VERSION 5.7 ;
  NOWIREEXTENSIONATPIN ON ;
  DIVIDERCHAR "/" ;
  BUSBITCHARS "[]" ;
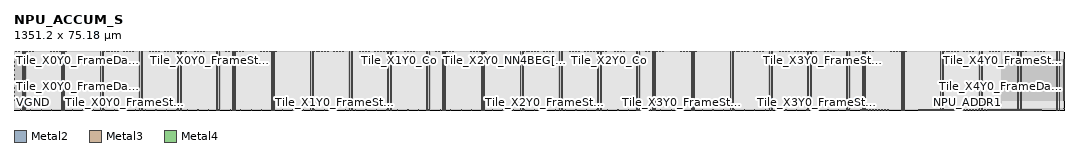
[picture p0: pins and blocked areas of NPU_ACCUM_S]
MACRO NPU_ACCUM_S
  CLASS BLOCK ;
  FOREIGN NPU_ACCUM_S ;
  ORIGIN 0.000 0.000 ;
  SIZE 1351.200 BY 75.180 ;
  PIN NPU_ADDR0
    DIRECTION OUTPUT ;
    USE SIGNAL ;
    ANTENNADIFFAREA 2.647800 ;
    PORT
      LAYER Metal2 ;
        RECT 1225.240 0.000 1225.640 0.400 ;
    END
  END NPU_ADDR0
  PIN NPU_ADDR1
    DIRECTION OUTPUT ;
    USE SIGNAL ;
    ANTENNADIFFAREA 2.647800 ;
    PORT
      LAYER Metal2 ;
        RECT 1227.160 0.000 1227.560 0.400 ;
    END
  END NPU_ADDR1
  PIN NPU_ADDR2
    DIRECTION OUTPUT ;
    USE SIGNAL ;
    ANTENNADIFFAREA 2.647800 ;
    PORT
      LAYER Metal2 ;
        RECT 1229.080 0.000 1229.480 0.400 ;
    END
  END NPU_ADDR2
  PIN NPU_ADDR3
    DIRECTION OUTPUT ;
    USE SIGNAL ;
    ANTENNADIFFAREA 2.647800 ;
    PORT
      LAYER Metal2 ;
        RECT 1231.000 0.000 1231.400 0.400 ;
    END
  END NPU_ADDR3
  PIN NPU_ADDR4
    DIRECTION OUTPUT ;
    USE SIGNAL ;
    ANTENNADIFFAREA 2.647800 ;
    PORT
      LAYER Metal2 ;
        RECT 1232.920 0.000 1233.320 0.400 ;
    END
  END NPU_ADDR4
  PIN NPU_ADDR5
    DIRECTION OUTPUT ;
    USE SIGNAL ;
    ANTENNADIFFAREA 2.647800 ;
    PORT
      LAYER Metal2 ;
        RECT 1234.840 0.000 1235.240 0.400 ;
    END
  END NPU_ADDR5
  PIN NPU_ADDR6
    DIRECTION OUTPUT ;
    USE SIGNAL ;
    ANTENNADIFFAREA 2.647800 ;
    PORT
      LAYER Metal2 ;
        RECT 1236.760 0.000 1237.160 0.400 ;
    END
  END NPU_ADDR6
  PIN NPU_ADDR7
    DIRECTION OUTPUT ;
    USE SIGNAL ;
    ANTENNADIFFAREA 2.647800 ;
    PORT
      LAYER Metal2 ;
        RECT 1238.680 0.000 1239.080 0.400 ;
    END
  END NPU_ADDR7
  PIN NPU_RDATA0
    DIRECTION INPUT ;
    USE SIGNAL ;
    ANTENNAGATEAREA 0.109200 ;
    ANTENNADIFFAREA 2.015400 ;
    PORT
      LAYER Metal2 ;
        RECT 1163.800 0.000 1164.200 0.400 ;
    END
  END NPU_RDATA0
  PIN NPU_RDATA1
    DIRECTION INPUT ;
    USE SIGNAL ;
    ANTENNAGATEAREA 0.109200 ;
    ANTENNADIFFAREA 2.015400 ;
    PORT
      LAYER Metal2 ;
        RECT 1165.720 0.000 1166.120 0.400 ;
    END
  END NPU_RDATA1
  PIN NPU_RDATA10
    DIRECTION INPUT ;
    USE SIGNAL ;
    ANTENNAGATEAREA 0.109200 ;
    ANTENNADIFFAREA 2.015400 ;
    PORT
      LAYER Metal2 ;
        RECT 1183.000 0.000 1183.400 0.400 ;
    END
  END NPU_RDATA10
  PIN NPU_RDATA11
    DIRECTION INPUT ;
    USE SIGNAL ;
    ANTENNAGATEAREA 0.109200 ;
    ANTENNADIFFAREA 2.015400 ;
    PORT
      LAYER Metal2 ;
        RECT 1184.920 0.000 1185.320 0.400 ;
    END
  END NPU_RDATA11
  PIN NPU_RDATA12
    DIRECTION INPUT ;
    USE SIGNAL ;
    ANTENNAGATEAREA 0.109200 ;
    ANTENNADIFFAREA 2.015400 ;
    PORT
      LAYER Metal2 ;
        RECT 1186.840 0.000 1187.240 0.400 ;
    END
  END NPU_RDATA12
  PIN NPU_RDATA13
    DIRECTION INPUT ;
    USE SIGNAL ;
    ANTENNAGATEAREA 0.109200 ;
    ANTENNADIFFAREA 2.015400 ;
    PORT
      LAYER Metal2 ;
        RECT 1188.760 0.000 1189.160 0.400 ;
    END
  END NPU_RDATA13
  PIN NPU_RDATA14
    DIRECTION INPUT ;
    USE SIGNAL ;
    ANTENNAGATEAREA 0.109200 ;
    ANTENNADIFFAREA 2.015400 ;
    PORT
      LAYER Metal2 ;
        RECT 1190.680 0.000 1191.080 0.400 ;
    END
  END NPU_RDATA14
  PIN NPU_RDATA15
    DIRECTION INPUT ;
    USE SIGNAL ;
    ANTENNAGATEAREA 0.109200 ;
    ANTENNADIFFAREA 2.015400 ;
    PORT
      LAYER Metal2 ;
        RECT 1192.600 0.000 1193.000 0.400 ;
    END
  END NPU_RDATA15
  PIN NPU_RDATA16
    DIRECTION INPUT ;
    USE SIGNAL ;
    ANTENNAGATEAREA 0.109200 ;
    ANTENNADIFFAREA 2.015400 ;
    PORT
      LAYER Metal2 ;
        RECT 1194.520 0.000 1194.920 0.400 ;
    END
  END NPU_RDATA16
  PIN NPU_RDATA17
    DIRECTION INPUT ;
    USE SIGNAL ;
    ANTENNAGATEAREA 0.109200 ;
    ANTENNADIFFAREA 2.015400 ;
    PORT
      LAYER Metal2 ;
        RECT 1196.440 0.000 1196.840 0.400 ;
    END
  END NPU_RDATA17
  PIN NPU_RDATA18
    DIRECTION INPUT ;
    USE SIGNAL ;
    ANTENNAGATEAREA 0.109200 ;
    ANTENNADIFFAREA 2.015400 ;
    PORT
      LAYER Metal2 ;
        RECT 1198.360 0.000 1198.760 0.400 ;
    END
  END NPU_RDATA18
  PIN NPU_RDATA19
    DIRECTION INPUT ;
    USE SIGNAL ;
    ANTENNAGATEAREA 0.109200 ;
    ANTENNADIFFAREA 2.015400 ;
    PORT
      LAYER Metal2 ;
        RECT 1200.280 0.000 1200.680 0.400 ;
    END
  END NPU_RDATA19
  PIN NPU_RDATA2
    DIRECTION INPUT ;
    USE SIGNAL ;
    ANTENNAGATEAREA 0.109200 ;
    ANTENNADIFFAREA 2.015400 ;
    PORT
      LAYER Metal2 ;
        RECT 1167.640 0.000 1168.040 0.400 ;
    END
  END NPU_RDATA2
  PIN NPU_RDATA20
    DIRECTION INPUT ;
    USE SIGNAL ;
    ANTENNAGATEAREA 0.109200 ;
    ANTENNADIFFAREA 2.015400 ;
    PORT
      LAYER Metal2 ;
        RECT 1202.200 0.000 1202.600 0.400 ;
    END
  END NPU_RDATA20
  PIN NPU_RDATA21
    DIRECTION INPUT ;
    USE SIGNAL ;
    ANTENNAGATEAREA 0.109200 ;
    ANTENNADIFFAREA 2.015400 ;
    PORT
      LAYER Metal2 ;
        RECT 1204.120 0.000 1204.520 0.400 ;
    END
  END NPU_RDATA21
  PIN NPU_RDATA22
    DIRECTION INPUT ;
    USE SIGNAL ;
    ANTENNAGATEAREA 0.109200 ;
    ANTENNADIFFAREA 2.015400 ;
    PORT
      LAYER Metal2 ;
        RECT 1206.040 0.000 1206.440 0.400 ;
    END
  END NPU_RDATA22
  PIN NPU_RDATA23
    DIRECTION INPUT ;
    USE SIGNAL ;
    ANTENNAGATEAREA 0.109200 ;
    ANTENNADIFFAREA 2.015400 ;
    PORT
      LAYER Metal2 ;
        RECT 1207.960 0.000 1208.360 0.400 ;
    END
  END NPU_RDATA23
  PIN NPU_RDATA24
    DIRECTION INPUT ;
    USE SIGNAL ;
    ANTENNAGATEAREA 0.109200 ;
    ANTENNADIFFAREA 2.015400 ;
    PORT
      LAYER Metal2 ;
        RECT 1209.880 0.000 1210.280 0.400 ;
    END
  END NPU_RDATA24
  PIN NPU_RDATA25
    DIRECTION INPUT ;
    USE SIGNAL ;
    ANTENNAGATEAREA 0.109200 ;
    ANTENNADIFFAREA 2.015400 ;
    PORT
      LAYER Metal2 ;
        RECT 1211.800 0.000 1212.200 0.400 ;
    END
  END NPU_RDATA25
  PIN NPU_RDATA26
    DIRECTION INPUT ;
    USE SIGNAL ;
    ANTENNAGATEAREA 0.109200 ;
    ANTENNADIFFAREA 2.015400 ;
    PORT
      LAYER Metal2 ;
        RECT 1213.720 0.000 1214.120 0.400 ;
    END
  END NPU_RDATA26
  PIN NPU_RDATA27
    DIRECTION INPUT ;
    USE SIGNAL ;
    ANTENNAGATEAREA 0.109200 ;
    ANTENNADIFFAREA 2.015400 ;
    PORT
      LAYER Metal2 ;
        RECT 1215.640 0.000 1216.040 0.400 ;
    END
  END NPU_RDATA27
  PIN NPU_RDATA28
    DIRECTION INPUT ;
    USE SIGNAL ;
    ANTENNAGATEAREA 0.109200 ;
    ANTENNADIFFAREA 2.015400 ;
    PORT
      LAYER Metal2 ;
        RECT 1217.560 0.000 1217.960 0.400 ;
    END
  END NPU_RDATA28
  PIN NPU_RDATA29
    DIRECTION INPUT ;
    USE SIGNAL ;
    ANTENNAGATEAREA 0.109200 ;
    ANTENNADIFFAREA 2.015400 ;
    PORT
      LAYER Metal2 ;
        RECT 1219.480 0.000 1219.880 0.400 ;
    END
  END NPU_RDATA29
  PIN NPU_RDATA3
    DIRECTION INPUT ;
    USE SIGNAL ;
    ANTENNAGATEAREA 0.109200 ;
    ANTENNADIFFAREA 2.015400 ;
    PORT
      LAYER Metal2 ;
        RECT 1169.560 0.000 1169.960 0.400 ;
    END
  END NPU_RDATA3
  PIN NPU_RDATA30
    DIRECTION INPUT ;
    USE SIGNAL ;
    ANTENNAGATEAREA 0.109200 ;
    ANTENNADIFFAREA 2.015400 ;
    PORT
      LAYER Metal2 ;
        RECT 1221.400 0.000 1221.800 0.400 ;
    END
  END NPU_RDATA30
  PIN NPU_RDATA31
    DIRECTION INPUT ;
    USE SIGNAL ;
    ANTENNAGATEAREA 0.109200 ;
    ANTENNADIFFAREA 2.015400 ;
    PORT
      LAYER Metal2 ;
        RECT 1223.320 0.000 1223.720 0.400 ;
    END
  END NPU_RDATA31
  PIN NPU_RDATA4
    DIRECTION INPUT ;
    USE SIGNAL ;
    ANTENNAGATEAREA 0.109200 ;
    ANTENNADIFFAREA 2.015400 ;
    PORT
      LAYER Metal2 ;
        RECT 1171.480 0.000 1171.880 0.400 ;
    END
  END NPU_RDATA4
  PIN NPU_RDATA5
    DIRECTION INPUT ;
    USE SIGNAL ;
    ANTENNAGATEAREA 0.109200 ;
    ANTENNADIFFAREA 2.015400 ;
    PORT
      LAYER Metal2 ;
        RECT 1173.400 0.000 1173.800 0.400 ;
    END
  END NPU_RDATA5
  PIN NPU_RDATA6
    DIRECTION INPUT ;
    USE SIGNAL ;
    ANTENNAGATEAREA 0.109200 ;
    ANTENNADIFFAREA 2.015400 ;
    PORT
      LAYER Metal2 ;
        RECT 1175.320 0.000 1175.720 0.400 ;
    END
  END NPU_RDATA6
  PIN NPU_RDATA7
    DIRECTION INPUT ;
    USE SIGNAL ;
    ANTENNAGATEAREA 0.109200 ;
    ANTENNADIFFAREA 2.015400 ;
    PORT
      LAYER Metal2 ;
        RECT 1177.240 0.000 1177.640 0.400 ;
    END
  END NPU_RDATA7
  PIN NPU_RDATA8
    DIRECTION INPUT ;
    USE SIGNAL ;
    ANTENNAGATEAREA 0.109200 ;
    ANTENNADIFFAREA 2.015400 ;
    PORT
      LAYER Metal2 ;
        RECT 1179.160 0.000 1179.560 0.400 ;
    END
  END NPU_RDATA8
  PIN NPU_RDATA9
    DIRECTION INPUT ;
    USE SIGNAL ;
    ANTENNAGATEAREA 0.109200 ;
    ANTENNADIFFAREA 2.015400 ;
    PORT
      LAYER Metal2 ;
        RECT 1181.080 0.000 1181.480 0.400 ;
    END
  END NPU_RDATA9
  PIN NPU_READ_BANK_SEL0
    DIRECTION OUTPUT ;
    USE SIGNAL ;
    ANTENNADIFFAREA 2.647800 ;
    PORT
      LAYER Metal2 ;
        RECT 1317.400 0.000 1317.800 0.400 ;
    END
  END NPU_READ_BANK_SEL0
  PIN NPU_READ_BANK_SEL1
    DIRECTION OUTPUT ;
    USE SIGNAL ;
    ANTENNADIFFAREA 2.647800 ;
    PORT
      LAYER Metal2 ;
        RECT 1319.320 0.000 1319.720 0.400 ;
    END
  END NPU_READ_BANK_SEL1
  PIN NPU_READ_BANK_SEL2
    DIRECTION OUTPUT ;
    USE SIGNAL ;
    ANTENNADIFFAREA 2.647800 ;
    PORT
      LAYER Metal2 ;
        RECT 1321.240 0.000 1321.640 0.400 ;
    END
  END NPU_READ_BANK_SEL2
  PIN NPU_WDATA0
    DIRECTION OUTPUT ;
    USE SIGNAL ;
    ANTENNADIFFAREA 2.647800 ;
    PORT
      LAYER Metal2 ;
        RECT 1255.960 0.000 1256.360 0.400 ;
    END
  END NPU_WDATA0
  PIN NPU_WDATA1
    DIRECTION OUTPUT ;
    USE SIGNAL ;
    ANTENNADIFFAREA 2.647800 ;
    PORT
      LAYER Metal2 ;
        RECT 1257.880 0.000 1258.280 0.400 ;
    END
  END NPU_WDATA1
  PIN NPU_WDATA10
    DIRECTION OUTPUT ;
    USE SIGNAL ;
    ANTENNADIFFAREA 2.647800 ;
    PORT
      LAYER Metal2 ;
        RECT 1275.160 0.000 1275.560 0.400 ;
    END
  END NPU_WDATA10
  PIN NPU_WDATA11
    DIRECTION OUTPUT ;
    USE SIGNAL ;
    ANTENNADIFFAREA 2.647800 ;
    PORT
      LAYER Metal2 ;
        RECT 1277.080 0.000 1277.480 0.400 ;
    END
  END NPU_WDATA11
  PIN NPU_WDATA12
    DIRECTION OUTPUT ;
    USE SIGNAL ;
    ANTENNADIFFAREA 2.647800 ;
    PORT
      LAYER Metal2 ;
        RECT 1279.000 0.000 1279.400 0.400 ;
    END
  END NPU_WDATA12
  PIN NPU_WDATA13
    DIRECTION OUTPUT ;
    USE SIGNAL ;
    ANTENNADIFFAREA 2.647800 ;
    PORT
      LAYER Metal2 ;
        RECT 1280.920 0.000 1281.320 0.400 ;
    END
  END NPU_WDATA13
  PIN NPU_WDATA14
    DIRECTION OUTPUT ;
    USE SIGNAL ;
    ANTENNADIFFAREA 2.647800 ;
    PORT
      LAYER Metal2 ;
        RECT 1282.840 0.000 1283.240 0.400 ;
    END
  END NPU_WDATA14
  PIN NPU_WDATA15
    DIRECTION OUTPUT ;
    USE SIGNAL ;
    ANTENNADIFFAREA 2.647800 ;
    PORT
      LAYER Metal2 ;
        RECT 1284.760 0.000 1285.160 0.400 ;
    END
  END NPU_WDATA15
  PIN NPU_WDATA16
    DIRECTION OUTPUT ;
    USE SIGNAL ;
    ANTENNADIFFAREA 2.647800 ;
    PORT
      LAYER Metal2 ;
        RECT 1286.680 0.000 1287.080 0.400 ;
    END
  END NPU_WDATA16
  PIN NPU_WDATA17
    DIRECTION OUTPUT ;
    USE SIGNAL ;
    ANTENNADIFFAREA 2.647800 ;
    PORT
      LAYER Metal2 ;
        RECT 1288.600 0.000 1289.000 0.400 ;
    END
  END NPU_WDATA17
  PIN NPU_WDATA18
    DIRECTION OUTPUT ;
    USE SIGNAL ;
    ANTENNADIFFAREA 2.647800 ;
    PORT
      LAYER Metal2 ;
        RECT 1290.520 0.000 1290.920 0.400 ;
    END
  END NPU_WDATA18
  PIN NPU_WDATA19
    DIRECTION OUTPUT ;
    USE SIGNAL ;
    ANTENNADIFFAREA 2.647800 ;
    PORT
      LAYER Metal2 ;
        RECT 1292.440 0.000 1292.840 0.400 ;
    END
  END NPU_WDATA19
  PIN NPU_WDATA2
    DIRECTION OUTPUT ;
    USE SIGNAL ;
    ANTENNADIFFAREA 2.647800 ;
    PORT
      LAYER Metal2 ;
        RECT 1259.800 0.000 1260.200 0.400 ;
    END
  END NPU_WDATA2
  PIN NPU_WDATA20
    DIRECTION OUTPUT ;
    USE SIGNAL ;
    ANTENNADIFFAREA 2.647800 ;
    PORT
      LAYER Metal2 ;
        RECT 1294.360 0.000 1294.760 0.400 ;
    END
  END NPU_WDATA20
  PIN NPU_WDATA21
    DIRECTION OUTPUT ;
    USE SIGNAL ;
    ANTENNADIFFAREA 2.647800 ;
    PORT
      LAYER Metal2 ;
        RECT 1296.280 0.000 1296.680 0.400 ;
    END
  END NPU_WDATA21
  PIN NPU_WDATA22
    DIRECTION OUTPUT ;
    USE SIGNAL ;
    ANTENNADIFFAREA 2.647800 ;
    PORT
      LAYER Metal2 ;
        RECT 1298.200 0.000 1298.600 0.400 ;
    END
  END NPU_WDATA22
  PIN NPU_WDATA23
    DIRECTION OUTPUT ;
    USE SIGNAL ;
    ANTENNADIFFAREA 2.647800 ;
    PORT
      LAYER Metal2 ;
        RECT 1300.120 0.000 1300.520 0.400 ;
    END
  END NPU_WDATA23
  PIN NPU_WDATA24
    DIRECTION OUTPUT ;
    USE SIGNAL ;
    ANTENNADIFFAREA 2.647800 ;
    PORT
      LAYER Metal2 ;
        RECT 1302.040 0.000 1302.440 0.400 ;
    END
  END NPU_WDATA24
  PIN NPU_WDATA25
    DIRECTION OUTPUT ;
    USE SIGNAL ;
    ANTENNADIFFAREA 2.647800 ;
    PORT
      LAYER Metal2 ;
        RECT 1303.960 0.000 1304.360 0.400 ;
    END
  END NPU_WDATA25
  PIN NPU_WDATA26
    DIRECTION OUTPUT ;
    USE SIGNAL ;
    ANTENNADIFFAREA 2.647800 ;
    PORT
      LAYER Metal2 ;
        RECT 1305.880 0.000 1306.280 0.400 ;
    END
  END NPU_WDATA26
  PIN NPU_WDATA27
    DIRECTION OUTPUT ;
    USE SIGNAL ;
    ANTENNADIFFAREA 2.647800 ;
    PORT
      LAYER Metal2 ;
        RECT 1307.800 0.000 1308.200 0.400 ;
    END
  END NPU_WDATA27
  PIN NPU_WDATA28
    DIRECTION OUTPUT ;
    USE SIGNAL ;
    ANTENNADIFFAREA 2.647800 ;
    PORT
      LAYER Metal2 ;
        RECT 1309.720 0.000 1310.120 0.400 ;
    END
  END NPU_WDATA28
  PIN NPU_WDATA29
    DIRECTION OUTPUT ;
    USE SIGNAL ;
    ANTENNADIFFAREA 2.647800 ;
    PORT
      LAYER Metal2 ;
        RECT 1311.640 0.000 1312.040 0.400 ;
    END
  END NPU_WDATA29
  PIN NPU_WDATA3
    DIRECTION OUTPUT ;
    USE SIGNAL ;
    ANTENNADIFFAREA 2.647800 ;
    PORT
      LAYER Metal2 ;
        RECT 1261.720 0.000 1262.120 0.400 ;
    END
  END NPU_WDATA3
  PIN NPU_WDATA30
    DIRECTION OUTPUT ;
    USE SIGNAL ;
    ANTENNADIFFAREA 2.647800 ;
    PORT
      LAYER Metal2 ;
        RECT 1313.560 0.000 1313.960 0.400 ;
    END
  END NPU_WDATA30
  PIN NPU_WDATA31
    DIRECTION OUTPUT ;
    USE SIGNAL ;
    ANTENNADIFFAREA 2.647800 ;
    PORT
      LAYER Metal2 ;
        RECT 1315.480 0.000 1315.880 0.400 ;
    END
  END NPU_WDATA31
  PIN NPU_WDATA4
    DIRECTION OUTPUT ;
    USE SIGNAL ;
    ANTENNADIFFAREA 2.647800 ;
    PORT
      LAYER Metal2 ;
        RECT 1263.640 0.000 1264.040 0.400 ;
    END
  END NPU_WDATA4
  PIN NPU_WDATA5
    DIRECTION OUTPUT ;
    USE SIGNAL ;
    ANTENNADIFFAREA 2.647800 ;
    PORT
      LAYER Metal2 ;
        RECT 1265.560 0.000 1265.960 0.400 ;
    END
  END NPU_WDATA5
  PIN NPU_WDATA6
    DIRECTION OUTPUT ;
    USE SIGNAL ;
    ANTENNADIFFAREA 2.647800 ;
    PORT
      LAYER Metal2 ;
        RECT 1267.480 0.000 1267.880 0.400 ;
    END
  END NPU_WDATA6
  PIN NPU_WDATA7
    DIRECTION OUTPUT ;
    USE SIGNAL ;
    ANTENNADIFFAREA 2.647800 ;
    PORT
      LAYER Metal2 ;
        RECT 1269.400 0.000 1269.800 0.400 ;
    END
  END NPU_WDATA7
  PIN NPU_WDATA8
    DIRECTION OUTPUT ;
    USE SIGNAL ;
    ANTENNADIFFAREA 2.647800 ;
    PORT
      LAYER Metal2 ;
        RECT 1271.320 0.000 1271.720 0.400 ;
    END
  END NPU_WDATA8
  PIN NPU_WDATA9
    DIRECTION OUTPUT ;
    USE SIGNAL ;
    ANTENNADIFFAREA 2.647800 ;
    PORT
      LAYER Metal2 ;
        RECT 1273.240 0.000 1273.640 0.400 ;
    END
  END NPU_WDATA9
  PIN NPU_WE0
    DIRECTION OUTPUT ;
    USE SIGNAL ;
    ANTENNADIFFAREA 2.647800 ;
    PORT
      LAYER Metal2 ;
        RECT 1240.600 0.000 1241.000 0.400 ;
    END
  END NPU_WE0
  PIN NPU_WE1
    DIRECTION OUTPUT ;
    USE SIGNAL ;
    ANTENNADIFFAREA 2.647800 ;
    PORT
      LAYER Metal2 ;
        RECT 1242.520 0.000 1242.920 0.400 ;
    END
  END NPU_WE1
  PIN NPU_WE2
    DIRECTION OUTPUT ;
    USE SIGNAL ;
    ANTENNADIFFAREA 2.647800 ;
    PORT
      LAYER Metal2 ;
        RECT 1244.440 0.000 1244.840 0.400 ;
    END
  END NPU_WE2
  PIN NPU_WE3
    DIRECTION OUTPUT ;
    USE SIGNAL ;
    ANTENNADIFFAREA 2.647800 ;
    PORT
      LAYER Metal2 ;
        RECT 1246.360 0.000 1246.760 0.400 ;
    END
  END NPU_WE3
  PIN NPU_WE4
    DIRECTION OUTPUT ;
    USE SIGNAL ;
    ANTENNADIFFAREA 2.647800 ;
    PORT
      LAYER Metal2 ;
        RECT 1248.280 0.000 1248.680 0.400 ;
    END
  END NPU_WE4
  PIN NPU_WE5
    DIRECTION OUTPUT ;
    USE SIGNAL ;
    ANTENNADIFFAREA 2.647800 ;
    PORT
      LAYER Metal2 ;
        RECT 1250.200 0.000 1250.600 0.400 ;
    END
  END NPU_WE5
  PIN NPU_WE6
    DIRECTION OUTPUT ;
    USE SIGNAL ;
    ANTENNADIFFAREA 2.647800 ;
    PORT
      LAYER Metal2 ;
        RECT 1252.120 0.000 1252.520 0.400 ;
    END
  END NPU_WE6
  PIN NPU_WE7
    DIRECTION OUTPUT ;
    USE SIGNAL ;
    ANTENNADIFFAREA 2.647800 ;
    PORT
      LAYER Metal2 ;
        RECT 1254.040 0.000 1254.440 0.400 ;
    END
  END NPU_WE7
  PIN Tile_X0Y0_Co
    DIRECTION OUTPUT ;
    USE SIGNAL ;
    ANTENNADIFFAREA 2.314600 ;
    PORT
      LAYER Metal2 ;
        RECT 225.880 74.780 226.280 75.180 ;
    END
  END Tile_X0Y0_Co
  PIN Tile_X0Y0_FrameData[0]
    DIRECTION INPUT ;
    USE SIGNAL ;
    ANTENNAGATEAREA 2.349100 ;
    ANTENNADIFFAREA 28.215599 ;
    PORT
      LAYER Metal3 ;
        RECT 0.000 12.820 0.400 13.220 ;
    END
  END Tile_X0Y0_FrameData[0]
  PIN Tile_X0Y0_FrameData[10]
    DIRECTION INPUT ;
    USE SIGNAL ;
    ANTENNAGATEAREA 2.349100 ;
    ANTENNADIFFAREA 34.261799 ;
    PORT
      LAYER Metal3 ;
        RECT 0.000 29.620 0.400 30.020 ;
    END
  END Tile_X0Y0_FrameData[10]
  PIN Tile_X0Y0_FrameData[11]
    DIRECTION INPUT ;
    USE SIGNAL ;
    ANTENNAGATEAREA 2.349100 ;
    ANTENNADIFFAREA 34.261799 ;
    PORT
      LAYER Metal3 ;
        RECT 0.000 31.300 0.400 31.700 ;
    END
  END Tile_X0Y0_FrameData[11]
  PIN Tile_X0Y0_FrameData[12]
    DIRECTION INPUT ;
    USE SIGNAL ;
    ANTENNAGATEAREA 2.349100 ;
    ANTENNADIFFAREA 30.230999 ;
    PORT
      LAYER Metal3 ;
        RECT 0.000 32.980 0.400 33.380 ;
    END
  END Tile_X0Y0_FrameData[12]
  PIN Tile_X0Y0_FrameData[13]
    DIRECTION INPUT ;
    USE SIGNAL ;
    ANTENNAGATEAREA 2.349100 ;
    ANTENNADIFFAREA 28.215599 ;
    PORT
      LAYER Metal3 ;
        RECT 0.000 34.660 0.400 35.060 ;
    END
  END Tile_X0Y0_FrameData[13]
  PIN Tile_X0Y0_FrameData[14]
    DIRECTION INPUT ;
    USE SIGNAL ;
    ANTENNAGATEAREA 2.349100 ;
    ANTENNADIFFAREA 34.261799 ;
    PORT
      LAYER Metal3 ;
        RECT 0.000 36.340 0.400 36.740 ;
    END
  END Tile_X0Y0_FrameData[14]
  PIN Tile_X0Y0_FrameData[15]
    DIRECTION INPUT ;
    USE SIGNAL ;
    ANTENNAGATEAREA 2.349100 ;
    ANTENNADIFFAREA 34.261799 ;
    PORT
      LAYER Metal3 ;
        RECT 0.000 38.020 0.400 38.420 ;
    END
  END Tile_X0Y0_FrameData[15]
  PIN Tile_X0Y0_FrameData[16]
    DIRECTION INPUT ;
    USE SIGNAL ;
    ANTENNAGATEAREA 2.710500 ;
    ANTENNADIFFAREA 32.246399 ;
    PORT
      LAYER Metal3 ;
        RECT 0.000 39.700 0.400 40.100 ;
    END
  END Tile_X0Y0_FrameData[16]
  PIN Tile_X0Y0_FrameData[17]
    DIRECTION INPUT ;
    USE SIGNAL ;
    ANTENNAGATEAREA 2.710500 ;
    ANTENNADIFFAREA 38.292599 ;
    PORT
      LAYER Metal3 ;
        RECT 0.000 41.380 0.400 41.780 ;
    END
  END Tile_X0Y0_FrameData[17]
  PIN Tile_X0Y0_FrameData[18]
    DIRECTION INPUT ;
    USE SIGNAL ;
    ANTENNAGATEAREA 2.891200 ;
    ANTENNADIFFAREA 32.246399 ;
    PORT
      LAYER Metal3 ;
        RECT 0.000 43.060 0.400 43.460 ;
    END
  END Tile_X0Y0_FrameData[18]
  PIN Tile_X0Y0_FrameData[19]
    DIRECTION INPUT ;
    USE SIGNAL ;
    ANTENNAGATEAREA 2.891200 ;
    ANTENNADIFFAREA 32.246399 ;
    PORT
      LAYER Metal3 ;
        RECT 0.000 44.740 0.400 45.140 ;
    END
  END Tile_X0Y0_FrameData[19]
  PIN Tile_X0Y0_FrameData[1]
    DIRECTION INPUT ;
    USE SIGNAL ;
    ANTENNAGATEAREA 2.349100 ;
    ANTENNADIFFAREA 36.277199 ;
    PORT
      LAYER Metal3 ;
        RECT 0.000 14.500 0.400 14.900 ;
    END
  END Tile_X0Y0_FrameData[1]
  PIN Tile_X0Y0_FrameData[20]
    DIRECTION INPUT ;
    USE SIGNAL ;
    ANTENNAGATEAREA 2.891200 ;
    ANTENNADIFFAREA 32.246399 ;
    PORT
      LAYER Metal3 ;
        RECT 0.000 46.420 0.400 46.820 ;
    END
  END Tile_X0Y0_FrameData[20]
  PIN Tile_X0Y0_FrameData[21]
    DIRECTION INPUT ;
    USE SIGNAL ;
    ANTENNAGATEAREA 2.891200 ;
    ANTENNADIFFAREA 34.261799 ;
    PORT
      LAYER Metal3 ;
        RECT 0.000 48.100 0.400 48.500 ;
    END
  END Tile_X0Y0_FrameData[21]
  PIN Tile_X0Y0_FrameData[22]
    DIRECTION INPUT ;
    USE SIGNAL ;
    ANTENNAGATEAREA 2.891200 ;
    ANTENNADIFFAREA 32.246399 ;
    PORT
      LAYER Metal3 ;
        RECT 0.000 49.780 0.400 50.180 ;
    END
  END Tile_X0Y0_FrameData[22]
  PIN Tile_X0Y0_FrameData[23]
    DIRECTION INPUT ;
    USE SIGNAL ;
    ANTENNAGATEAREA 2.891200 ;
    ANTENNADIFFAREA 32.246399 ;
    PORT
      LAYER Metal3 ;
        RECT 0.000 51.460 0.400 51.860 ;
    END
  END Tile_X0Y0_FrameData[23]
  PIN Tile_X0Y0_FrameData[24]
    DIRECTION INPUT ;
    USE SIGNAL ;
    ANTENNAGATEAREA 2.891200 ;
    ANTENNADIFFAREA 36.277199 ;
    PORT
      LAYER Metal3 ;
        RECT 0.000 53.140 0.400 53.540 ;
    END
  END Tile_X0Y0_FrameData[24]
  PIN Tile_X0Y0_FrameData[25]
    DIRECTION INPUT ;
    USE SIGNAL ;
    ANTENNAGATEAREA 2.891200 ;
    ANTENNADIFFAREA 34.261799 ;
    PORT
      LAYER Metal3 ;
        RECT 0.000 54.820 0.400 55.220 ;
    END
  END Tile_X0Y0_FrameData[25]
  PIN Tile_X0Y0_FrameData[26]
    DIRECTION INPUT ;
    USE SIGNAL ;
    ANTENNAGATEAREA 2.891200 ;
    ANTENNADIFFAREA 36.277199 ;
    PORT
      LAYER Metal3 ;
        RECT 0.000 56.500 0.400 56.900 ;
    END
  END Tile_X0Y0_FrameData[26]
  PIN Tile_X0Y0_FrameData[27]
    DIRECTION INPUT ;
    USE SIGNAL ;
    ANTENNAGATEAREA 2.891200 ;
    ANTENNADIFFAREA 32.246399 ;
    PORT
      LAYER Metal3 ;
        RECT 0.000 58.180 0.400 58.580 ;
    END
  END Tile_X0Y0_FrameData[27]
  PIN Tile_X0Y0_FrameData[28]
    DIRECTION INPUT ;
    USE SIGNAL ;
    ANTENNAGATEAREA 2.891200 ;
    ANTENNADIFFAREA 36.277199 ;
    PORT
      LAYER Metal3 ;
        RECT 0.000 59.860 0.400 60.260 ;
    END
  END Tile_X0Y0_FrameData[28]
  PIN Tile_X0Y0_FrameData[29]
    DIRECTION INPUT ;
    USE SIGNAL ;
    ANTENNAGATEAREA 2.891200 ;
    ANTENNADIFFAREA 34.261799 ;
    PORT
      LAYER Metal3 ;
        RECT 0.000 61.540 0.400 61.940 ;
    END
  END Tile_X0Y0_FrameData[29]
  PIN Tile_X0Y0_FrameData[2]
    DIRECTION INPUT ;
    USE SIGNAL ;
    ANTENNAGATEAREA 2.349100 ;
    ANTENNADIFFAREA 30.230999 ;
    PORT
      LAYER Metal3 ;
        RECT 0.000 16.180 0.400 16.580 ;
    END
  END Tile_X0Y0_FrameData[2]
  PIN Tile_X0Y0_FrameData[30]
    DIRECTION INPUT ;
    USE SIGNAL ;
    ANTENNAGATEAREA 2.891200 ;
    ANTENNADIFFAREA 34.261799 ;
    PORT
      LAYER Metal3 ;
        RECT 0.000 63.220 0.400 63.620 ;
    END
  END Tile_X0Y0_FrameData[30]
  PIN Tile_X0Y0_FrameData[31]
    DIRECTION INPUT ;
    USE SIGNAL ;
    ANTENNAGATEAREA 2.891200 ;
    ANTENNADIFFAREA 34.261799 ;
    PORT
      LAYER Metal3 ;
        RECT 0.000 64.900 0.400 65.300 ;
    END
  END Tile_X0Y0_FrameData[31]
  PIN Tile_X0Y0_FrameData[3]
    DIRECTION INPUT ;
    USE SIGNAL ;
    ANTENNAGATEAREA 2.349100 ;
    ANTENNADIFFAREA 30.230999 ;
    PORT
      LAYER Metal3 ;
        RECT 0.000 17.860 0.400 18.260 ;
    END
  END Tile_X0Y0_FrameData[3]
  PIN Tile_X0Y0_FrameData[4]
    DIRECTION INPUT ;
    USE SIGNAL ;
    ANTENNAGATEAREA 2.349100 ;
    ANTENNADIFFAREA 28.215599 ;
    PORT
      LAYER Metal3 ;
        RECT 0.000 19.540 0.400 19.940 ;
    END
  END Tile_X0Y0_FrameData[4]
  PIN Tile_X0Y0_FrameData[5]
    DIRECTION INPUT ;
    USE SIGNAL ;
    ANTENNAGATEAREA 2.349100 ;
    ANTENNADIFFAREA 30.230999 ;
    PORT
      LAYER Metal3 ;
        RECT 0.000 21.220 0.400 21.620 ;
    END
  END Tile_X0Y0_FrameData[5]
  PIN Tile_X0Y0_FrameData[6]
    DIRECTION INPUT ;
    USE SIGNAL ;
    ANTENNAGATEAREA 2.349100 ;
    ANTENNADIFFAREA 28.215599 ;
    PORT
      LAYER Metal3 ;
        RECT 0.000 22.900 0.400 23.300 ;
    END
  END Tile_X0Y0_FrameData[6]
  PIN Tile_X0Y0_FrameData[7]
    DIRECTION INPUT ;
    USE SIGNAL ;
    ANTENNAGATEAREA 2.349100 ;
    ANTENNADIFFAREA 28.215599 ;
    PORT
      LAYER Metal3 ;
        RECT 0.000 24.580 0.400 24.980 ;
    END
  END Tile_X0Y0_FrameData[7]
  PIN Tile_X0Y0_FrameData[8]
    DIRECTION INPUT ;
    USE SIGNAL ;
    ANTENNAGATEAREA 2.349100 ;
    ANTENNADIFFAREA 40.307999 ;
    PORT
      LAYER Metal3 ;
        RECT 0.000 26.260 0.400 26.660 ;
    END
  END Tile_X0Y0_FrameData[8]
  PIN Tile_X0Y0_FrameData[9]
    DIRECTION INPUT ;
    USE SIGNAL ;
    ANTENNAGATEAREA 2.349100 ;
    ANTENNADIFFAREA 34.261799 ;
    PORT
      LAYER Metal3 ;
        RECT 0.000 27.940 0.400 28.340 ;
    END
  END Tile_X0Y0_FrameData[9]
  PIN Tile_X0Y0_FrameStrobe[0]
    DIRECTION INPUT ;
    USE SIGNAL ;
    ANTENNAGATEAREA 11.745500 ;
    ANTENNADIFFAREA 66.508202 ;
    PORT
      LAYER Metal2 ;
        RECT 7.960 0.000 8.360 0.400 ;
    END
  END Tile_X0Y0_FrameStrobe[0]
  PIN Tile_X0Y0_FrameStrobe[10]
    DIRECTION INPUT ;
    USE SIGNAL ;
    ANTENNAGATEAREA 0.180700 ;
    ANTENNADIFFAREA 2.015400 ;
    PORT
      LAYER Metal2 ;
        RECT 142.360 0.000 142.760 0.400 ;
    END
  END Tile_X0Y0_FrameStrobe[10]
  PIN Tile_X0Y0_FrameStrobe[11]
    DIRECTION INPUT ;
    USE SIGNAL ;
    ANTENNAGATEAREA 0.180700 ;
    ANTENNADIFFAREA 2.015400 ;
    PORT
      LAYER Metal2 ;
        RECT 155.800 0.000 156.200 0.400 ;
    END
  END Tile_X0Y0_FrameStrobe[11]
  PIN Tile_X0Y0_FrameStrobe[12]
    DIRECTION INPUT ;
    USE SIGNAL ;
    ANTENNAGATEAREA 0.180700 ;
    ANTENNADIFFAREA 2.015400 ;
    PORT
      LAYER Metal2 ;
        RECT 169.240 0.000 169.640 0.400 ;
    END
  END Tile_X0Y0_FrameStrobe[12]
  PIN Tile_X0Y0_FrameStrobe[13]
    DIRECTION INPUT ;
    USE SIGNAL ;
    ANTENNAGATEAREA 0.180700 ;
    ANTENNADIFFAREA 2.015400 ;
    PORT
      LAYER Metal2 ;
        RECT 182.680 0.000 183.080 0.400 ;
    END
  END Tile_X0Y0_FrameStrobe[13]
  PIN Tile_X0Y0_FrameStrobe[14]
    DIRECTION INPUT ;
    USE SIGNAL ;
    ANTENNAGATEAREA 0.180700 ;
    ANTENNADIFFAREA 2.015400 ;
    PORT
      LAYER Metal2 ;
        RECT 196.120 0.000 196.520 0.400 ;
    END
  END Tile_X0Y0_FrameStrobe[14]
  PIN Tile_X0Y0_FrameStrobe[15]
    DIRECTION INPUT ;
    USE SIGNAL ;
    ANTENNAGATEAREA 0.180700 ;
    ANTENNADIFFAREA 2.015400 ;
    PORT
      LAYER Metal2 ;
        RECT 209.560 0.000 209.960 0.400 ;
    END
  END Tile_X0Y0_FrameStrobe[15]
  PIN Tile_X0Y0_FrameStrobe[16]
    DIRECTION INPUT ;
    USE SIGNAL ;
    ANTENNAGATEAREA 0.180700 ;
    ANTENNADIFFAREA 2.015400 ;
    PORT
      LAYER Metal2 ;
        RECT 223.000 0.000 223.400 0.400 ;
    END
  END Tile_X0Y0_FrameStrobe[16]
  PIN Tile_X0Y0_FrameStrobe[17]
    DIRECTION INPUT ;
    USE SIGNAL ;
    ANTENNAGATEAREA 0.180700 ;
    ANTENNADIFFAREA 2.015400 ;
    PORT
      LAYER Metal2 ;
        RECT 236.440 0.000 236.840 0.400 ;
    END
  END Tile_X0Y0_FrameStrobe[17]
  PIN Tile_X0Y0_FrameStrobe[18]
    DIRECTION INPUT ;
    USE SIGNAL ;
    ANTENNAGATEAREA 0.180700 ;
    ANTENNADIFFAREA 2.015400 ;
    PORT
      LAYER Metal2 ;
        RECT 249.880 0.000 250.280 0.400 ;
    END
  END Tile_X0Y0_FrameStrobe[18]
  PIN Tile_X0Y0_FrameStrobe[19]
    DIRECTION INPUT ;
    USE SIGNAL ;
    ANTENNAGATEAREA 0.180700 ;
    ANTENNADIFFAREA 2.015400 ;
    PORT
      LAYER Metal2 ;
        RECT 263.320 0.000 263.720 0.400 ;
    END
  END Tile_X0Y0_FrameStrobe[19]
  PIN Tile_X0Y0_FrameStrobe[1]
    DIRECTION INPUT ;
    USE SIGNAL ;
    ANTENNAGATEAREA 11.745500 ;
    ANTENNADIFFAREA 66.508202 ;
    PORT
      LAYER Metal2 ;
        RECT 21.400 0.000 21.800 0.400 ;
    END
  END Tile_X0Y0_FrameStrobe[1]
  PIN Tile_X0Y0_FrameStrobe[2]
    DIRECTION INPUT ;
    USE SIGNAL ;
    ANTENNAGATEAREA 11.745500 ;
    ANTENNADIFFAREA 66.508202 ;
    PORT
      LAYER Metal2 ;
        RECT 34.840 0.000 35.240 0.400 ;
    END
  END Tile_X0Y0_FrameStrobe[2]
  PIN Tile_X0Y0_FrameStrobe[3]
    DIRECTION INPUT ;
    USE SIGNAL ;
    ANTENNAGATEAREA 5.963100 ;
    ANTENNADIFFAREA 34.261799 ;
    PORT
      LAYER Metal2 ;
        RECT 48.280 0.000 48.680 0.400 ;
    END
  END Tile_X0Y0_FrameStrobe[3]
  PIN Tile_X0Y0_FrameStrobe[4]
    DIRECTION INPUT ;
    USE SIGNAL ;
    ANTENNAGATEAREA 0.180700 ;
    ANTENNADIFFAREA 2.015400 ;
    PORT
      LAYER Metal2 ;
        RECT 61.720 0.000 62.120 0.400 ;
    END
  END Tile_X0Y0_FrameStrobe[4]
  PIN Tile_X0Y0_FrameStrobe[5]
    DIRECTION INPUT ;
    USE SIGNAL ;
    ANTENNAGATEAREA 0.180700 ;
    ANTENNADIFFAREA 2.015400 ;
    PORT
      LAYER Metal2 ;
        RECT 75.160 0.000 75.560 0.400 ;
    END
  END Tile_X0Y0_FrameStrobe[5]
  PIN Tile_X0Y0_FrameStrobe[6]
    DIRECTION INPUT ;
    USE SIGNAL ;
    ANTENNAGATEAREA 0.180700 ;
    ANTENNADIFFAREA 2.015400 ;
    PORT
      LAYER Metal2 ;
        RECT 88.600 0.000 89.000 0.400 ;
    END
  END Tile_X0Y0_FrameStrobe[6]
  PIN Tile_X0Y0_FrameStrobe[7]
    DIRECTION INPUT ;
    USE SIGNAL ;
    ANTENNAGATEAREA 0.180700 ;
    ANTENNADIFFAREA 2.015400 ;
    PORT
      LAYER Metal2 ;
        RECT 102.040 0.000 102.440 0.400 ;
    END
  END Tile_X0Y0_FrameStrobe[7]
  PIN Tile_X0Y0_FrameStrobe[8]
    DIRECTION INPUT ;
    USE SIGNAL ;
    ANTENNAGATEAREA 0.180700 ;
    ANTENNADIFFAREA 2.015400 ;
    PORT
      LAYER Metal2 ;
        RECT 115.480 0.000 115.880 0.400 ;
    END
  END Tile_X0Y0_FrameStrobe[8]
  PIN Tile_X0Y0_FrameStrobe[9]
    DIRECTION INPUT ;
    USE SIGNAL ;
    ANTENNAGATEAREA 0.180700 ;
    ANTENNADIFFAREA 2.015400 ;
    PORT
      LAYER Metal2 ;
        RECT 128.920 0.000 129.320 0.400 ;
    END
  END Tile_X0Y0_FrameStrobe[9]
  PIN Tile_X0Y0_FrameStrobe_O[0]
    DIRECTION OUTPUT ;
    USE SIGNAL ;
    ANTENNADIFFAREA 2.724000 ;
    PORT
      LAYER Metal2 ;
        RECT 230.680 74.780 231.080 75.180 ;
    END
  END Tile_X0Y0_FrameStrobe_O[0]
  PIN Tile_X0Y0_FrameStrobe_O[10]
    DIRECTION OUTPUT ;
    USE SIGNAL ;
    ANTENNADIFFAREA 2.724000 ;
    PORT
      LAYER Metal2 ;
        RECT 249.880 74.780 250.280 75.180 ;
    END
  END Tile_X0Y0_FrameStrobe_O[10]
  PIN Tile_X0Y0_FrameStrobe_O[11]
    DIRECTION OUTPUT ;
    USE SIGNAL ;
    ANTENNADIFFAREA 2.724000 ;
    PORT
      LAYER Metal2 ;
        RECT 251.800 74.780 252.200 75.180 ;
    END
  END Tile_X0Y0_FrameStrobe_O[11]
  PIN Tile_X0Y0_FrameStrobe_O[12]
    DIRECTION OUTPUT ;
    USE SIGNAL ;
    ANTENNADIFFAREA 2.724000 ;
    PORT
      LAYER Metal2 ;
        RECT 253.720 74.780 254.120 75.180 ;
    END
  END Tile_X0Y0_FrameStrobe_O[12]
  PIN Tile_X0Y0_FrameStrobe_O[13]
    DIRECTION OUTPUT ;
    USE SIGNAL ;
    ANTENNADIFFAREA 2.724000 ;
    PORT
      LAYER Metal2 ;
        RECT 255.640 74.780 256.040 75.180 ;
    END
  END Tile_X0Y0_FrameStrobe_O[13]
  PIN Tile_X0Y0_FrameStrobe_O[14]
    DIRECTION OUTPUT ;
    USE SIGNAL ;
    ANTENNADIFFAREA 2.724000 ;
    PORT
      LAYER Metal2 ;
        RECT 257.560 74.780 257.960 75.180 ;
    END
  END Tile_X0Y0_FrameStrobe_O[14]
  PIN Tile_X0Y0_FrameStrobe_O[15]
    DIRECTION OUTPUT ;
    USE SIGNAL ;
    ANTENNADIFFAREA 2.724000 ;
    PORT
      LAYER Metal2 ;
        RECT 259.480 74.780 259.880 75.180 ;
    END
  END Tile_X0Y0_FrameStrobe_O[15]
  PIN Tile_X0Y0_FrameStrobe_O[16]
    DIRECTION OUTPUT ;
    USE SIGNAL ;
    ANTENNADIFFAREA 2.724000 ;
    PORT
      LAYER Metal2 ;
        RECT 261.400 74.780 261.800 75.180 ;
    END
  END Tile_X0Y0_FrameStrobe_O[16]
  PIN Tile_X0Y0_FrameStrobe_O[17]
    DIRECTION OUTPUT ;
    USE SIGNAL ;
    ANTENNADIFFAREA 2.724000 ;
    PORT
      LAYER Metal2 ;
        RECT 263.320 74.780 263.720 75.180 ;
    END
  END Tile_X0Y0_FrameStrobe_O[17]
  PIN Tile_X0Y0_FrameStrobe_O[18]
    DIRECTION OUTPUT ;
    USE SIGNAL ;
    ANTENNADIFFAREA 2.724000 ;
    PORT
      LAYER Metal2 ;
        RECT 265.240 74.780 265.640 75.180 ;
    END
  END Tile_X0Y0_FrameStrobe_O[18]
  PIN Tile_X0Y0_FrameStrobe_O[19]
    DIRECTION OUTPUT ;
    USE SIGNAL ;
    ANTENNADIFFAREA 2.724000 ;
    PORT
      LAYER Metal2 ;
        RECT 267.160 74.780 267.560 75.180 ;
    END
  END Tile_X0Y0_FrameStrobe_O[19]
  PIN Tile_X0Y0_FrameStrobe_O[1]
    DIRECTION OUTPUT ;
    USE SIGNAL ;
    ANTENNADIFFAREA 2.724000 ;
    PORT
      LAYER Metal2 ;
        RECT 232.600 74.780 233.000 75.180 ;
    END
  END Tile_X0Y0_FrameStrobe_O[1]
  PIN Tile_X0Y0_FrameStrobe_O[2]
    DIRECTION OUTPUT ;
    USE SIGNAL ;
    ANTENNADIFFAREA 2.724000 ;
    PORT
      LAYER Metal2 ;
        RECT 234.520 74.780 234.920 75.180 ;
    END
  END Tile_X0Y0_FrameStrobe_O[2]
  PIN Tile_X0Y0_FrameStrobe_O[3]
    DIRECTION OUTPUT ;
    USE SIGNAL ;
    ANTENNADIFFAREA 2.724000 ;
    PORT
      LAYER Metal2 ;
        RECT 236.440 74.780 236.840 75.180 ;
    END
  END Tile_X0Y0_FrameStrobe_O[3]
  PIN Tile_X0Y0_FrameStrobe_O[4]
    DIRECTION OUTPUT ;
    USE SIGNAL ;
    ANTENNADIFFAREA 2.724000 ;
    PORT
      LAYER Metal2 ;
        RECT 238.360 74.780 238.760 75.180 ;
    END
  END Tile_X0Y0_FrameStrobe_O[4]
  PIN Tile_X0Y0_FrameStrobe_O[5]
    DIRECTION OUTPUT ;
    USE SIGNAL ;
    ANTENNADIFFAREA 2.724000 ;
    PORT
      LAYER Metal2 ;
        RECT 240.280 74.780 240.680 75.180 ;
    END
  END Tile_X0Y0_FrameStrobe_O[5]
  PIN Tile_X0Y0_FrameStrobe_O[6]
    DIRECTION OUTPUT ;
    USE SIGNAL ;
    ANTENNADIFFAREA 2.724000 ;
    PORT
      LAYER Metal2 ;
        RECT 242.200 74.780 242.600 75.180 ;
    END
  END Tile_X0Y0_FrameStrobe_O[6]
  PIN Tile_X0Y0_FrameStrobe_O[7]
    DIRECTION OUTPUT ;
    USE SIGNAL ;
    ANTENNADIFFAREA 2.724000 ;
    PORT
      LAYER Metal2 ;
        RECT 244.120 74.780 244.520 75.180 ;
    END
  END Tile_X0Y0_FrameStrobe_O[7]
  PIN Tile_X0Y0_FrameStrobe_O[8]
    DIRECTION OUTPUT ;
    USE SIGNAL ;
    ANTENNADIFFAREA 2.724000 ;
    PORT
      LAYER Metal2 ;
        RECT 246.040 74.780 246.440 75.180 ;
    END
  END Tile_X0Y0_FrameStrobe_O[8]
  PIN Tile_X0Y0_FrameStrobe_O[9]
    DIRECTION OUTPUT ;
    USE SIGNAL ;
    ANTENNADIFFAREA 2.724000 ;
    PORT
      LAYER Metal2 ;
        RECT 247.960 74.780 248.360 75.180 ;
    END
  END Tile_X0Y0_FrameStrobe_O[9]
  PIN Tile_X0Y0_N1BEG[0]
    DIRECTION OUTPUT ;
    USE SIGNAL ;
    ANTENNADIFFAREA 2.724000 ;
    PORT
      LAYER Metal2 ;
        RECT 2.200 74.780 2.600 75.180 ;
    END
  END Tile_X0Y0_N1BEG[0]
  PIN Tile_X0Y0_N1BEG[1]
    DIRECTION OUTPUT ;
    USE SIGNAL ;
    ANTENNADIFFAREA 2.724000 ;
    PORT
      LAYER Metal2 ;
        RECT 4.120 74.780 4.520 75.180 ;
    END
  END Tile_X0Y0_N1BEG[1]
  PIN Tile_X0Y0_N1BEG[2]
    DIRECTION OUTPUT ;
    USE SIGNAL ;
    ANTENNADIFFAREA 2.724000 ;
    PORT
      LAYER Metal2 ;
        RECT 6.040 74.780 6.440 75.180 ;
    END
  END Tile_X0Y0_N1BEG[2]
  PIN Tile_X0Y0_N1BEG[3]
    DIRECTION OUTPUT ;
    USE SIGNAL ;
    ANTENNADIFFAREA 2.724000 ;
    PORT
      LAYER Metal2 ;
        RECT 7.960 74.780 8.360 75.180 ;
    END
  END Tile_X0Y0_N1BEG[3]
  PIN Tile_X0Y0_N2BEG[0]
    DIRECTION OUTPUT ;
    USE SIGNAL ;
    ANTENNADIFFAREA 2.724000 ;
    PORT
      LAYER Metal2 ;
        RECT 10.840 74.780 11.240 75.180 ;
    END
  END Tile_X0Y0_N2BEG[0]
  PIN Tile_X0Y0_N2BEG[1]
    DIRECTION OUTPUT ;
    USE SIGNAL ;
    ANTENNADIFFAREA 2.724000 ;
    PORT
      LAYER Metal2 ;
        RECT 12.760 74.780 13.160 75.180 ;
    END
  END Tile_X0Y0_N2BEG[1]
  PIN Tile_X0Y0_N2BEG[2]
    DIRECTION OUTPUT ;
    USE SIGNAL ;
    ANTENNADIFFAREA 2.724000 ;
    PORT
      LAYER Metal2 ;
        RECT 14.680 74.780 15.080 75.180 ;
    END
  END Tile_X0Y0_N2BEG[2]
  PIN Tile_X0Y0_N2BEG[3]
    DIRECTION OUTPUT ;
    USE SIGNAL ;
    ANTENNADIFFAREA 2.724000 ;
    PORT
      LAYER Metal2 ;
        RECT 16.600 74.780 17.000 75.180 ;
    END
  END Tile_X0Y0_N2BEG[3]
  PIN Tile_X0Y0_N2BEG[4]
    DIRECTION OUTPUT ;
    USE SIGNAL ;
    ANTENNADIFFAREA 2.724000 ;
    PORT
      LAYER Metal2 ;
        RECT 18.520 74.780 18.920 75.180 ;
    END
  END Tile_X0Y0_N2BEG[4]
  PIN Tile_X0Y0_N2BEG[5]
    DIRECTION OUTPUT ;
    USE SIGNAL ;
    ANTENNADIFFAREA 2.724000 ;
    PORT
      LAYER Metal2 ;
        RECT 20.440 74.780 20.840 75.180 ;
    END
  END Tile_X0Y0_N2BEG[5]
  PIN Tile_X0Y0_N2BEG[6]
    DIRECTION OUTPUT ;
    USE SIGNAL ;
    ANTENNADIFFAREA 2.724000 ;
    PORT
      LAYER Metal2 ;
        RECT 22.360 74.780 22.760 75.180 ;
    END
  END Tile_X0Y0_N2BEG[6]
  PIN Tile_X0Y0_N2BEG[7]
    DIRECTION OUTPUT ;
    USE SIGNAL ;
    ANTENNADIFFAREA 2.724000 ;
    PORT
      LAYER Metal2 ;
        RECT 24.280 74.780 24.680 75.180 ;
    END
  END Tile_X0Y0_N2BEG[7]
  PIN Tile_X0Y0_N2BEGb[0]
    DIRECTION OUTPUT ;
    USE SIGNAL ;
    ANTENNADIFFAREA 2.724000 ;
    PORT
      LAYER Metal2 ;
        RECT 27.160 74.780 27.560 75.180 ;
    END
  END Tile_X0Y0_N2BEGb[0]
  PIN Tile_X0Y0_N2BEGb[1]
    DIRECTION OUTPUT ;
    USE SIGNAL ;
    ANTENNADIFFAREA 2.724000 ;
    PORT
      LAYER Metal2 ;
        RECT 29.080 74.780 29.480 75.180 ;
    END
  END Tile_X0Y0_N2BEGb[1]
  PIN Tile_X0Y0_N2BEGb[2]
    DIRECTION OUTPUT ;
    USE SIGNAL ;
    ANTENNADIFFAREA 2.724000 ;
    PORT
      LAYER Metal2 ;
        RECT 31.000 74.780 31.400 75.180 ;
    END
  END Tile_X0Y0_N2BEGb[2]
  PIN Tile_X0Y0_N2BEGb[3]
    DIRECTION OUTPUT ;
    USE SIGNAL ;
    ANTENNADIFFAREA 2.724000 ;
    PORT
      LAYER Metal2 ;
        RECT 32.920 74.780 33.320 75.180 ;
    END
  END Tile_X0Y0_N2BEGb[3]
  PIN Tile_X0Y0_N2BEGb[4]
    DIRECTION OUTPUT ;
    USE SIGNAL ;
    ANTENNADIFFAREA 2.724000 ;
    PORT
      LAYER Metal2 ;
        RECT 34.840 74.780 35.240 75.180 ;
    END
  END Tile_X0Y0_N2BEGb[4]
  PIN Tile_X0Y0_N2BEGb[5]
    DIRECTION OUTPUT ;
    USE SIGNAL ;
    ANTENNADIFFAREA 2.724000 ;
    PORT
      LAYER Metal2 ;
        RECT 36.760 74.780 37.160 75.180 ;
    END
  END Tile_X0Y0_N2BEGb[5]
  PIN Tile_X0Y0_N2BEGb[6]
    DIRECTION OUTPUT ;
    USE SIGNAL ;
    ANTENNADIFFAREA 2.724000 ;
    PORT
      LAYER Metal2 ;
        RECT 38.680 74.780 39.080 75.180 ;
    END
  END Tile_X0Y0_N2BEGb[6]
  PIN Tile_X0Y0_N2BEGb[7]
    DIRECTION OUTPUT ;
    USE SIGNAL ;
    ANTENNADIFFAREA 2.724000 ;
    PORT
      LAYER Metal2 ;
        RECT 40.600 74.780 41.000 75.180 ;
    END
  END Tile_X0Y0_N2BEGb[7]
  PIN Tile_X0Y0_N4BEG[0]
    DIRECTION OUTPUT ;
    USE SIGNAL ;
    ANTENNADIFFAREA 2.724000 ;
    PORT
      LAYER Metal2 ;
        RECT 45.400 74.780 45.800 75.180 ;
    END
  END Tile_X0Y0_N4BEG[0]
  PIN Tile_X0Y0_N4BEG[10]
    DIRECTION OUTPUT ;
    USE SIGNAL ;
    ANTENNADIFFAREA 2.724000 ;
    PORT
      LAYER Metal2 ;
        RECT 64.600 74.780 65.000 75.180 ;
    END
  END Tile_X0Y0_N4BEG[10]
  PIN Tile_X0Y0_N4BEG[11]
    DIRECTION OUTPUT ;
    USE SIGNAL ;
    ANTENNADIFFAREA 2.724000 ;
    PORT
      LAYER Metal2 ;
        RECT 66.520 74.780 66.920 75.180 ;
    END
  END Tile_X0Y0_N4BEG[11]
  PIN Tile_X0Y0_N4BEG[12]
    DIRECTION OUTPUT ;
    USE SIGNAL ;
    ANTENNADIFFAREA 2.724000 ;
    PORT
      LAYER Metal2 ;
        RECT 68.440 74.780 68.840 75.180 ;
    END
  END Tile_X0Y0_N4BEG[12]
  PIN Tile_X0Y0_N4BEG[13]
    DIRECTION OUTPUT ;
    USE SIGNAL ;
    ANTENNADIFFAREA 2.724000 ;
    PORT
      LAYER Metal2 ;
        RECT 70.360 74.780 70.760 75.180 ;
    END
  END Tile_X0Y0_N4BEG[13]
  PIN Tile_X0Y0_N4BEG[14]
    DIRECTION OUTPUT ;
    USE SIGNAL ;
    ANTENNADIFFAREA 2.724000 ;
    PORT
      LAYER Metal2 ;
        RECT 72.280 74.780 72.680 75.180 ;
    END
  END Tile_X0Y0_N4BEG[14]
  PIN Tile_X0Y0_N4BEG[15]
    DIRECTION OUTPUT ;
    USE SIGNAL ;
    ANTENNADIFFAREA 2.724000 ;
    PORT
      LAYER Metal2 ;
        RECT 74.200 74.780 74.600 75.180 ;
    END
  END Tile_X0Y0_N4BEG[15]
  PIN Tile_X0Y0_N4BEG[1]
    DIRECTION OUTPUT ;
    USE SIGNAL ;
    ANTENNADIFFAREA 2.724000 ;
    PORT
      LAYER Metal2 ;
        RECT 47.320 74.780 47.720 75.180 ;
    END
  END Tile_X0Y0_N4BEG[1]
  PIN Tile_X0Y0_N4BEG[2]
    DIRECTION OUTPUT ;
    USE SIGNAL ;
    ANTENNADIFFAREA 2.724000 ;
    PORT
      LAYER Metal2 ;
        RECT 49.240 74.780 49.640 75.180 ;
    END
  END Tile_X0Y0_N4BEG[2]
  PIN Tile_X0Y0_N4BEG[3]
    DIRECTION OUTPUT ;
    USE SIGNAL ;
    ANTENNADIFFAREA 2.724000 ;
    PORT
      LAYER Metal2 ;
        RECT 51.160 74.780 51.560 75.180 ;
    END
  END Tile_X0Y0_N4BEG[3]
  PIN Tile_X0Y0_N4BEG[4]
    DIRECTION OUTPUT ;
    USE SIGNAL ;
    ANTENNADIFFAREA 2.724000 ;
    PORT
      LAYER Metal2 ;
        RECT 53.080 74.780 53.480 75.180 ;
    END
  END Tile_X0Y0_N4BEG[4]
  PIN Tile_X0Y0_N4BEG[5]
    DIRECTION OUTPUT ;
    USE SIGNAL ;
    ANTENNADIFFAREA 2.724000 ;
    PORT
      LAYER Metal2 ;
        RECT 55.000 74.780 55.400 75.180 ;
    END
  END Tile_X0Y0_N4BEG[5]
  PIN Tile_X0Y0_N4BEG[6]
    DIRECTION OUTPUT ;
    USE SIGNAL ;
    ANTENNADIFFAREA 2.724000 ;
    PORT
      LAYER Metal2 ;
        RECT 56.920 74.780 57.320 75.180 ;
    END
  END Tile_X0Y0_N4BEG[6]
  PIN Tile_X0Y0_N4BEG[7]
    DIRECTION OUTPUT ;
    USE SIGNAL ;
    ANTENNADIFFAREA 2.724000 ;
    PORT
      LAYER Metal2 ;
        RECT 58.840 74.780 59.240 75.180 ;
    END
  END Tile_X0Y0_N4BEG[7]
  PIN Tile_X0Y0_N4BEG[8]
    DIRECTION OUTPUT ;
    USE SIGNAL ;
    ANTENNADIFFAREA 2.724000 ;
    PORT
      LAYER Metal2 ;
        RECT 60.760 74.780 61.160 75.180 ;
    END
  END Tile_X0Y0_N4BEG[8]
  PIN Tile_X0Y0_N4BEG[9]
    DIRECTION OUTPUT ;
    USE SIGNAL ;
    ANTENNADIFFAREA 2.724000 ;
    PORT
      LAYER Metal2 ;
        RECT 62.680 74.780 63.080 75.180 ;
    END
  END Tile_X0Y0_N4BEG[9]
  PIN Tile_X0Y0_NN4BEG[0]
    DIRECTION OUTPUT ;
    USE SIGNAL ;
    ANTENNADIFFAREA 2.724000 ;
    PORT
      LAYER Metal2 ;
        RECT 79.960 74.780 80.360 75.180 ;
    END
  END Tile_X0Y0_NN4BEG[0]
  PIN Tile_X0Y0_NN4BEG[10]
    DIRECTION OUTPUT ;
    USE SIGNAL ;
    ANTENNADIFFAREA 2.724000 ;
    PORT
      LAYER Metal2 ;
        RECT 99.160 74.780 99.560 75.180 ;
    END
  END Tile_X0Y0_NN4BEG[10]
  PIN Tile_X0Y0_NN4BEG[11]
    DIRECTION OUTPUT ;
    USE SIGNAL ;
    ANTENNADIFFAREA 2.724000 ;
    PORT
      LAYER Metal2 ;
        RECT 101.080 74.780 101.480 75.180 ;
    END
  END Tile_X0Y0_NN4BEG[11]
  PIN Tile_X0Y0_NN4BEG[12]
    DIRECTION OUTPUT ;
    USE SIGNAL ;
    ANTENNADIFFAREA 2.724000 ;
    PORT
      LAYER Metal2 ;
        RECT 103.000 74.780 103.400 75.180 ;
    END
  END Tile_X0Y0_NN4BEG[12]
  PIN Tile_X0Y0_NN4BEG[13]
    DIRECTION OUTPUT ;
    USE SIGNAL ;
    ANTENNADIFFAREA 2.724000 ;
    PORT
      LAYER Metal2 ;
        RECT 104.920 74.780 105.320 75.180 ;
    END
  END Tile_X0Y0_NN4BEG[13]
  PIN Tile_X0Y0_NN4BEG[14]
    DIRECTION OUTPUT ;
    USE SIGNAL ;
    ANTENNADIFFAREA 2.724000 ;
    PORT
      LAYER Metal2 ;
        RECT 106.840 74.780 107.240 75.180 ;
    END
  END Tile_X0Y0_NN4BEG[14]
  PIN Tile_X0Y0_NN4BEG[15]
    DIRECTION OUTPUT ;
    USE SIGNAL ;
    ANTENNADIFFAREA 2.724000 ;
    PORT
      LAYER Metal2 ;
        RECT 108.760 74.780 109.160 75.180 ;
    END
  END Tile_X0Y0_NN4BEG[15]
  PIN Tile_X0Y0_NN4BEG[1]
    DIRECTION OUTPUT ;
    USE SIGNAL ;
    ANTENNADIFFAREA 2.724000 ;
    PORT
      LAYER Metal2 ;
        RECT 81.880 74.780 82.280 75.180 ;
    END
  END Tile_X0Y0_NN4BEG[1]
  PIN Tile_X0Y0_NN4BEG[2]
    DIRECTION OUTPUT ;
    USE SIGNAL ;
    ANTENNADIFFAREA 2.724000 ;
    PORT
      LAYER Metal2 ;
        RECT 83.800 74.780 84.200 75.180 ;
    END
  END Tile_X0Y0_NN4BEG[2]
  PIN Tile_X0Y0_NN4BEG[3]
    DIRECTION OUTPUT ;
    USE SIGNAL ;
    ANTENNADIFFAREA 2.724000 ;
    PORT
      LAYER Metal2 ;
        RECT 85.720 74.780 86.120 75.180 ;
    END
  END Tile_X0Y0_NN4BEG[3]
  PIN Tile_X0Y0_NN4BEG[4]
    DIRECTION OUTPUT ;
    USE SIGNAL ;
    ANTENNADIFFAREA 2.724000 ;
    PORT
      LAYER Metal2 ;
        RECT 87.640 74.780 88.040 75.180 ;
    END
  END Tile_X0Y0_NN4BEG[4]
  PIN Tile_X0Y0_NN4BEG[5]
    DIRECTION OUTPUT ;
    USE SIGNAL ;
    ANTENNADIFFAREA 2.724000 ;
    PORT
      LAYER Metal2 ;
        RECT 89.560 74.780 89.960 75.180 ;
    END
  END Tile_X0Y0_NN4BEG[5]
  PIN Tile_X0Y0_NN4BEG[6]
    DIRECTION OUTPUT ;
    USE SIGNAL ;
    ANTENNADIFFAREA 2.724000 ;
    PORT
      LAYER Metal2 ;
        RECT 91.480 74.780 91.880 75.180 ;
    END
  END Tile_X0Y0_NN4BEG[6]
  PIN Tile_X0Y0_NN4BEG[7]
    DIRECTION OUTPUT ;
    USE SIGNAL ;
    ANTENNADIFFAREA 2.724000 ;
    PORT
      LAYER Metal2 ;
        RECT 93.400 74.780 93.800 75.180 ;
    END
  END Tile_X0Y0_NN4BEG[7]
  PIN Tile_X0Y0_NN4BEG[8]
    DIRECTION OUTPUT ;
    USE SIGNAL ;
    ANTENNADIFFAREA 2.724000 ;
    PORT
      LAYER Metal2 ;
        RECT 95.320 74.780 95.720 75.180 ;
    END
  END Tile_X0Y0_NN4BEG[8]
  PIN Tile_X0Y0_NN4BEG[9]
    DIRECTION OUTPUT ;
    USE SIGNAL ;
    ANTENNADIFFAREA 2.724000 ;
    PORT
      LAYER Metal2 ;
        RECT 97.240 74.780 97.640 75.180 ;
    END
  END Tile_X0Y0_NN4BEG[9]
  PIN Tile_X0Y0_S1END[0]
    DIRECTION INPUT ;
    USE SIGNAL ;
    ANTENNAGATEAREA 0.607100 ;
    ANTENNADIFFAREA 6.046200 ;
    PORT
      LAYER Metal2 ;
        RECT 113.560 74.780 113.960 75.180 ;
    END
  END Tile_X0Y0_S1END[0]
  PIN Tile_X0Y0_S1END[1]
    DIRECTION INPUT ;
    USE SIGNAL ;
    ANTENNAGATEAREA 0.607100 ;
    ANTENNADIFFAREA 6.046200 ;
    PORT
      LAYER Metal2 ;
        RECT 115.480 74.780 115.880 75.180 ;
    END
  END Tile_X0Y0_S1END[1]
  PIN Tile_X0Y0_S1END[2]
    DIRECTION INPUT ;
    USE SIGNAL ;
    ANTENNAGATEAREA 0.607100 ;
    ANTENNADIFFAREA 6.046200 ;
    PORT
      LAYER Metal2 ;
        RECT 117.400 74.780 117.800 75.180 ;
    END
  END Tile_X0Y0_S1END[2]
  PIN Tile_X0Y0_S1END[3]
    DIRECTION INPUT ;
    USE SIGNAL ;
    ANTENNAGATEAREA 0.607100 ;
    ANTENNADIFFAREA 6.046200 ;
    PORT
      LAYER Metal2 ;
        RECT 119.320 74.780 119.720 75.180 ;
    END
  END Tile_X0Y0_S1END[3]
  PIN Tile_X0Y0_S2END[0]
    DIRECTION INPUT ;
    USE SIGNAL ;
    ANTENNAGATEAREA 0.639600 ;
    ANTENNADIFFAREA 6.046200 ;
    PORT
      LAYER Metal2 ;
        RECT 139.480 74.780 139.880 75.180 ;
    END
  END Tile_X0Y0_S2END[0]
  PIN Tile_X0Y0_S2END[1]
    DIRECTION INPUT ;
    USE SIGNAL ;
    ANTENNAGATEAREA 0.639600 ;
    ANTENNADIFFAREA 6.046200 ;
    PORT
      LAYER Metal2 ;
        RECT 141.400 74.780 141.800 75.180 ;
    END
  END Tile_X0Y0_S2END[1]
  PIN Tile_X0Y0_S2END[2]
    DIRECTION INPUT ;
    USE SIGNAL ;
    ANTENNAGATEAREA 0.639600 ;
    ANTENNADIFFAREA 6.046200 ;
    PORT
      LAYER Metal2 ;
        RECT 143.320 74.780 143.720 75.180 ;
    END
  END Tile_X0Y0_S2END[2]
  PIN Tile_X0Y0_S2END[3]
    DIRECTION INPUT ;
    USE SIGNAL ;
    ANTENNAGATEAREA 0.639600 ;
    ANTENNADIFFAREA 6.046200 ;
    PORT
      LAYER Metal2 ;
        RECT 145.240 74.780 145.640 75.180 ;
    END
  END Tile_X0Y0_S2END[3]
  PIN Tile_X0Y0_S2END[4]
    DIRECTION INPUT ;
    USE SIGNAL ;
    ANTENNAGATEAREA 0.639600 ;
    ANTENNADIFFAREA 6.046200 ;
    PORT
      LAYER Metal2 ;
        RECT 147.160 74.780 147.560 75.180 ;
    END
  END Tile_X0Y0_S2END[4]
  PIN Tile_X0Y0_S2END[5]
    DIRECTION INPUT ;
    USE SIGNAL ;
    ANTENNAGATEAREA 0.639600 ;
    ANTENNADIFFAREA 6.046200 ;
    PORT
      LAYER Metal2 ;
        RECT 149.080 74.780 149.480 75.180 ;
    END
  END Tile_X0Y0_S2END[5]
  PIN Tile_X0Y0_S2END[6]
    DIRECTION INPUT ;
    USE SIGNAL ;
    ANTENNAGATEAREA 0.639600 ;
    ANTENNADIFFAREA 6.046200 ;
    PORT
      LAYER Metal2 ;
        RECT 151.000 74.780 151.400 75.180 ;
    END
  END Tile_X0Y0_S2END[6]
  PIN Tile_X0Y0_S2END[7]
    DIRECTION INPUT ;
    USE SIGNAL ;
    ANTENNAGATEAREA 0.639600 ;
    ANTENNADIFFAREA 6.046200 ;
    PORT
      LAYER Metal2 ;
        RECT 152.920 74.780 153.320 75.180 ;
    END
  END Tile_X0Y0_S2END[7]
  PIN Tile_X0Y0_S2MID[0]
    DIRECTION INPUT ;
    USE SIGNAL ;
    ANTENNAGATEAREA 0.820300 ;
    ANTENNADIFFAREA 8.061600 ;
    PORT
      LAYER Metal2 ;
        RECT 122.200 74.780 122.600 75.180 ;
    END
  END Tile_X0Y0_S2MID[0]
  PIN Tile_X0Y0_S2MID[1]
    DIRECTION INPUT ;
    USE SIGNAL ;
    ANTENNAGATEAREA 0.820300 ;
    ANTENNADIFFAREA 8.061600 ;
    PORT
      LAYER Metal2 ;
        RECT 124.120 74.780 124.520 75.180 ;
    END
  END Tile_X0Y0_S2MID[1]
  PIN Tile_X0Y0_S2MID[2]
    DIRECTION INPUT ;
    USE SIGNAL ;
    ANTENNAGATEAREA 0.820300 ;
    ANTENNADIFFAREA 8.061600 ;
    PORT
      LAYER Metal2 ;
        RECT 126.040 74.780 126.440 75.180 ;
    END
  END Tile_X0Y0_S2MID[2]
  PIN Tile_X0Y0_S2MID[3]
    DIRECTION INPUT ;
    USE SIGNAL ;
    ANTENNAGATEAREA 0.820300 ;
    ANTENNADIFFAREA 8.061600 ;
    PORT
      LAYER Metal2 ;
        RECT 127.960 74.780 128.360 75.180 ;
    END
  END Tile_X0Y0_S2MID[3]
  PIN Tile_X0Y0_S2MID[4]
    DIRECTION INPUT ;
    USE SIGNAL ;
    ANTENNAGATEAREA 0.820300 ;
    ANTENNADIFFAREA 8.061600 ;
    PORT
      LAYER Metal2 ;
        RECT 129.880 74.780 130.280 75.180 ;
    END
  END Tile_X0Y0_S2MID[4]
  PIN Tile_X0Y0_S2MID[5]
    DIRECTION INPUT ;
    USE SIGNAL ;
    ANTENNAGATEAREA 0.820300 ;
    ANTENNADIFFAREA 8.061600 ;
    PORT
      LAYER Metal2 ;
        RECT 131.800 74.780 132.200 75.180 ;
    END
  END Tile_X0Y0_S2MID[5]
  PIN Tile_X0Y0_S2MID[6]
    DIRECTION INPUT ;
    USE SIGNAL ;
    ANTENNAGATEAREA 0.820300 ;
    ANTENNADIFFAREA 8.061600 ;
    PORT
      LAYER Metal2 ;
        RECT 133.720 74.780 134.120 75.180 ;
    END
  END Tile_X0Y0_S2MID[6]
  PIN Tile_X0Y0_S2MID[7]
    DIRECTION INPUT ;
    USE SIGNAL ;
    ANTENNAGATEAREA 0.820300 ;
    ANTENNADIFFAREA 8.061600 ;
    PORT
      LAYER Metal2 ;
        RECT 135.640 74.780 136.040 75.180 ;
    END
  END Tile_X0Y0_S2MID[7]
  PIN Tile_X0Y0_S4END[0]
    DIRECTION INPUT ;
    USE SIGNAL ;
    ANTENNAGATEAREA 0.852800 ;
    ANTENNADIFFAREA 8.061600 ;
    PORT
      LAYER Metal2 ;
        RECT 157.720 74.780 158.120 75.180 ;
    END
  END Tile_X0Y0_S4END[0]
  PIN Tile_X0Y0_S4END[10]
    DIRECTION INPUT ;
    USE SIGNAL ;
    ANTENNAGATEAREA 0.852800 ;
    ANTENNADIFFAREA 8.061600 ;
    PORT
      LAYER Metal2 ;
        RECT 176.920 74.780 177.320 75.180 ;
    END
  END Tile_X0Y0_S4END[10]
  PIN Tile_X0Y0_S4END[11]
    DIRECTION INPUT ;
    USE SIGNAL ;
    ANTENNAGATEAREA 0.852800 ;
    ANTENNADIFFAREA 8.061600 ;
    PORT
      LAYER Metal2 ;
        RECT 178.840 74.780 179.240 75.180 ;
    END
  END Tile_X0Y0_S4END[11]
  PIN Tile_X0Y0_S4END[12]
    DIRECTION INPUT ;
    USE SIGNAL ;
    ANTENNAGATEAREA 0.852800 ;
    ANTENNADIFFAREA 8.061600 ;
    PORT
      LAYER Metal2 ;
        RECT 180.760 74.780 181.160 75.180 ;
    END
  END Tile_X0Y0_S4END[12]
  PIN Tile_X0Y0_S4END[13]
    DIRECTION INPUT ;
    USE SIGNAL ;
    ANTENNAGATEAREA 0.852800 ;
    ANTENNADIFFAREA 8.061600 ;
    PORT
      LAYER Metal2 ;
        RECT 182.680 74.780 183.080 75.180 ;
    END
  END Tile_X0Y0_S4END[13]
  PIN Tile_X0Y0_S4END[14]
    DIRECTION INPUT ;
    USE SIGNAL ;
    ANTENNAGATEAREA 0.852800 ;
    ANTENNADIFFAREA 8.061600 ;
    PORT
      LAYER Metal2 ;
        RECT 184.600 74.780 185.000 75.180 ;
    END
  END Tile_X0Y0_S4END[14]
  PIN Tile_X0Y0_S4END[15]
    DIRECTION INPUT ;
    USE SIGNAL ;
    ANTENNAGATEAREA 0.852800 ;
    ANTENNADIFFAREA 8.061600 ;
    PORT
      LAYER Metal2 ;
        RECT 186.520 74.780 186.920 75.180 ;
    END
  END Tile_X0Y0_S4END[15]
  PIN Tile_X0Y0_S4END[1]
    DIRECTION INPUT ;
    USE SIGNAL ;
    ANTENNAGATEAREA 0.852800 ;
    ANTENNADIFFAREA 8.061600 ;
    PORT
      LAYER Metal2 ;
        RECT 159.640 74.780 160.040 75.180 ;
    END
  END Tile_X0Y0_S4END[1]
  PIN Tile_X0Y0_S4END[2]
    DIRECTION INPUT ;
    USE SIGNAL ;
    ANTENNAGATEAREA 0.852800 ;
    ANTENNADIFFAREA 8.061600 ;
    PORT
      LAYER Metal2 ;
        RECT 161.560 74.780 161.960 75.180 ;
    END
  END Tile_X0Y0_S4END[2]
  PIN Tile_X0Y0_S4END[3]
    DIRECTION INPUT ;
    USE SIGNAL ;
    ANTENNAGATEAREA 0.852800 ;
    ANTENNADIFFAREA 8.061600 ;
    PORT
      LAYER Metal2 ;
        RECT 163.480 74.780 163.880 75.180 ;
    END
  END Tile_X0Y0_S4END[3]
  PIN Tile_X0Y0_S4END[4]
    DIRECTION INPUT ;
    USE SIGNAL ;
    ANTENNAGATEAREA 0.852800 ;
    ANTENNADIFFAREA 8.061600 ;
    PORT
      LAYER Metal2 ;
        RECT 165.400 74.780 165.800 75.180 ;
    END
  END Tile_X0Y0_S4END[4]
  PIN Tile_X0Y0_S4END[5]
    DIRECTION INPUT ;
    USE SIGNAL ;
    ANTENNAGATEAREA 0.852800 ;
    ANTENNADIFFAREA 8.061600 ;
    PORT
      LAYER Metal2 ;
        RECT 167.320 74.780 167.720 75.180 ;
    END
  END Tile_X0Y0_S4END[5]
  PIN Tile_X0Y0_S4END[6]
    DIRECTION INPUT ;
    USE SIGNAL ;
    ANTENNAGATEAREA 0.852800 ;
    ANTENNADIFFAREA 8.061600 ;
    PORT
      LAYER Metal2 ;
        RECT 169.240 74.780 169.640 75.180 ;
    END
  END Tile_X0Y0_S4END[6]
  PIN Tile_X0Y0_S4END[7]
    DIRECTION INPUT ;
    USE SIGNAL ;
    ANTENNAGATEAREA 0.852800 ;
    ANTENNADIFFAREA 8.061600 ;
    PORT
      LAYER Metal2 ;
        RECT 171.160 74.780 171.560 75.180 ;
    END
  END Tile_X0Y0_S4END[7]
  PIN Tile_X0Y0_S4END[8]
    DIRECTION INPUT ;
    USE SIGNAL ;
    ANTENNAGATEAREA 0.852800 ;
    ANTENNADIFFAREA 8.061600 ;
    PORT
      LAYER Metal2 ;
        RECT 173.080 74.780 173.480 75.180 ;
    END
  END Tile_X0Y0_S4END[8]
  PIN Tile_X0Y0_S4END[9]
    DIRECTION INPUT ;
    USE SIGNAL ;
    ANTENNAGATEAREA 0.852800 ;
    ANTENNADIFFAREA 8.061600 ;
    PORT
      LAYER Metal2 ;
        RECT 175.000 74.780 175.400 75.180 ;
    END
  END Tile_X0Y0_S4END[9]
  PIN Tile_X0Y0_SS4END[0]
    DIRECTION INPUT ;
    USE SIGNAL ;
    ANTENNAGATEAREA 0.852800 ;
    ANTENNADIFFAREA 8.061600 ;
    PORT
      LAYER Metal2 ;
        RECT 192.280 74.780 192.680 75.180 ;
    END
  END Tile_X0Y0_SS4END[0]
  PIN Tile_X0Y0_SS4END[10]
    DIRECTION INPUT ;
    USE SIGNAL ;
    ANTENNAGATEAREA 0.852800 ;
    ANTENNADIFFAREA 8.061600 ;
    PORT
      LAYER Metal2 ;
        RECT 211.480 74.780 211.880 75.180 ;
    END
  END Tile_X0Y0_SS4END[10]
  PIN Tile_X0Y0_SS4END[11]
    DIRECTION INPUT ;
    USE SIGNAL ;
    ANTENNAGATEAREA 0.852800 ;
    ANTENNADIFFAREA 8.061600 ;
    PORT
      LAYER Metal2 ;
        RECT 213.400 74.780 213.800 75.180 ;
    END
  END Tile_X0Y0_SS4END[11]
  PIN Tile_X0Y0_SS4END[12]
    DIRECTION INPUT ;
    USE SIGNAL ;
    ANTENNAGATEAREA 0.852800 ;
    ANTENNADIFFAREA 8.061600 ;
    PORT
      LAYER Metal2 ;
        RECT 215.320 74.780 215.720 75.180 ;
    END
  END Tile_X0Y0_SS4END[12]
  PIN Tile_X0Y0_SS4END[13]
    DIRECTION INPUT ;
    USE SIGNAL ;
    ANTENNAGATEAREA 0.852800 ;
    ANTENNADIFFAREA 8.061600 ;
    PORT
      LAYER Metal2 ;
        RECT 217.240 74.780 217.640 75.180 ;
    END
  END Tile_X0Y0_SS4END[13]
  PIN Tile_X0Y0_SS4END[14]
    DIRECTION INPUT ;
    USE SIGNAL ;
    ANTENNAGATEAREA 0.852800 ;
    ANTENNADIFFAREA 8.061600 ;
    PORT
      LAYER Metal2 ;
        RECT 219.160 74.780 219.560 75.180 ;
    END
  END Tile_X0Y0_SS4END[14]
  PIN Tile_X0Y0_SS4END[15]
    DIRECTION INPUT ;
    USE SIGNAL ;
    ANTENNAGATEAREA 0.852800 ;
    ANTENNADIFFAREA 8.061600 ;
    PORT
      LAYER Metal2 ;
        RECT 221.080 74.780 221.480 75.180 ;
    END
  END Tile_X0Y0_SS4END[15]
  PIN Tile_X0Y0_SS4END[1]
    DIRECTION INPUT ;
    USE SIGNAL ;
    ANTENNAGATEAREA 0.852800 ;
    ANTENNADIFFAREA 8.061600 ;
    PORT
      LAYER Metal2 ;
        RECT 194.200 74.780 194.600 75.180 ;
    END
  END Tile_X0Y0_SS4END[1]
  PIN Tile_X0Y0_SS4END[2]
    DIRECTION INPUT ;
    USE SIGNAL ;
    ANTENNAGATEAREA 0.852800 ;
    ANTENNADIFFAREA 8.061600 ;
    PORT
      LAYER Metal2 ;
        RECT 196.120 74.780 196.520 75.180 ;
    END
  END Tile_X0Y0_SS4END[2]
  PIN Tile_X0Y0_SS4END[3]
    DIRECTION INPUT ;
    USE SIGNAL ;
    ANTENNAGATEAREA 0.852800 ;
    ANTENNADIFFAREA 8.061600 ;
    PORT
      LAYER Metal2 ;
        RECT 198.040 74.780 198.440 75.180 ;
    END
  END Tile_X0Y0_SS4END[3]
  PIN Tile_X0Y0_SS4END[4]
    DIRECTION INPUT ;
    USE SIGNAL ;
    ANTENNAGATEAREA 0.852800 ;
    ANTENNADIFFAREA 8.061600 ;
    PORT
      LAYER Metal2 ;
        RECT 199.960 74.780 200.360 75.180 ;
    END
  END Tile_X0Y0_SS4END[4]
  PIN Tile_X0Y0_SS4END[5]
    DIRECTION INPUT ;
    USE SIGNAL ;
    ANTENNAGATEAREA 0.852800 ;
    ANTENNADIFFAREA 8.061600 ;
    PORT
      LAYER Metal2 ;
        RECT 201.880 74.780 202.280 75.180 ;
    END
  END Tile_X0Y0_SS4END[5]
  PIN Tile_X0Y0_SS4END[6]
    DIRECTION INPUT ;
    USE SIGNAL ;
    ANTENNAGATEAREA 0.852800 ;
    ANTENNADIFFAREA 8.061600 ;
    PORT
      LAYER Metal2 ;
        RECT 203.800 74.780 204.200 75.180 ;
    END
  END Tile_X0Y0_SS4END[6]
  PIN Tile_X0Y0_SS4END[7]
    DIRECTION INPUT ;
    USE SIGNAL ;
    ANTENNAGATEAREA 0.852800 ;
    ANTENNADIFFAREA 8.061600 ;
    PORT
      LAYER Metal2 ;
        RECT 205.720 74.780 206.120 75.180 ;
    END
  END Tile_X0Y0_SS4END[7]
  PIN Tile_X0Y0_SS4END[8]
    DIRECTION INPUT ;
    USE SIGNAL ;
    ANTENNAGATEAREA 0.852800 ;
    ANTENNADIFFAREA 8.061600 ;
    PORT
      LAYER Metal2 ;
        RECT 207.640 74.780 208.040 75.180 ;
    END
  END Tile_X0Y0_SS4END[8]
  PIN Tile_X0Y0_SS4END[9]
    DIRECTION INPUT ;
    USE SIGNAL ;
    ANTENNAGATEAREA 0.852800 ;
    ANTENNADIFFAREA 8.061600 ;
    PORT
      LAYER Metal2 ;
        RECT 209.560 74.780 209.960 75.180 ;
    END
  END Tile_X0Y0_SS4END[9]
  PIN Tile_X0Y0_UserCLK
    DIRECTION INPUT ;
    USE SIGNAL ;
    ANTENNAGATEAREA 20.250099 ;
    ANTENNADIFFAREA 169.293594 ;
    PORT
      LAYER Metal3 ;
        RECT 0.000 1.900 0.400 2.300 ;
    END
  END Tile_X0Y0_UserCLK
  PIN Tile_X1Y0_Co
    DIRECTION OUTPUT ;
    USE SIGNAL ;
    ANTENNADIFFAREA 2.314600 ;
    PORT
      LAYER Metal2 ;
        RECT 496.120 74.780 496.520 75.180 ;
    END
  END Tile_X1Y0_Co
  PIN Tile_X1Y0_FrameStrobe[0]
    DIRECTION INPUT ;
    USE SIGNAL ;
    ANTENNAGATEAREA 11.745500 ;
    ANTENNADIFFAREA 66.508202 ;
    PORT
      LAYER Metal2 ;
        RECT 278.200 0.000 278.600 0.400 ;
    END
  END Tile_X1Y0_FrameStrobe[0]
  PIN Tile_X1Y0_FrameStrobe[10]
    DIRECTION INPUT ;
    USE SIGNAL ;
    ANTENNAGATEAREA 0.180700 ;
    ANTENNADIFFAREA 2.015400 ;
    PORT
      LAYER Metal2 ;
        RECT 412.600 0.000 413.000 0.400 ;
    END
  END Tile_X1Y0_FrameStrobe[10]
  PIN Tile_X1Y0_FrameStrobe[11]
    DIRECTION INPUT ;
    USE SIGNAL ;
    ANTENNAGATEAREA 0.180700 ;
    ANTENNADIFFAREA 2.015400 ;
    PORT
      LAYER Metal2 ;
        RECT 426.040 0.000 426.440 0.400 ;
    END
  END Tile_X1Y0_FrameStrobe[11]
  PIN Tile_X1Y0_FrameStrobe[12]
    DIRECTION INPUT ;
    USE SIGNAL ;
    ANTENNAGATEAREA 0.180700 ;
    ANTENNADIFFAREA 2.015400 ;
    PORT
      LAYER Metal2 ;
        RECT 439.480 0.000 439.880 0.400 ;
    END
  END Tile_X1Y0_FrameStrobe[12]
  PIN Tile_X1Y0_FrameStrobe[13]
    DIRECTION INPUT ;
    USE SIGNAL ;
    ANTENNAGATEAREA 0.180700 ;
    ANTENNADIFFAREA 2.015400 ;
    PORT
      LAYER Metal2 ;
        RECT 452.920 0.000 453.320 0.400 ;
    END
  END Tile_X1Y0_FrameStrobe[13]
  PIN Tile_X1Y0_FrameStrobe[14]
    DIRECTION INPUT ;
    USE SIGNAL ;
    ANTENNAGATEAREA 0.180700 ;
    ANTENNADIFFAREA 2.015400 ;
    PORT
      LAYER Metal2 ;
        RECT 466.360 0.000 466.760 0.400 ;
    END
  END Tile_X1Y0_FrameStrobe[14]
  PIN Tile_X1Y0_FrameStrobe[15]
    DIRECTION INPUT ;
    USE SIGNAL ;
    ANTENNAGATEAREA 0.180700 ;
    ANTENNADIFFAREA 2.015400 ;
    PORT
      LAYER Metal2 ;
        RECT 479.800 0.000 480.200 0.400 ;
    END
  END Tile_X1Y0_FrameStrobe[15]
  PIN Tile_X1Y0_FrameStrobe[16]
    DIRECTION INPUT ;
    USE SIGNAL ;
    ANTENNAGATEAREA 0.180700 ;
    ANTENNADIFFAREA 2.015400 ;
    PORT
      LAYER Metal2 ;
        RECT 493.240 0.000 493.640 0.400 ;
    END
  END Tile_X1Y0_FrameStrobe[16]
  PIN Tile_X1Y0_FrameStrobe[17]
    DIRECTION INPUT ;
    USE SIGNAL ;
    ANTENNAGATEAREA 0.180700 ;
    ANTENNADIFFAREA 2.015400 ;
    PORT
      LAYER Metal2 ;
        RECT 506.680 0.000 507.080 0.400 ;
    END
  END Tile_X1Y0_FrameStrobe[17]
  PIN Tile_X1Y0_FrameStrobe[18]
    DIRECTION INPUT ;
    USE SIGNAL ;
    ANTENNAGATEAREA 0.180700 ;
    ANTENNADIFFAREA 2.015400 ;
    PORT
      LAYER Metal2 ;
        RECT 520.120 0.000 520.520 0.400 ;
    END
  END Tile_X1Y0_FrameStrobe[18]
  PIN Tile_X1Y0_FrameStrobe[19]
    DIRECTION INPUT ;
    USE SIGNAL ;
    ANTENNAGATEAREA 0.180700 ;
    ANTENNADIFFAREA 2.015400 ;
    PORT
      LAYER Metal2 ;
        RECT 533.560 0.000 533.960 0.400 ;
    END
  END Tile_X1Y0_FrameStrobe[19]
  PIN Tile_X1Y0_FrameStrobe[1]
    DIRECTION INPUT ;
    USE SIGNAL ;
    ANTENNAGATEAREA 11.745500 ;
    ANTENNADIFFAREA 66.508202 ;
    PORT
      LAYER Metal2 ;
        RECT 291.640 0.000 292.040 0.400 ;
    END
  END Tile_X1Y0_FrameStrobe[1]
  PIN Tile_X1Y0_FrameStrobe[2]
    DIRECTION INPUT ;
    USE SIGNAL ;
    ANTENNAGATEAREA 11.745500 ;
    ANTENNADIFFAREA 66.508202 ;
    PORT
      LAYER Metal2 ;
        RECT 305.080 0.000 305.480 0.400 ;
    END
  END Tile_X1Y0_FrameStrobe[2]
  PIN Tile_X1Y0_FrameStrobe[3]
    DIRECTION INPUT ;
    USE SIGNAL ;
    ANTENNAGATEAREA 5.963100 ;
    ANTENNADIFFAREA 34.261799 ;
    PORT
      LAYER Metal2 ;
        RECT 318.520 0.000 318.920 0.400 ;
    END
  END Tile_X1Y0_FrameStrobe[3]
  PIN Tile_X1Y0_FrameStrobe[4]
    DIRECTION INPUT ;
    USE SIGNAL ;
    ANTENNAGATEAREA 0.180700 ;
    ANTENNADIFFAREA 2.015400 ;
    PORT
      LAYER Metal2 ;
        RECT 331.960 0.000 332.360 0.400 ;
    END
  END Tile_X1Y0_FrameStrobe[4]
  PIN Tile_X1Y0_FrameStrobe[5]
    DIRECTION INPUT ;
    USE SIGNAL ;
    ANTENNAGATEAREA 0.180700 ;
    ANTENNADIFFAREA 2.015400 ;
    PORT
      LAYER Metal2 ;
        RECT 345.400 0.000 345.800 0.400 ;
    END
  END Tile_X1Y0_FrameStrobe[5]
  PIN Tile_X1Y0_FrameStrobe[6]
    DIRECTION INPUT ;
    USE SIGNAL ;
    ANTENNAGATEAREA 0.180700 ;
    ANTENNADIFFAREA 2.015400 ;
    PORT
      LAYER Metal2 ;
        RECT 358.840 0.000 359.240 0.400 ;
    END
  END Tile_X1Y0_FrameStrobe[6]
  PIN Tile_X1Y0_FrameStrobe[7]
    DIRECTION INPUT ;
    USE SIGNAL ;
    ANTENNAGATEAREA 0.180700 ;
    ANTENNADIFFAREA 2.015400 ;
    PORT
      LAYER Metal2 ;
        RECT 372.280 0.000 372.680 0.400 ;
    END
  END Tile_X1Y0_FrameStrobe[7]
  PIN Tile_X1Y0_FrameStrobe[8]
    DIRECTION INPUT ;
    USE SIGNAL ;
    ANTENNAGATEAREA 0.180700 ;
    ANTENNADIFFAREA 2.015400 ;
    PORT
      LAYER Metal2 ;
        RECT 385.720 0.000 386.120 0.400 ;
    END
  END Tile_X1Y0_FrameStrobe[8]
  PIN Tile_X1Y0_FrameStrobe[9]
    DIRECTION INPUT ;
    USE SIGNAL ;
    ANTENNAGATEAREA 0.180700 ;
    ANTENNADIFFAREA 2.015400 ;
    PORT
      LAYER Metal2 ;
        RECT 399.160 0.000 399.560 0.400 ;
    END
  END Tile_X1Y0_FrameStrobe[9]
  PIN Tile_X1Y0_FrameStrobe_O[0]
    DIRECTION OUTPUT ;
    USE SIGNAL ;
    ANTENNADIFFAREA 2.724000 ;
    PORT
      LAYER Metal2 ;
        RECT 500.920 74.780 501.320 75.180 ;
    END
  END Tile_X1Y0_FrameStrobe_O[0]
  PIN Tile_X1Y0_FrameStrobe_O[10]
    DIRECTION OUTPUT ;
    USE SIGNAL ;
    ANTENNADIFFAREA 2.724000 ;
    PORT
      LAYER Metal2 ;
        RECT 520.120 74.780 520.520 75.180 ;
    END
  END Tile_X1Y0_FrameStrobe_O[10]
  PIN Tile_X1Y0_FrameStrobe_O[11]
    DIRECTION OUTPUT ;
    USE SIGNAL ;
    ANTENNADIFFAREA 2.724000 ;
    PORT
      LAYER Metal2 ;
        RECT 522.040 74.780 522.440 75.180 ;
    END
  END Tile_X1Y0_FrameStrobe_O[11]
  PIN Tile_X1Y0_FrameStrobe_O[12]
    DIRECTION OUTPUT ;
    USE SIGNAL ;
    ANTENNADIFFAREA 2.724000 ;
    PORT
      LAYER Metal2 ;
        RECT 523.960 74.780 524.360 75.180 ;
    END
  END Tile_X1Y0_FrameStrobe_O[12]
  PIN Tile_X1Y0_FrameStrobe_O[13]
    DIRECTION OUTPUT ;
    USE SIGNAL ;
    ANTENNADIFFAREA 2.724000 ;
    PORT
      LAYER Metal2 ;
        RECT 525.880 74.780 526.280 75.180 ;
    END
  END Tile_X1Y0_FrameStrobe_O[13]
  PIN Tile_X1Y0_FrameStrobe_O[14]
    DIRECTION OUTPUT ;
    USE SIGNAL ;
    ANTENNADIFFAREA 2.724000 ;
    PORT
      LAYER Metal2 ;
        RECT 527.800 74.780 528.200 75.180 ;
    END
  END Tile_X1Y0_FrameStrobe_O[14]
  PIN Tile_X1Y0_FrameStrobe_O[15]
    DIRECTION OUTPUT ;
    USE SIGNAL ;
    ANTENNADIFFAREA 2.724000 ;
    PORT
      LAYER Metal2 ;
        RECT 529.720 74.780 530.120 75.180 ;
    END
  END Tile_X1Y0_FrameStrobe_O[15]
  PIN Tile_X1Y0_FrameStrobe_O[16]
    DIRECTION OUTPUT ;
    USE SIGNAL ;
    ANTENNADIFFAREA 2.724000 ;
    PORT
      LAYER Metal2 ;
        RECT 531.640 74.780 532.040 75.180 ;
    END
  END Tile_X1Y0_FrameStrobe_O[16]
  PIN Tile_X1Y0_FrameStrobe_O[17]
    DIRECTION OUTPUT ;
    USE SIGNAL ;
    ANTENNADIFFAREA 2.724000 ;
    PORT
      LAYER Metal2 ;
        RECT 533.560 74.780 533.960 75.180 ;
    END
  END Tile_X1Y0_FrameStrobe_O[17]
  PIN Tile_X1Y0_FrameStrobe_O[18]
    DIRECTION OUTPUT ;
    USE SIGNAL ;
    ANTENNADIFFAREA 2.724000 ;
    PORT
      LAYER Metal2 ;
        RECT 535.480 74.780 535.880 75.180 ;
    END
  END Tile_X1Y0_FrameStrobe_O[18]
  PIN Tile_X1Y0_FrameStrobe_O[19]
    DIRECTION OUTPUT ;
    USE SIGNAL ;
    ANTENNADIFFAREA 2.724000 ;
    PORT
      LAYER Metal2 ;
        RECT 537.400 74.780 537.800 75.180 ;
    END
  END Tile_X1Y0_FrameStrobe_O[19]
  PIN Tile_X1Y0_FrameStrobe_O[1]
    DIRECTION OUTPUT ;
    USE SIGNAL ;
    ANTENNADIFFAREA 2.724000 ;
    PORT
      LAYER Metal2 ;
        RECT 502.840 74.780 503.240 75.180 ;
    END
  END Tile_X1Y0_FrameStrobe_O[1]
  PIN Tile_X1Y0_FrameStrobe_O[2]
    DIRECTION OUTPUT ;
    USE SIGNAL ;
    ANTENNADIFFAREA 2.724000 ;
    PORT
      LAYER Metal2 ;
        RECT 504.760 74.780 505.160 75.180 ;
    END
  END Tile_X1Y0_FrameStrobe_O[2]
  PIN Tile_X1Y0_FrameStrobe_O[3]
    DIRECTION OUTPUT ;
    USE SIGNAL ;
    ANTENNADIFFAREA 2.724000 ;
    PORT
      LAYER Metal2 ;
        RECT 506.680 74.780 507.080 75.180 ;
    END
  END Tile_X1Y0_FrameStrobe_O[3]
  PIN Tile_X1Y0_FrameStrobe_O[4]
    DIRECTION OUTPUT ;
    USE SIGNAL ;
    ANTENNADIFFAREA 2.724000 ;
    PORT
      LAYER Metal2 ;
        RECT 508.600 74.780 509.000 75.180 ;
    END
  END Tile_X1Y0_FrameStrobe_O[4]
  PIN Tile_X1Y0_FrameStrobe_O[5]
    DIRECTION OUTPUT ;
    USE SIGNAL ;
    ANTENNADIFFAREA 2.724000 ;
    PORT
      LAYER Metal2 ;
        RECT 510.520 74.780 510.920 75.180 ;
    END
  END Tile_X1Y0_FrameStrobe_O[5]
  PIN Tile_X1Y0_FrameStrobe_O[6]
    DIRECTION OUTPUT ;
    USE SIGNAL ;
    ANTENNADIFFAREA 2.724000 ;
    PORT
      LAYER Metal2 ;
        RECT 512.440 74.780 512.840 75.180 ;
    END
  END Tile_X1Y0_FrameStrobe_O[6]
  PIN Tile_X1Y0_FrameStrobe_O[7]
    DIRECTION OUTPUT ;
    USE SIGNAL ;
    ANTENNADIFFAREA 2.724000 ;
    PORT
      LAYER Metal2 ;
        RECT 514.360 74.780 514.760 75.180 ;
    END
  END Tile_X1Y0_FrameStrobe_O[7]
  PIN Tile_X1Y0_FrameStrobe_O[8]
    DIRECTION OUTPUT ;
    USE SIGNAL ;
    ANTENNADIFFAREA 2.724000 ;
    PORT
      LAYER Metal2 ;
        RECT 516.280 74.780 516.680 75.180 ;
    END
  END Tile_X1Y0_FrameStrobe_O[8]
  PIN Tile_X1Y0_FrameStrobe_O[9]
    DIRECTION OUTPUT ;
    USE SIGNAL ;
    ANTENNADIFFAREA 2.724000 ;
    PORT
      LAYER Metal2 ;
        RECT 518.200 74.780 518.600 75.180 ;
    END
  END Tile_X1Y0_FrameStrobe_O[9]
  PIN Tile_X1Y0_N1BEG[0]
    DIRECTION OUTPUT ;
    USE SIGNAL ;
    ANTENNADIFFAREA 2.724000 ;
    PORT
      LAYER Metal2 ;
        RECT 272.440 74.780 272.840 75.180 ;
    END
  END Tile_X1Y0_N1BEG[0]
  PIN Tile_X1Y0_N1BEG[1]
    DIRECTION OUTPUT ;
    USE SIGNAL ;
    ANTENNADIFFAREA 2.724000 ;
    PORT
      LAYER Metal2 ;
        RECT 274.360 74.780 274.760 75.180 ;
    END
  END Tile_X1Y0_N1BEG[1]
  PIN Tile_X1Y0_N1BEG[2]
    DIRECTION OUTPUT ;
    USE SIGNAL ;
    ANTENNADIFFAREA 2.724000 ;
    PORT
      LAYER Metal2 ;
        RECT 276.280 74.780 276.680 75.180 ;
    END
  END Tile_X1Y0_N1BEG[2]
  PIN Tile_X1Y0_N1BEG[3]
    DIRECTION OUTPUT ;
    USE SIGNAL ;
    ANTENNADIFFAREA 2.724000 ;
    PORT
      LAYER Metal2 ;
        RECT 278.200 74.780 278.600 75.180 ;
    END
  END Tile_X1Y0_N1BEG[3]
  PIN Tile_X1Y0_N2BEG[0]
    DIRECTION OUTPUT ;
    USE SIGNAL ;
    ANTENNADIFFAREA 2.724000 ;
    PORT
      LAYER Metal2 ;
        RECT 281.080 74.780 281.480 75.180 ;
    END
  END Tile_X1Y0_N2BEG[0]
  PIN Tile_X1Y0_N2BEG[1]
    DIRECTION OUTPUT ;
    USE SIGNAL ;
    ANTENNADIFFAREA 2.724000 ;
    PORT
      LAYER Metal2 ;
        RECT 283.000 74.780 283.400 75.180 ;
    END
  END Tile_X1Y0_N2BEG[1]
  PIN Tile_X1Y0_N2BEG[2]
    DIRECTION OUTPUT ;
    USE SIGNAL ;
    ANTENNADIFFAREA 2.724000 ;
    PORT
      LAYER Metal2 ;
        RECT 284.920 74.780 285.320 75.180 ;
    END
  END Tile_X1Y0_N2BEG[2]
  PIN Tile_X1Y0_N2BEG[3]
    DIRECTION OUTPUT ;
    USE SIGNAL ;
    ANTENNADIFFAREA 2.724000 ;
    PORT
      LAYER Metal2 ;
        RECT 286.840 74.780 287.240 75.180 ;
    END
  END Tile_X1Y0_N2BEG[3]
  PIN Tile_X1Y0_N2BEG[4]
    DIRECTION OUTPUT ;
    USE SIGNAL ;
    ANTENNADIFFAREA 2.724000 ;
    PORT
      LAYER Metal2 ;
        RECT 288.760 74.780 289.160 75.180 ;
    END
  END Tile_X1Y0_N2BEG[4]
  PIN Tile_X1Y0_N2BEG[5]
    DIRECTION OUTPUT ;
    USE SIGNAL ;
    ANTENNADIFFAREA 2.724000 ;
    PORT
      LAYER Metal2 ;
        RECT 290.680 74.780 291.080 75.180 ;
    END
  END Tile_X1Y0_N2BEG[5]
  PIN Tile_X1Y0_N2BEG[6]
    DIRECTION OUTPUT ;
    USE SIGNAL ;
    ANTENNADIFFAREA 2.724000 ;
    PORT
      LAYER Metal2 ;
        RECT 292.600 74.780 293.000 75.180 ;
    END
  END Tile_X1Y0_N2BEG[6]
  PIN Tile_X1Y0_N2BEG[7]
    DIRECTION OUTPUT ;
    USE SIGNAL ;
    ANTENNADIFFAREA 2.724000 ;
    PORT
      LAYER Metal2 ;
        RECT 294.520 74.780 294.920 75.180 ;
    END
  END Tile_X1Y0_N2BEG[7]
  PIN Tile_X1Y0_N2BEGb[0]
    DIRECTION OUTPUT ;
    USE SIGNAL ;
    ANTENNADIFFAREA 2.724000 ;
    PORT
      LAYER Metal2 ;
        RECT 297.400 74.780 297.800 75.180 ;
    END
  END Tile_X1Y0_N2BEGb[0]
  PIN Tile_X1Y0_N2BEGb[1]
    DIRECTION OUTPUT ;
    USE SIGNAL ;
    ANTENNADIFFAREA 2.724000 ;
    PORT
      LAYER Metal2 ;
        RECT 299.320 74.780 299.720 75.180 ;
    END
  END Tile_X1Y0_N2BEGb[1]
  PIN Tile_X1Y0_N2BEGb[2]
    DIRECTION OUTPUT ;
    USE SIGNAL ;
    ANTENNADIFFAREA 2.724000 ;
    PORT
      LAYER Metal2 ;
        RECT 301.240 74.780 301.640 75.180 ;
    END
  END Tile_X1Y0_N2BEGb[2]
  PIN Tile_X1Y0_N2BEGb[3]
    DIRECTION OUTPUT ;
    USE SIGNAL ;
    ANTENNADIFFAREA 2.724000 ;
    PORT
      LAYER Metal2 ;
        RECT 303.160 74.780 303.560 75.180 ;
    END
  END Tile_X1Y0_N2BEGb[3]
  PIN Tile_X1Y0_N2BEGb[4]
    DIRECTION OUTPUT ;
    USE SIGNAL ;
    ANTENNADIFFAREA 2.724000 ;
    PORT
      LAYER Metal2 ;
        RECT 305.080 74.780 305.480 75.180 ;
    END
  END Tile_X1Y0_N2BEGb[4]
  PIN Tile_X1Y0_N2BEGb[5]
    DIRECTION OUTPUT ;
    USE SIGNAL ;
    ANTENNADIFFAREA 2.724000 ;
    PORT
      LAYER Metal2 ;
        RECT 307.000 74.780 307.400 75.180 ;
    END
  END Tile_X1Y0_N2BEGb[5]
  PIN Tile_X1Y0_N2BEGb[6]
    DIRECTION OUTPUT ;
    USE SIGNAL ;
    ANTENNADIFFAREA 2.724000 ;
    PORT
      LAYER Metal2 ;
        RECT 308.920 74.780 309.320 75.180 ;
    END
  END Tile_X1Y0_N2BEGb[6]
  PIN Tile_X1Y0_N2BEGb[7]
    DIRECTION OUTPUT ;
    USE SIGNAL ;
    ANTENNADIFFAREA 2.724000 ;
    PORT
      LAYER Metal2 ;
        RECT 310.840 74.780 311.240 75.180 ;
    END
  END Tile_X1Y0_N2BEGb[7]
  PIN Tile_X1Y0_N4BEG[0]
    DIRECTION OUTPUT ;
    USE SIGNAL ;
    ANTENNADIFFAREA 2.724000 ;
    PORT
      LAYER Metal2 ;
        RECT 315.640 74.780 316.040 75.180 ;
    END
  END Tile_X1Y0_N4BEG[0]
  PIN Tile_X1Y0_N4BEG[10]
    DIRECTION OUTPUT ;
    USE SIGNAL ;
    ANTENNADIFFAREA 2.724000 ;
    PORT
      LAYER Metal2 ;
        RECT 334.840 74.780 335.240 75.180 ;
    END
  END Tile_X1Y0_N4BEG[10]
  PIN Tile_X1Y0_N4BEG[11]
    DIRECTION OUTPUT ;
    USE SIGNAL ;
    ANTENNADIFFAREA 2.724000 ;
    PORT
      LAYER Metal2 ;
        RECT 336.760 74.780 337.160 75.180 ;
    END
  END Tile_X1Y0_N4BEG[11]
  PIN Tile_X1Y0_N4BEG[12]
    DIRECTION OUTPUT ;
    USE SIGNAL ;
    ANTENNADIFFAREA 2.724000 ;
    PORT
      LAYER Metal2 ;
        RECT 338.680 74.780 339.080 75.180 ;
    END
  END Tile_X1Y0_N4BEG[12]
  PIN Tile_X1Y0_N4BEG[13]
    DIRECTION OUTPUT ;
    USE SIGNAL ;
    ANTENNADIFFAREA 2.724000 ;
    PORT
      LAYER Metal2 ;
        RECT 340.600 74.780 341.000 75.180 ;
    END
  END Tile_X1Y0_N4BEG[13]
  PIN Tile_X1Y0_N4BEG[14]
    DIRECTION OUTPUT ;
    USE SIGNAL ;
    ANTENNADIFFAREA 2.724000 ;
    PORT
      LAYER Metal2 ;
        RECT 342.520 74.780 342.920 75.180 ;
    END
  END Tile_X1Y0_N4BEG[14]
  PIN Tile_X1Y0_N4BEG[15]
    DIRECTION OUTPUT ;
    USE SIGNAL ;
    ANTENNADIFFAREA 2.724000 ;
    PORT
      LAYER Metal2 ;
        RECT 344.440 74.780 344.840 75.180 ;
    END
  END Tile_X1Y0_N4BEG[15]
  PIN Tile_X1Y0_N4BEG[1]
    DIRECTION OUTPUT ;
    USE SIGNAL ;
    ANTENNADIFFAREA 2.724000 ;
    PORT
      LAYER Metal2 ;
        RECT 317.560 74.780 317.960 75.180 ;
    END
  END Tile_X1Y0_N4BEG[1]
  PIN Tile_X1Y0_N4BEG[2]
    DIRECTION OUTPUT ;
    USE SIGNAL ;
    ANTENNADIFFAREA 2.724000 ;
    PORT
      LAYER Metal2 ;
        RECT 319.480 74.780 319.880 75.180 ;
    END
  END Tile_X1Y0_N4BEG[2]
  PIN Tile_X1Y0_N4BEG[3]
    DIRECTION OUTPUT ;
    USE SIGNAL ;
    ANTENNADIFFAREA 2.724000 ;
    PORT
      LAYER Metal2 ;
        RECT 321.400 74.780 321.800 75.180 ;
    END
  END Tile_X1Y0_N4BEG[3]
  PIN Tile_X1Y0_N4BEG[4]
    DIRECTION OUTPUT ;
    USE SIGNAL ;
    ANTENNADIFFAREA 2.724000 ;
    PORT
      LAYER Metal2 ;
        RECT 323.320 74.780 323.720 75.180 ;
    END
  END Tile_X1Y0_N4BEG[4]
  PIN Tile_X1Y0_N4BEG[5]
    DIRECTION OUTPUT ;
    USE SIGNAL ;
    ANTENNADIFFAREA 2.724000 ;
    PORT
      LAYER Metal2 ;
        RECT 325.240 74.780 325.640 75.180 ;
    END
  END Tile_X1Y0_N4BEG[5]
  PIN Tile_X1Y0_N4BEG[6]
    DIRECTION OUTPUT ;
    USE SIGNAL ;
    ANTENNADIFFAREA 2.724000 ;
    PORT
      LAYER Metal2 ;
        RECT 327.160 74.780 327.560 75.180 ;
    END
  END Tile_X1Y0_N4BEG[6]
  PIN Tile_X1Y0_N4BEG[7]
    DIRECTION OUTPUT ;
    USE SIGNAL ;
    ANTENNADIFFAREA 2.724000 ;
    PORT
      LAYER Metal2 ;
        RECT 329.080 74.780 329.480 75.180 ;
    END
  END Tile_X1Y0_N4BEG[7]
  PIN Tile_X1Y0_N4BEG[8]
    DIRECTION OUTPUT ;
    USE SIGNAL ;
    ANTENNADIFFAREA 2.724000 ;
    PORT
      LAYER Metal2 ;
        RECT 331.000 74.780 331.400 75.180 ;
    END
  END Tile_X1Y0_N4BEG[8]
  PIN Tile_X1Y0_N4BEG[9]
    DIRECTION OUTPUT ;
    USE SIGNAL ;
    ANTENNADIFFAREA 2.724000 ;
    PORT
      LAYER Metal2 ;
        RECT 332.920 74.780 333.320 75.180 ;
    END
  END Tile_X1Y0_N4BEG[9]
  PIN Tile_X1Y0_NN4BEG[0]
    DIRECTION OUTPUT ;
    USE SIGNAL ;
    ANTENNADIFFAREA 2.724000 ;
    PORT
      LAYER Metal2 ;
        RECT 350.200 74.780 350.600 75.180 ;
    END
  END Tile_X1Y0_NN4BEG[0]
  PIN Tile_X1Y0_NN4BEG[10]
    DIRECTION OUTPUT ;
    USE SIGNAL ;
    ANTENNADIFFAREA 2.724000 ;
    PORT
      LAYER Metal2 ;
        RECT 369.400 74.780 369.800 75.180 ;
    END
  END Tile_X1Y0_NN4BEG[10]
  PIN Tile_X1Y0_NN4BEG[11]
    DIRECTION OUTPUT ;
    USE SIGNAL ;
    ANTENNADIFFAREA 2.724000 ;
    PORT
      LAYER Metal2 ;
        RECT 371.320 74.780 371.720 75.180 ;
    END
  END Tile_X1Y0_NN4BEG[11]
  PIN Tile_X1Y0_NN4BEG[12]
    DIRECTION OUTPUT ;
    USE SIGNAL ;
    ANTENNADIFFAREA 2.724000 ;
    PORT
      LAYER Metal2 ;
        RECT 373.240 74.780 373.640 75.180 ;
    END
  END Tile_X1Y0_NN4BEG[12]
  PIN Tile_X1Y0_NN4BEG[13]
    DIRECTION OUTPUT ;
    USE SIGNAL ;
    ANTENNADIFFAREA 2.724000 ;
    PORT
      LAYER Metal2 ;
        RECT 375.160 74.780 375.560 75.180 ;
    END
  END Tile_X1Y0_NN4BEG[13]
  PIN Tile_X1Y0_NN4BEG[14]
    DIRECTION OUTPUT ;
    USE SIGNAL ;
    ANTENNADIFFAREA 2.724000 ;
    PORT
      LAYER Metal2 ;
        RECT 377.080 74.780 377.480 75.180 ;
    END
  END Tile_X1Y0_NN4BEG[14]
  PIN Tile_X1Y0_NN4BEG[15]
    DIRECTION OUTPUT ;
    USE SIGNAL ;
    ANTENNADIFFAREA 2.724000 ;
    PORT
      LAYER Metal2 ;
        RECT 379.000 74.780 379.400 75.180 ;
    END
  END Tile_X1Y0_NN4BEG[15]
  PIN Tile_X1Y0_NN4BEG[1]
    DIRECTION OUTPUT ;
    USE SIGNAL ;
    ANTENNADIFFAREA 2.724000 ;
    PORT
      LAYER Metal2 ;
        RECT 352.120 74.780 352.520 75.180 ;
    END
  END Tile_X1Y0_NN4BEG[1]
  PIN Tile_X1Y0_NN4BEG[2]
    DIRECTION OUTPUT ;
    USE SIGNAL ;
    ANTENNADIFFAREA 2.724000 ;
    PORT
      LAYER Metal2 ;
        RECT 354.040 74.780 354.440 75.180 ;
    END
  END Tile_X1Y0_NN4BEG[2]
  PIN Tile_X1Y0_NN4BEG[3]
    DIRECTION OUTPUT ;
    USE SIGNAL ;
    ANTENNADIFFAREA 2.724000 ;
    PORT
      LAYER Metal2 ;
        RECT 355.960 74.780 356.360 75.180 ;
    END
  END Tile_X1Y0_NN4BEG[3]
  PIN Tile_X1Y0_NN4BEG[4]
    DIRECTION OUTPUT ;
    USE SIGNAL ;
    ANTENNADIFFAREA 2.724000 ;
    PORT
      LAYER Metal2 ;
        RECT 357.880 74.780 358.280 75.180 ;
    END
  END Tile_X1Y0_NN4BEG[4]
  PIN Tile_X1Y0_NN4BEG[5]
    DIRECTION OUTPUT ;
    USE SIGNAL ;
    ANTENNADIFFAREA 2.724000 ;
    PORT
      LAYER Metal2 ;
        RECT 359.800 74.780 360.200 75.180 ;
    END
  END Tile_X1Y0_NN4BEG[5]
  PIN Tile_X1Y0_NN4BEG[6]
    DIRECTION OUTPUT ;
    USE SIGNAL ;
    ANTENNADIFFAREA 2.724000 ;
    PORT
      LAYER Metal2 ;
        RECT 361.720 74.780 362.120 75.180 ;
    END
  END Tile_X1Y0_NN4BEG[6]
  PIN Tile_X1Y0_NN4BEG[7]
    DIRECTION OUTPUT ;
    USE SIGNAL ;
    ANTENNADIFFAREA 2.724000 ;
    PORT
      LAYER Metal2 ;
        RECT 363.640 74.780 364.040 75.180 ;
    END
  END Tile_X1Y0_NN4BEG[7]
  PIN Tile_X1Y0_NN4BEG[8]
    DIRECTION OUTPUT ;
    USE SIGNAL ;
    ANTENNADIFFAREA 2.724000 ;
    PORT
      LAYER Metal2 ;
        RECT 365.560 74.780 365.960 75.180 ;
    END
  END Tile_X1Y0_NN4BEG[8]
  PIN Tile_X1Y0_NN4BEG[9]
    DIRECTION OUTPUT ;
    USE SIGNAL ;
    ANTENNADIFFAREA 2.724000 ;
    PORT
      LAYER Metal2 ;
        RECT 367.480 74.780 367.880 75.180 ;
    END
  END Tile_X1Y0_NN4BEG[9]
  PIN Tile_X1Y0_S1END[0]
    DIRECTION INPUT ;
    USE SIGNAL ;
    ANTENNAGATEAREA 0.607100 ;
    ANTENNADIFFAREA 6.046200 ;
    PORT
      LAYER Metal2 ;
        RECT 383.800 74.780 384.200 75.180 ;
    END
  END Tile_X1Y0_S1END[0]
  PIN Tile_X1Y0_S1END[1]
    DIRECTION INPUT ;
    USE SIGNAL ;
    ANTENNAGATEAREA 0.607100 ;
    ANTENNADIFFAREA 6.046200 ;
    PORT
      LAYER Metal2 ;
        RECT 385.720 74.780 386.120 75.180 ;
    END
  END Tile_X1Y0_S1END[1]
  PIN Tile_X1Y0_S1END[2]
    DIRECTION INPUT ;
    USE SIGNAL ;
    ANTENNAGATEAREA 0.607100 ;
    ANTENNADIFFAREA 6.046200 ;
    PORT
      LAYER Metal2 ;
        RECT 387.640 74.780 388.040 75.180 ;
    END
  END Tile_X1Y0_S1END[2]
  PIN Tile_X1Y0_S1END[3]
    DIRECTION INPUT ;
    USE SIGNAL ;
    ANTENNAGATEAREA 0.607100 ;
    ANTENNADIFFAREA 6.046200 ;
    PORT
      LAYER Metal2 ;
        RECT 389.560 74.780 389.960 75.180 ;
    END
  END Tile_X1Y0_S1END[3]
  PIN Tile_X1Y0_S2END[0]
    DIRECTION INPUT ;
    USE SIGNAL ;
    ANTENNAGATEAREA 0.639600 ;
    ANTENNADIFFAREA 6.046200 ;
    PORT
      LAYER Metal2 ;
        RECT 409.720 74.780 410.120 75.180 ;
    END
  END Tile_X1Y0_S2END[0]
  PIN Tile_X1Y0_S2END[1]
    DIRECTION INPUT ;
    USE SIGNAL ;
    ANTENNAGATEAREA 0.639600 ;
    ANTENNADIFFAREA 6.046200 ;
    PORT
      LAYER Metal2 ;
        RECT 411.640 74.780 412.040 75.180 ;
    END
  END Tile_X1Y0_S2END[1]
  PIN Tile_X1Y0_S2END[2]
    DIRECTION INPUT ;
    USE SIGNAL ;
    ANTENNAGATEAREA 0.639600 ;
    ANTENNADIFFAREA 6.046200 ;
    PORT
      LAYER Metal2 ;
        RECT 413.560 74.780 413.960 75.180 ;
    END
  END Tile_X1Y0_S2END[2]
  PIN Tile_X1Y0_S2END[3]
    DIRECTION INPUT ;
    USE SIGNAL ;
    ANTENNAGATEAREA 0.639600 ;
    ANTENNADIFFAREA 6.046200 ;
    PORT
      LAYER Metal2 ;
        RECT 415.480 74.780 415.880 75.180 ;
    END
  END Tile_X1Y0_S2END[3]
  PIN Tile_X1Y0_S2END[4]
    DIRECTION INPUT ;
    USE SIGNAL ;
    ANTENNAGATEAREA 0.639600 ;
    ANTENNADIFFAREA 6.046200 ;
    PORT
      LAYER Metal2 ;
        RECT 417.400 74.780 417.800 75.180 ;
    END
  END Tile_X1Y0_S2END[4]
  PIN Tile_X1Y0_S2END[5]
    DIRECTION INPUT ;
    USE SIGNAL ;
    ANTENNAGATEAREA 0.639600 ;
    ANTENNADIFFAREA 6.046200 ;
    PORT
      LAYER Metal2 ;
        RECT 419.320 74.780 419.720 75.180 ;
    END
  END Tile_X1Y0_S2END[5]
  PIN Tile_X1Y0_S2END[6]
    DIRECTION INPUT ;
    USE SIGNAL ;
    ANTENNAGATEAREA 0.639600 ;
    ANTENNADIFFAREA 6.046200 ;
    PORT
      LAYER Metal2 ;
        RECT 421.240 74.780 421.640 75.180 ;
    END
  END Tile_X1Y0_S2END[6]
  PIN Tile_X1Y0_S2END[7]
    DIRECTION INPUT ;
    USE SIGNAL ;
    ANTENNAGATEAREA 0.639600 ;
    ANTENNADIFFAREA 6.046200 ;
    PORT
      LAYER Metal2 ;
        RECT 423.160 74.780 423.560 75.180 ;
    END
  END Tile_X1Y0_S2END[7]
  PIN Tile_X1Y0_S2MID[0]
    DIRECTION INPUT ;
    USE SIGNAL ;
    ANTENNAGATEAREA 0.820300 ;
    ANTENNADIFFAREA 8.061600 ;
    PORT
      LAYER Metal2 ;
        RECT 392.440 74.780 392.840 75.180 ;
    END
  END Tile_X1Y0_S2MID[0]
  PIN Tile_X1Y0_S2MID[1]
    DIRECTION INPUT ;
    USE SIGNAL ;
    ANTENNAGATEAREA 0.820300 ;
    ANTENNADIFFAREA 8.061600 ;
    PORT
      LAYER Metal2 ;
        RECT 394.360 74.780 394.760 75.180 ;
    END
  END Tile_X1Y0_S2MID[1]
  PIN Tile_X1Y0_S2MID[2]
    DIRECTION INPUT ;
    USE SIGNAL ;
    ANTENNAGATEAREA 0.820300 ;
    ANTENNADIFFAREA 8.061600 ;
    PORT
      LAYER Metal2 ;
        RECT 396.280 74.780 396.680 75.180 ;
    END
  END Tile_X1Y0_S2MID[2]
  PIN Tile_X1Y0_S2MID[3]
    DIRECTION INPUT ;
    USE SIGNAL ;
    ANTENNAGATEAREA 0.820300 ;
    ANTENNADIFFAREA 8.061600 ;
    PORT
      LAYER Metal2 ;
        RECT 398.200 74.780 398.600 75.180 ;
    END
  END Tile_X1Y0_S2MID[3]
  PIN Tile_X1Y0_S2MID[4]
    DIRECTION INPUT ;
    USE SIGNAL ;
    ANTENNAGATEAREA 0.820300 ;
    ANTENNADIFFAREA 8.061600 ;
    PORT
      LAYER Metal2 ;
        RECT 400.120 74.780 400.520 75.180 ;
    END
  END Tile_X1Y0_S2MID[4]
  PIN Tile_X1Y0_S2MID[5]
    DIRECTION INPUT ;
    USE SIGNAL ;
    ANTENNAGATEAREA 0.820300 ;
    ANTENNADIFFAREA 8.061600 ;
    PORT
      LAYER Metal2 ;
        RECT 402.040 74.780 402.440 75.180 ;
    END
  END Tile_X1Y0_S2MID[5]
  PIN Tile_X1Y0_S2MID[6]
    DIRECTION INPUT ;
    USE SIGNAL ;
    ANTENNAGATEAREA 0.820300 ;
    ANTENNADIFFAREA 8.061600 ;
    PORT
      LAYER Metal2 ;
        RECT 403.960 74.780 404.360 75.180 ;
    END
  END Tile_X1Y0_S2MID[6]
  PIN Tile_X1Y0_S2MID[7]
    DIRECTION INPUT ;
    USE SIGNAL ;
    ANTENNAGATEAREA 0.820300 ;
    ANTENNADIFFAREA 8.061600 ;
    PORT
      LAYER Metal2 ;
        RECT 405.880 74.780 406.280 75.180 ;
    END
  END Tile_X1Y0_S2MID[7]
  PIN Tile_X1Y0_S4END[0]
    DIRECTION INPUT ;
    USE SIGNAL ;
    ANTENNAGATEAREA 0.852800 ;
    ANTENNADIFFAREA 8.061600 ;
    PORT
      LAYER Metal2 ;
        RECT 427.960 74.780 428.360 75.180 ;
    END
  END Tile_X1Y0_S4END[0]
  PIN Tile_X1Y0_S4END[10]
    DIRECTION INPUT ;
    USE SIGNAL ;
    ANTENNAGATEAREA 0.852800 ;
    ANTENNADIFFAREA 8.061600 ;
    PORT
      LAYER Metal2 ;
        RECT 447.160 74.780 447.560 75.180 ;
    END
  END Tile_X1Y0_S4END[10]
  PIN Tile_X1Y0_S4END[11]
    DIRECTION INPUT ;
    USE SIGNAL ;
    ANTENNAGATEAREA 0.852800 ;
    ANTENNADIFFAREA 8.061600 ;
    PORT
      LAYER Metal2 ;
        RECT 449.080 74.780 449.480 75.180 ;
    END
  END Tile_X1Y0_S4END[11]
  PIN Tile_X1Y0_S4END[12]
    DIRECTION INPUT ;
    USE SIGNAL ;
    ANTENNAGATEAREA 0.852800 ;
    ANTENNADIFFAREA 8.061600 ;
    PORT
      LAYER Metal2 ;
        RECT 451.000 74.780 451.400 75.180 ;
    END
  END Tile_X1Y0_S4END[12]
  PIN Tile_X1Y0_S4END[13]
    DIRECTION INPUT ;
    USE SIGNAL ;
    ANTENNAGATEAREA 0.852800 ;
    ANTENNADIFFAREA 8.061600 ;
    PORT
      LAYER Metal2 ;
        RECT 452.920 74.780 453.320 75.180 ;
    END
  END Tile_X1Y0_S4END[13]
  PIN Tile_X1Y0_S4END[14]
    DIRECTION INPUT ;
    USE SIGNAL ;
    ANTENNAGATEAREA 0.852800 ;
    ANTENNADIFFAREA 8.061600 ;
    PORT
      LAYER Metal2 ;
        RECT 454.840 74.780 455.240 75.180 ;
    END
  END Tile_X1Y0_S4END[14]
  PIN Tile_X1Y0_S4END[15]
    DIRECTION INPUT ;
    USE SIGNAL ;
    ANTENNAGATEAREA 0.852800 ;
    ANTENNADIFFAREA 8.061600 ;
    PORT
      LAYER Metal2 ;
        RECT 456.760 74.780 457.160 75.180 ;
    END
  END Tile_X1Y0_S4END[15]
  PIN Tile_X1Y0_S4END[1]
    DIRECTION INPUT ;
    USE SIGNAL ;
    ANTENNAGATEAREA 0.852800 ;
    ANTENNADIFFAREA 8.061600 ;
    PORT
      LAYER Metal2 ;
        RECT 429.880 74.780 430.280 75.180 ;
    END
  END Tile_X1Y0_S4END[1]
  PIN Tile_X1Y0_S4END[2]
    DIRECTION INPUT ;
    USE SIGNAL ;
    ANTENNAGATEAREA 0.852800 ;
    ANTENNADIFFAREA 8.061600 ;
    PORT
      LAYER Metal2 ;
        RECT 431.800 74.780 432.200 75.180 ;
    END
  END Tile_X1Y0_S4END[2]
  PIN Tile_X1Y0_S4END[3]
    DIRECTION INPUT ;
    USE SIGNAL ;
    ANTENNAGATEAREA 0.852800 ;
    ANTENNADIFFAREA 8.061600 ;
    PORT
      LAYER Metal2 ;
        RECT 433.720 74.780 434.120 75.180 ;
    END
  END Tile_X1Y0_S4END[3]
  PIN Tile_X1Y0_S4END[4]
    DIRECTION INPUT ;
    USE SIGNAL ;
    ANTENNAGATEAREA 0.852800 ;
    ANTENNADIFFAREA 8.061600 ;
    PORT
      LAYER Metal2 ;
        RECT 435.640 74.780 436.040 75.180 ;
    END
  END Tile_X1Y0_S4END[4]
  PIN Tile_X1Y0_S4END[5]
    DIRECTION INPUT ;
    USE SIGNAL ;
    ANTENNAGATEAREA 0.852800 ;
    ANTENNADIFFAREA 8.061600 ;
    PORT
      LAYER Metal2 ;
        RECT 437.560 74.780 437.960 75.180 ;
    END
  END Tile_X1Y0_S4END[5]
  PIN Tile_X1Y0_S4END[6]
    DIRECTION INPUT ;
    USE SIGNAL ;
    ANTENNAGATEAREA 0.852800 ;
    ANTENNADIFFAREA 8.061600 ;
    PORT
      LAYER Metal2 ;
        RECT 439.480 74.780 439.880 75.180 ;
    END
  END Tile_X1Y0_S4END[6]
  PIN Tile_X1Y0_S4END[7]
    DIRECTION INPUT ;
    USE SIGNAL ;
    ANTENNAGATEAREA 0.852800 ;
    ANTENNADIFFAREA 8.061600 ;
    PORT
      LAYER Metal2 ;
        RECT 441.400 74.780 441.800 75.180 ;
    END
  END Tile_X1Y0_S4END[7]
  PIN Tile_X1Y0_S4END[8]
    DIRECTION INPUT ;
    USE SIGNAL ;
    ANTENNAGATEAREA 0.852800 ;
    ANTENNADIFFAREA 8.061600 ;
    PORT
      LAYER Metal2 ;
        RECT 443.320 74.780 443.720 75.180 ;
    END
  END Tile_X1Y0_S4END[8]
  PIN Tile_X1Y0_S4END[9]
    DIRECTION INPUT ;
    USE SIGNAL ;
    ANTENNAGATEAREA 0.852800 ;
    ANTENNADIFFAREA 8.061600 ;
    PORT
      LAYER Metal2 ;
        RECT 445.240 74.780 445.640 75.180 ;
    END
  END Tile_X1Y0_S4END[9]
  PIN Tile_X1Y0_SS4END[0]
    DIRECTION INPUT ;
    USE SIGNAL ;
    ANTENNAGATEAREA 0.852800 ;
    ANTENNADIFFAREA 8.061600 ;
    PORT
      LAYER Metal2 ;
        RECT 462.520 74.780 462.920 75.180 ;
    END
  END Tile_X1Y0_SS4END[0]
  PIN Tile_X1Y0_SS4END[10]
    DIRECTION INPUT ;
    USE SIGNAL ;
    ANTENNAGATEAREA 0.852800 ;
    ANTENNADIFFAREA 8.061600 ;
    PORT
      LAYER Metal2 ;
        RECT 481.720 74.780 482.120 75.180 ;
    END
  END Tile_X1Y0_SS4END[10]
  PIN Tile_X1Y0_SS4END[11]
    DIRECTION INPUT ;
    USE SIGNAL ;
    ANTENNAGATEAREA 0.852800 ;
    ANTENNADIFFAREA 8.061600 ;
    PORT
      LAYER Metal2 ;
        RECT 483.640 74.780 484.040 75.180 ;
    END
  END Tile_X1Y0_SS4END[11]
  PIN Tile_X1Y0_SS4END[12]
    DIRECTION INPUT ;
    USE SIGNAL ;
    ANTENNAGATEAREA 0.852800 ;
    ANTENNADIFFAREA 8.061600 ;
    PORT
      LAYER Metal2 ;
        RECT 485.560 74.780 485.960 75.180 ;
    END
  END Tile_X1Y0_SS4END[12]
  PIN Tile_X1Y0_SS4END[13]
    DIRECTION INPUT ;
    USE SIGNAL ;
    ANTENNAGATEAREA 0.852800 ;
    ANTENNADIFFAREA 8.061600 ;
    PORT
      LAYER Metal2 ;
        RECT 487.480 74.780 487.880 75.180 ;
    END
  END Tile_X1Y0_SS4END[13]
  PIN Tile_X1Y0_SS4END[14]
    DIRECTION INPUT ;
    USE SIGNAL ;
    ANTENNAGATEAREA 0.852800 ;
    ANTENNADIFFAREA 8.061600 ;
    PORT
      LAYER Metal2 ;
        RECT 489.400 74.780 489.800 75.180 ;
    END
  END Tile_X1Y0_SS4END[14]
  PIN Tile_X1Y0_SS4END[15]
    DIRECTION INPUT ;
    USE SIGNAL ;
    ANTENNAGATEAREA 0.852800 ;
    ANTENNADIFFAREA 8.061600 ;
    PORT
      LAYER Metal2 ;
        RECT 491.320 74.780 491.720 75.180 ;
    END
  END Tile_X1Y0_SS4END[15]
  PIN Tile_X1Y0_SS4END[1]
    DIRECTION INPUT ;
    USE SIGNAL ;
    ANTENNAGATEAREA 0.852800 ;
    ANTENNADIFFAREA 8.061600 ;
    PORT
      LAYER Metal2 ;
        RECT 464.440 74.780 464.840 75.180 ;
    END
  END Tile_X1Y0_SS4END[1]
  PIN Tile_X1Y0_SS4END[2]
    DIRECTION INPUT ;
    USE SIGNAL ;
    ANTENNAGATEAREA 0.852800 ;
    ANTENNADIFFAREA 8.061600 ;
    PORT
      LAYER Metal2 ;
        RECT 466.360 74.780 466.760 75.180 ;
    END
  END Tile_X1Y0_SS4END[2]
  PIN Tile_X1Y0_SS4END[3]
    DIRECTION INPUT ;
    USE SIGNAL ;
    ANTENNAGATEAREA 0.852800 ;
    ANTENNADIFFAREA 8.061600 ;
    PORT
      LAYER Metal2 ;
        RECT 468.280 74.780 468.680 75.180 ;
    END
  END Tile_X1Y0_SS4END[3]
  PIN Tile_X1Y0_SS4END[4]
    DIRECTION INPUT ;
    USE SIGNAL ;
    ANTENNAGATEAREA 0.852800 ;
    ANTENNADIFFAREA 8.061600 ;
    PORT
      LAYER Metal2 ;
        RECT 470.200 74.780 470.600 75.180 ;
    END
  END Tile_X1Y0_SS4END[4]
  PIN Tile_X1Y0_SS4END[5]
    DIRECTION INPUT ;
    USE SIGNAL ;
    ANTENNAGATEAREA 0.852800 ;
    ANTENNADIFFAREA 8.061600 ;
    PORT
      LAYER Metal2 ;
        RECT 472.120 74.780 472.520 75.180 ;
    END
  END Tile_X1Y0_SS4END[5]
  PIN Tile_X1Y0_SS4END[6]
    DIRECTION INPUT ;
    USE SIGNAL ;
    ANTENNAGATEAREA 0.852800 ;
    ANTENNADIFFAREA 8.061600 ;
    PORT
      LAYER Metal2 ;
        RECT 474.040 74.780 474.440 75.180 ;
    END
  END Tile_X1Y0_SS4END[6]
  PIN Tile_X1Y0_SS4END[7]
    DIRECTION INPUT ;
    USE SIGNAL ;
    ANTENNAGATEAREA 0.852800 ;
    ANTENNADIFFAREA 8.061600 ;
    PORT
      LAYER Metal2 ;
        RECT 475.960 74.780 476.360 75.180 ;
    END
  END Tile_X1Y0_SS4END[7]
  PIN Tile_X1Y0_SS4END[8]
    DIRECTION INPUT ;
    USE SIGNAL ;
    ANTENNAGATEAREA 0.852800 ;
    ANTENNADIFFAREA 8.061600 ;
    PORT
      LAYER Metal2 ;
        RECT 477.880 74.780 478.280 75.180 ;
    END
  END Tile_X1Y0_SS4END[8]
  PIN Tile_X1Y0_SS4END[9]
    DIRECTION INPUT ;
    USE SIGNAL ;
    ANTENNAGATEAREA 0.852800 ;
    ANTENNADIFFAREA 8.061600 ;
    PORT
      LAYER Metal2 ;
        RECT 479.800 74.780 480.200 75.180 ;
    END
  END Tile_X1Y0_SS4END[9]
  PIN Tile_X2Y0_Co
    DIRECTION OUTPUT ;
    USE SIGNAL ;
    ANTENNADIFFAREA 2.314600 ;
    PORT
      LAYER Metal2 ;
        RECT 766.360 74.780 766.760 75.180 ;
    END
  END Tile_X2Y0_Co
  PIN Tile_X2Y0_FrameStrobe[0]
    DIRECTION INPUT ;
    USE SIGNAL ;
    ANTENNAGATEAREA 11.745500 ;
    ANTENNADIFFAREA 66.508202 ;
    PORT
      LAYER Metal2 ;
        RECT 548.440 0.000 548.840 0.400 ;
    END
  END Tile_X2Y0_FrameStrobe[0]
  PIN Tile_X2Y0_FrameStrobe[10]
    DIRECTION INPUT ;
    USE SIGNAL ;
    ANTENNAGATEAREA 0.180700 ;
    ANTENNADIFFAREA 2.015400 ;
    PORT
      LAYER Metal2 ;
        RECT 682.840 0.000 683.240 0.400 ;
    END
  END Tile_X2Y0_FrameStrobe[10]
  PIN Tile_X2Y0_FrameStrobe[11]
    DIRECTION INPUT ;
    USE SIGNAL ;
    ANTENNAGATEAREA 0.180700 ;
    ANTENNADIFFAREA 2.015400 ;
    PORT
      LAYER Metal2 ;
        RECT 696.280 0.000 696.680 0.400 ;
    END
  END Tile_X2Y0_FrameStrobe[11]
  PIN Tile_X2Y0_FrameStrobe[12]
    DIRECTION INPUT ;
    USE SIGNAL ;
    ANTENNAGATEAREA 0.180700 ;
    ANTENNADIFFAREA 2.015400 ;
    PORT
      LAYER Metal2 ;
        RECT 709.720 0.000 710.120 0.400 ;
    END
  END Tile_X2Y0_FrameStrobe[12]
  PIN Tile_X2Y0_FrameStrobe[13]
    DIRECTION INPUT ;
    USE SIGNAL ;
    ANTENNAGATEAREA 0.180700 ;
    ANTENNADIFFAREA 2.015400 ;
    PORT
      LAYER Metal2 ;
        RECT 723.160 0.000 723.560 0.400 ;
    END
  END Tile_X2Y0_FrameStrobe[13]
  PIN Tile_X2Y0_FrameStrobe[14]
    DIRECTION INPUT ;
    USE SIGNAL ;
    ANTENNAGATEAREA 0.180700 ;
    ANTENNADIFFAREA 2.015400 ;
    PORT
      LAYER Metal2 ;
        RECT 736.600 0.000 737.000 0.400 ;
    END
  END Tile_X2Y0_FrameStrobe[14]
  PIN Tile_X2Y0_FrameStrobe[15]
    DIRECTION INPUT ;
    USE SIGNAL ;
    ANTENNAGATEAREA 0.180700 ;
    ANTENNADIFFAREA 2.015400 ;
    PORT
      LAYER Metal2 ;
        RECT 750.040 0.000 750.440 0.400 ;
    END
  END Tile_X2Y0_FrameStrobe[15]
  PIN Tile_X2Y0_FrameStrobe[16]
    DIRECTION INPUT ;
    USE SIGNAL ;
    ANTENNAGATEAREA 0.180700 ;
    ANTENNADIFFAREA 2.015400 ;
    PORT
      LAYER Metal2 ;
        RECT 763.480 0.000 763.880 0.400 ;
    END
  END Tile_X2Y0_FrameStrobe[16]
  PIN Tile_X2Y0_FrameStrobe[17]
    DIRECTION INPUT ;
    USE SIGNAL ;
    ANTENNAGATEAREA 0.180700 ;
    ANTENNADIFFAREA 2.015400 ;
    PORT
      LAYER Metal2 ;
        RECT 776.920 0.000 777.320 0.400 ;
    END
  END Tile_X2Y0_FrameStrobe[17]
  PIN Tile_X2Y0_FrameStrobe[18]
    DIRECTION INPUT ;
    USE SIGNAL ;
    ANTENNAGATEAREA 0.180700 ;
    ANTENNADIFFAREA 2.015400 ;
    PORT
      LAYER Metal2 ;
        RECT 790.360 0.000 790.760 0.400 ;
    END
  END Tile_X2Y0_FrameStrobe[18]
  PIN Tile_X2Y0_FrameStrobe[19]
    DIRECTION INPUT ;
    USE SIGNAL ;
    ANTENNAGATEAREA 0.180700 ;
    ANTENNADIFFAREA 2.015400 ;
    PORT
      LAYER Metal2 ;
        RECT 803.800 0.000 804.200 0.400 ;
    END
  END Tile_X2Y0_FrameStrobe[19]
  PIN Tile_X2Y0_FrameStrobe[1]
    DIRECTION INPUT ;
    USE SIGNAL ;
    ANTENNAGATEAREA 11.745500 ;
    ANTENNADIFFAREA 66.508202 ;
    PORT
      LAYER Metal2 ;
        RECT 561.880 0.000 562.280 0.400 ;
    END
  END Tile_X2Y0_FrameStrobe[1]
  PIN Tile_X2Y0_FrameStrobe[2]
    DIRECTION INPUT ;
    USE SIGNAL ;
    ANTENNAGATEAREA 11.745500 ;
    ANTENNADIFFAREA 66.508202 ;
    PORT
      LAYER Metal2 ;
        RECT 575.320 0.000 575.720 0.400 ;
    END
  END Tile_X2Y0_FrameStrobe[2]
  PIN Tile_X2Y0_FrameStrobe[3]
    DIRECTION INPUT ;
    USE SIGNAL ;
    ANTENNAGATEAREA 0.180700 ;
    ANTENNADIFFAREA 2.015400 ;
    PORT
      LAYER Metal2 ;
        RECT 588.760 0.000 589.160 0.400 ;
    END
  END Tile_X2Y0_FrameStrobe[3]
  PIN Tile_X2Y0_FrameStrobe[4]
    DIRECTION INPUT ;
    USE SIGNAL ;
    ANTENNAGATEAREA 0.180700 ;
    ANTENNADIFFAREA 2.015400 ;
    PORT
      LAYER Metal2 ;
        RECT 602.200 0.000 602.600 0.400 ;
    END
  END Tile_X2Y0_FrameStrobe[4]
  PIN Tile_X2Y0_FrameStrobe[5]
    DIRECTION INPUT ;
    USE SIGNAL ;
    ANTENNAGATEAREA 0.180700 ;
    ANTENNADIFFAREA 2.015400 ;
    PORT
      LAYER Metal2 ;
        RECT 615.640 0.000 616.040 0.400 ;
    END
  END Tile_X2Y0_FrameStrobe[5]
  PIN Tile_X2Y0_FrameStrobe[6]
    DIRECTION INPUT ;
    USE SIGNAL ;
    ANTENNAGATEAREA 0.180700 ;
    ANTENNADIFFAREA 2.015400 ;
    PORT
      LAYER Metal2 ;
        RECT 629.080 0.000 629.480 0.400 ;
    END
  END Tile_X2Y0_FrameStrobe[6]
  PIN Tile_X2Y0_FrameStrobe[7]
    DIRECTION INPUT ;
    USE SIGNAL ;
    ANTENNAGATEAREA 0.180700 ;
    ANTENNADIFFAREA 2.015400 ;
    PORT
      LAYER Metal2 ;
        RECT 642.520 0.000 642.920 0.400 ;
    END
  END Tile_X2Y0_FrameStrobe[7]
  PIN Tile_X2Y0_FrameStrobe[8]
    DIRECTION INPUT ;
    USE SIGNAL ;
    ANTENNAGATEAREA 0.180700 ;
    ANTENNADIFFAREA 2.015400 ;
    PORT
      LAYER Metal2 ;
        RECT 655.960 0.000 656.360 0.400 ;
    END
  END Tile_X2Y0_FrameStrobe[8]
  PIN Tile_X2Y0_FrameStrobe[9]
    DIRECTION INPUT ;
    USE SIGNAL ;
    ANTENNAGATEAREA 0.180700 ;
    ANTENNADIFFAREA 2.015400 ;
    PORT
      LAYER Metal2 ;
        RECT 669.400 0.000 669.800 0.400 ;
    END
  END Tile_X2Y0_FrameStrobe[9]
  PIN Tile_X2Y0_FrameStrobe_O[0]
    DIRECTION OUTPUT ;
    USE SIGNAL ;
    ANTENNADIFFAREA 2.724000 ;
    PORT
      LAYER Metal2 ;
        RECT 771.160 74.780 771.560 75.180 ;
    END
  END Tile_X2Y0_FrameStrobe_O[0]
  PIN Tile_X2Y0_FrameStrobe_O[10]
    DIRECTION OUTPUT ;
    USE SIGNAL ;
    ANTENNADIFFAREA 2.724000 ;
    PORT
      LAYER Metal2 ;
        RECT 790.360 74.780 790.760 75.180 ;
    END
  END Tile_X2Y0_FrameStrobe_O[10]
  PIN Tile_X2Y0_FrameStrobe_O[11]
    DIRECTION OUTPUT ;
    USE SIGNAL ;
    ANTENNADIFFAREA 2.724000 ;
    PORT
      LAYER Metal2 ;
        RECT 792.280 74.780 792.680 75.180 ;
    END
  END Tile_X2Y0_FrameStrobe_O[11]
  PIN Tile_X2Y0_FrameStrobe_O[12]
    DIRECTION OUTPUT ;
    USE SIGNAL ;
    ANTENNADIFFAREA 2.724000 ;
    PORT
      LAYER Metal2 ;
        RECT 794.200 74.780 794.600 75.180 ;
    END
  END Tile_X2Y0_FrameStrobe_O[12]
  PIN Tile_X2Y0_FrameStrobe_O[13]
    DIRECTION OUTPUT ;
    USE SIGNAL ;
    ANTENNADIFFAREA 2.724000 ;
    PORT
      LAYER Metal2 ;
        RECT 796.120 74.780 796.520 75.180 ;
    END
  END Tile_X2Y0_FrameStrobe_O[13]
  PIN Tile_X2Y0_FrameStrobe_O[14]
    DIRECTION OUTPUT ;
    USE SIGNAL ;
    ANTENNADIFFAREA 2.724000 ;
    PORT
      LAYER Metal2 ;
        RECT 798.040 74.780 798.440 75.180 ;
    END
  END Tile_X2Y0_FrameStrobe_O[14]
  PIN Tile_X2Y0_FrameStrobe_O[15]
    DIRECTION OUTPUT ;
    USE SIGNAL ;
    ANTENNADIFFAREA 2.724000 ;
    PORT
      LAYER Metal2 ;
        RECT 799.960 74.780 800.360 75.180 ;
    END
  END Tile_X2Y0_FrameStrobe_O[15]
  PIN Tile_X2Y0_FrameStrobe_O[16]
    DIRECTION OUTPUT ;
    USE SIGNAL ;
    ANTENNADIFFAREA 2.724000 ;
    PORT
      LAYER Metal2 ;
        RECT 801.880 74.780 802.280 75.180 ;
    END
  END Tile_X2Y0_FrameStrobe_O[16]
  PIN Tile_X2Y0_FrameStrobe_O[17]
    DIRECTION OUTPUT ;
    USE SIGNAL ;
    ANTENNADIFFAREA 2.724000 ;
    PORT
      LAYER Metal2 ;
        RECT 803.800 74.780 804.200 75.180 ;
    END
  END Tile_X2Y0_FrameStrobe_O[17]
  PIN Tile_X2Y0_FrameStrobe_O[18]
    DIRECTION OUTPUT ;
    USE SIGNAL ;
    ANTENNADIFFAREA 2.724000 ;
    PORT
      LAYER Metal2 ;
        RECT 805.720 74.780 806.120 75.180 ;
    END
  END Tile_X2Y0_FrameStrobe_O[18]
  PIN Tile_X2Y0_FrameStrobe_O[19]
    DIRECTION OUTPUT ;
    USE SIGNAL ;
    ANTENNADIFFAREA 2.724000 ;
    PORT
      LAYER Metal2 ;
        RECT 807.640 74.780 808.040 75.180 ;
    END
  END Tile_X2Y0_FrameStrobe_O[19]
  PIN Tile_X2Y0_FrameStrobe_O[1]
    DIRECTION OUTPUT ;
    USE SIGNAL ;
    ANTENNADIFFAREA 2.724000 ;
    PORT
      LAYER Metal2 ;
        RECT 773.080 74.780 773.480 75.180 ;
    END
  END Tile_X2Y0_FrameStrobe_O[1]
  PIN Tile_X2Y0_FrameStrobe_O[2]
    DIRECTION OUTPUT ;
    USE SIGNAL ;
    ANTENNADIFFAREA 2.724000 ;
    PORT
      LAYER Metal2 ;
        RECT 775.000 74.780 775.400 75.180 ;
    END
  END Tile_X2Y0_FrameStrobe_O[2]
  PIN Tile_X2Y0_FrameStrobe_O[3]
    DIRECTION OUTPUT ;
    USE SIGNAL ;
    ANTENNADIFFAREA 2.724000 ;
    PORT
      LAYER Metal2 ;
        RECT 776.920 74.780 777.320 75.180 ;
    END
  END Tile_X2Y0_FrameStrobe_O[3]
  PIN Tile_X2Y0_FrameStrobe_O[4]
    DIRECTION OUTPUT ;
    USE SIGNAL ;
    ANTENNADIFFAREA 2.724000 ;
    PORT
      LAYER Metal2 ;
        RECT 778.840 74.780 779.240 75.180 ;
    END
  END Tile_X2Y0_FrameStrobe_O[4]
  PIN Tile_X2Y0_FrameStrobe_O[5]
    DIRECTION OUTPUT ;
    USE SIGNAL ;
    ANTENNADIFFAREA 2.724000 ;
    PORT
      LAYER Metal2 ;
        RECT 780.760 74.780 781.160 75.180 ;
    END
  END Tile_X2Y0_FrameStrobe_O[5]
  PIN Tile_X2Y0_FrameStrobe_O[6]
    DIRECTION OUTPUT ;
    USE SIGNAL ;
    ANTENNADIFFAREA 2.724000 ;
    PORT
      LAYER Metal2 ;
        RECT 782.680 74.780 783.080 75.180 ;
    END
  END Tile_X2Y0_FrameStrobe_O[6]
  PIN Tile_X2Y0_FrameStrobe_O[7]
    DIRECTION OUTPUT ;
    USE SIGNAL ;
    ANTENNADIFFAREA 2.724000 ;
    PORT
      LAYER Metal2 ;
        RECT 784.600 74.780 785.000 75.180 ;
    END
  END Tile_X2Y0_FrameStrobe_O[7]
  PIN Tile_X2Y0_FrameStrobe_O[8]
    DIRECTION OUTPUT ;
    USE SIGNAL ;
    ANTENNADIFFAREA 2.724000 ;
    PORT
      LAYER Metal2 ;
        RECT 786.520 74.780 786.920 75.180 ;
    END
  END Tile_X2Y0_FrameStrobe_O[8]
  PIN Tile_X2Y0_FrameStrobe_O[9]
    DIRECTION OUTPUT ;
    USE SIGNAL ;
    ANTENNADIFFAREA 2.724000 ;
    PORT
      LAYER Metal2 ;
        RECT 788.440 74.780 788.840 75.180 ;
    END
  END Tile_X2Y0_FrameStrobe_O[9]
  PIN Tile_X2Y0_N1BEG[0]
    DIRECTION OUTPUT ;
    USE SIGNAL ;
    ANTENNADIFFAREA 2.724000 ;
    PORT
      LAYER Metal2 ;
        RECT 542.680 74.780 543.080 75.180 ;
    END
  END Tile_X2Y0_N1BEG[0]
  PIN Tile_X2Y0_N1BEG[1]
    DIRECTION OUTPUT ;
    USE SIGNAL ;
    ANTENNADIFFAREA 2.724000 ;
    PORT
      LAYER Metal2 ;
        RECT 544.600 74.780 545.000 75.180 ;
    END
  END Tile_X2Y0_N1BEG[1]
  PIN Tile_X2Y0_N1BEG[2]
    DIRECTION OUTPUT ;
    USE SIGNAL ;
    ANTENNADIFFAREA 2.724000 ;
    PORT
      LAYER Metal2 ;
        RECT 546.520 74.780 546.920 75.180 ;
    END
  END Tile_X2Y0_N1BEG[2]
  PIN Tile_X2Y0_N1BEG[3]
    DIRECTION OUTPUT ;
    USE SIGNAL ;
    ANTENNADIFFAREA 2.724000 ;
    PORT
      LAYER Metal2 ;
        RECT 548.440 74.780 548.840 75.180 ;
    END
  END Tile_X2Y0_N1BEG[3]
  PIN Tile_X2Y0_N2BEG[0]
    DIRECTION OUTPUT ;
    USE SIGNAL ;
    ANTENNADIFFAREA 2.724000 ;
    PORT
      LAYER Metal2 ;
        RECT 551.320 74.780 551.720 75.180 ;
    END
  END Tile_X2Y0_N2BEG[0]
  PIN Tile_X2Y0_N2BEG[1]
    DIRECTION OUTPUT ;
    USE SIGNAL ;
    ANTENNADIFFAREA 2.724000 ;
    PORT
      LAYER Metal2 ;
        RECT 553.240 74.780 553.640 75.180 ;
    END
  END Tile_X2Y0_N2BEG[1]
  PIN Tile_X2Y0_N2BEG[2]
    DIRECTION OUTPUT ;
    USE SIGNAL ;
    ANTENNADIFFAREA 2.724000 ;
    PORT
      LAYER Metal2 ;
        RECT 555.160 74.780 555.560 75.180 ;
    END
  END Tile_X2Y0_N2BEG[2]
  PIN Tile_X2Y0_N2BEG[3]
    DIRECTION OUTPUT ;
    USE SIGNAL ;
    ANTENNADIFFAREA 2.724000 ;
    PORT
      LAYER Metal2 ;
        RECT 557.080 74.780 557.480 75.180 ;
    END
  END Tile_X2Y0_N2BEG[3]
  PIN Tile_X2Y0_N2BEG[4]
    DIRECTION OUTPUT ;
    USE SIGNAL ;
    ANTENNADIFFAREA 2.724000 ;
    PORT
      LAYER Metal2 ;
        RECT 559.000 74.780 559.400 75.180 ;
    END
  END Tile_X2Y0_N2BEG[4]
  PIN Tile_X2Y0_N2BEG[5]
    DIRECTION OUTPUT ;
    USE SIGNAL ;
    ANTENNADIFFAREA 2.724000 ;
    PORT
      LAYER Metal2 ;
        RECT 560.920 74.780 561.320 75.180 ;
    END
  END Tile_X2Y0_N2BEG[5]
  PIN Tile_X2Y0_N2BEG[6]
    DIRECTION OUTPUT ;
    USE SIGNAL ;
    ANTENNADIFFAREA 2.724000 ;
    PORT
      LAYER Metal2 ;
        RECT 562.840 74.780 563.240 75.180 ;
    END
  END Tile_X2Y0_N2BEG[6]
  PIN Tile_X2Y0_N2BEG[7]
    DIRECTION OUTPUT ;
    USE SIGNAL ;
    ANTENNADIFFAREA 2.724000 ;
    PORT
      LAYER Metal2 ;
        RECT 564.760 74.780 565.160 75.180 ;
    END
  END Tile_X2Y0_N2BEG[7]
  PIN Tile_X2Y0_N2BEGb[0]
    DIRECTION OUTPUT ;
    USE SIGNAL ;
    ANTENNADIFFAREA 2.724000 ;
    PORT
      LAYER Metal2 ;
        RECT 567.640 74.780 568.040 75.180 ;
    END
  END Tile_X2Y0_N2BEGb[0]
  PIN Tile_X2Y0_N2BEGb[1]
    DIRECTION OUTPUT ;
    USE SIGNAL ;
    ANTENNADIFFAREA 2.724000 ;
    PORT
      LAYER Metal2 ;
        RECT 569.560 74.780 569.960 75.180 ;
    END
  END Tile_X2Y0_N2BEGb[1]
  PIN Tile_X2Y0_N2BEGb[2]
    DIRECTION OUTPUT ;
    USE SIGNAL ;
    ANTENNADIFFAREA 2.724000 ;
    PORT
      LAYER Metal2 ;
        RECT 571.480 74.780 571.880 75.180 ;
    END
  END Tile_X2Y0_N2BEGb[2]
  PIN Tile_X2Y0_N2BEGb[3]
    DIRECTION OUTPUT ;
    USE SIGNAL ;
    ANTENNADIFFAREA 2.724000 ;
    PORT
      LAYER Metal2 ;
        RECT 573.400 74.780 573.800 75.180 ;
    END
  END Tile_X2Y0_N2BEGb[3]
  PIN Tile_X2Y0_N2BEGb[4]
    DIRECTION OUTPUT ;
    USE SIGNAL ;
    ANTENNADIFFAREA 2.724000 ;
    PORT
      LAYER Metal2 ;
        RECT 575.320 74.780 575.720 75.180 ;
    END
  END Tile_X2Y0_N2BEGb[4]
  PIN Tile_X2Y0_N2BEGb[5]
    DIRECTION OUTPUT ;
    USE SIGNAL ;
    ANTENNADIFFAREA 2.724000 ;
    PORT
      LAYER Metal2 ;
        RECT 577.240 74.780 577.640 75.180 ;
    END
  END Tile_X2Y0_N2BEGb[5]
  PIN Tile_X2Y0_N2BEGb[6]
    DIRECTION OUTPUT ;
    USE SIGNAL ;
    ANTENNADIFFAREA 2.724000 ;
    PORT
      LAYER Metal2 ;
        RECT 579.160 74.780 579.560 75.180 ;
    END
  END Tile_X2Y0_N2BEGb[6]
  PIN Tile_X2Y0_N2BEGb[7]
    DIRECTION OUTPUT ;
    USE SIGNAL ;
    ANTENNADIFFAREA 2.724000 ;
    PORT
      LAYER Metal2 ;
        RECT 581.080 74.780 581.480 75.180 ;
    END
  END Tile_X2Y0_N2BEGb[7]
  PIN Tile_X2Y0_N4BEG[0]
    DIRECTION OUTPUT ;
    USE SIGNAL ;
    ANTENNADIFFAREA 2.724000 ;
    PORT
      LAYER Metal2 ;
        RECT 585.880 74.780 586.280 75.180 ;
    END
  END Tile_X2Y0_N4BEG[0]
  PIN Tile_X2Y0_N4BEG[10]
    DIRECTION OUTPUT ;
    USE SIGNAL ;
    ANTENNADIFFAREA 2.724000 ;
    PORT
      LAYER Metal2 ;
        RECT 605.080 74.780 605.480 75.180 ;
    END
  END Tile_X2Y0_N4BEG[10]
  PIN Tile_X2Y0_N4BEG[11]
    DIRECTION OUTPUT ;
    USE SIGNAL ;
    ANTENNADIFFAREA 2.724000 ;
    PORT
      LAYER Metal2 ;
        RECT 607.000 74.780 607.400 75.180 ;
    END
  END Tile_X2Y0_N4BEG[11]
  PIN Tile_X2Y0_N4BEG[12]
    DIRECTION OUTPUT ;
    USE SIGNAL ;
    ANTENNADIFFAREA 2.724000 ;
    PORT
      LAYER Metal2 ;
        RECT 608.920 74.780 609.320 75.180 ;
    END
  END Tile_X2Y0_N4BEG[12]
  PIN Tile_X2Y0_N4BEG[13]
    DIRECTION OUTPUT ;
    USE SIGNAL ;
    ANTENNADIFFAREA 2.724000 ;
    PORT
      LAYER Metal2 ;
        RECT 610.840 74.780 611.240 75.180 ;
    END
  END Tile_X2Y0_N4BEG[13]
  PIN Tile_X2Y0_N4BEG[14]
    DIRECTION OUTPUT ;
    USE SIGNAL ;
    ANTENNADIFFAREA 2.724000 ;
    PORT
      LAYER Metal2 ;
        RECT 612.760 74.780 613.160 75.180 ;
    END
  END Tile_X2Y0_N4BEG[14]
  PIN Tile_X2Y0_N4BEG[15]
    DIRECTION OUTPUT ;
    USE SIGNAL ;
    ANTENNADIFFAREA 2.724000 ;
    PORT
      LAYER Metal2 ;
        RECT 614.680 74.780 615.080 75.180 ;
    END
  END Tile_X2Y0_N4BEG[15]
  PIN Tile_X2Y0_N4BEG[1]
    DIRECTION OUTPUT ;
    USE SIGNAL ;
    ANTENNADIFFAREA 2.724000 ;
    PORT
      LAYER Metal2 ;
        RECT 587.800 74.780 588.200 75.180 ;
    END
  END Tile_X2Y0_N4BEG[1]
  PIN Tile_X2Y0_N4BEG[2]
    DIRECTION OUTPUT ;
    USE SIGNAL ;
    ANTENNADIFFAREA 2.724000 ;
    PORT
      LAYER Metal2 ;
        RECT 589.720 74.780 590.120 75.180 ;
    END
  END Tile_X2Y0_N4BEG[2]
  PIN Tile_X2Y0_N4BEG[3]
    DIRECTION OUTPUT ;
    USE SIGNAL ;
    ANTENNADIFFAREA 2.724000 ;
    PORT
      LAYER Metal2 ;
        RECT 591.640 74.780 592.040 75.180 ;
    END
  END Tile_X2Y0_N4BEG[3]
  PIN Tile_X2Y0_N4BEG[4]
    DIRECTION OUTPUT ;
    USE SIGNAL ;
    ANTENNADIFFAREA 2.724000 ;
    PORT
      LAYER Metal2 ;
        RECT 593.560 74.780 593.960 75.180 ;
    END
  END Tile_X2Y0_N4BEG[4]
  PIN Tile_X2Y0_N4BEG[5]
    DIRECTION OUTPUT ;
    USE SIGNAL ;
    ANTENNADIFFAREA 2.724000 ;
    PORT
      LAYER Metal2 ;
        RECT 595.480 74.780 595.880 75.180 ;
    END
  END Tile_X2Y0_N4BEG[5]
  PIN Tile_X2Y0_N4BEG[6]
    DIRECTION OUTPUT ;
    USE SIGNAL ;
    ANTENNADIFFAREA 2.724000 ;
    PORT
      LAYER Metal2 ;
        RECT 597.400 74.780 597.800 75.180 ;
    END
  END Tile_X2Y0_N4BEG[6]
  PIN Tile_X2Y0_N4BEG[7]
    DIRECTION OUTPUT ;
    USE SIGNAL ;
    ANTENNADIFFAREA 2.724000 ;
    PORT
      LAYER Metal2 ;
        RECT 599.320 74.780 599.720 75.180 ;
    END
  END Tile_X2Y0_N4BEG[7]
  PIN Tile_X2Y0_N4BEG[8]
    DIRECTION OUTPUT ;
    USE SIGNAL ;
    ANTENNADIFFAREA 2.724000 ;
    PORT
      LAYER Metal2 ;
        RECT 601.240 74.780 601.640 75.180 ;
    END
  END Tile_X2Y0_N4BEG[8]
  PIN Tile_X2Y0_N4BEG[9]
    DIRECTION OUTPUT ;
    USE SIGNAL ;
    ANTENNADIFFAREA 2.724000 ;
    PORT
      LAYER Metal2 ;
        RECT 603.160 74.780 603.560 75.180 ;
    END
  END Tile_X2Y0_N4BEG[9]
  PIN Tile_X2Y0_NN4BEG[0]
    DIRECTION OUTPUT ;
    USE SIGNAL ;
    ANTENNADIFFAREA 2.724000 ;
    PORT
      LAYER Metal2 ;
        RECT 620.440 74.780 620.840 75.180 ;
    END
  END Tile_X2Y0_NN4BEG[0]
  PIN Tile_X2Y0_NN4BEG[10]
    DIRECTION OUTPUT ;
    USE SIGNAL ;
    ANTENNADIFFAREA 2.724000 ;
    PORT
      LAYER Metal2 ;
        RECT 639.640 74.780 640.040 75.180 ;
    END
  END Tile_X2Y0_NN4BEG[10]
  PIN Tile_X2Y0_NN4BEG[11]
    DIRECTION OUTPUT ;
    USE SIGNAL ;
    ANTENNADIFFAREA 2.724000 ;
    PORT
      LAYER Metal2 ;
        RECT 641.560 74.780 641.960 75.180 ;
    END
  END Tile_X2Y0_NN4BEG[11]
  PIN Tile_X2Y0_NN4BEG[12]
    DIRECTION OUTPUT ;
    USE SIGNAL ;
    ANTENNADIFFAREA 2.724000 ;
    PORT
      LAYER Metal2 ;
        RECT 643.480 74.780 643.880 75.180 ;
    END
  END Tile_X2Y0_NN4BEG[12]
  PIN Tile_X2Y0_NN4BEG[13]
    DIRECTION OUTPUT ;
    USE SIGNAL ;
    ANTENNADIFFAREA 2.724000 ;
    PORT
      LAYER Metal2 ;
        RECT 645.400 74.780 645.800 75.180 ;
    END
  END Tile_X2Y0_NN4BEG[13]
  PIN Tile_X2Y0_NN4BEG[14]
    DIRECTION OUTPUT ;
    USE SIGNAL ;
    ANTENNADIFFAREA 2.724000 ;
    PORT
      LAYER Metal2 ;
        RECT 647.320 74.780 647.720 75.180 ;
    END
  END Tile_X2Y0_NN4BEG[14]
  PIN Tile_X2Y0_NN4BEG[15]
    DIRECTION OUTPUT ;
    USE SIGNAL ;
    ANTENNADIFFAREA 2.724000 ;
    PORT
      LAYER Metal2 ;
        RECT 649.240 74.780 649.640 75.180 ;
    END
  END Tile_X2Y0_NN4BEG[15]
  PIN Tile_X2Y0_NN4BEG[1]
    DIRECTION OUTPUT ;
    USE SIGNAL ;
    ANTENNADIFFAREA 2.724000 ;
    PORT
      LAYER Metal2 ;
        RECT 622.360 74.780 622.760 75.180 ;
    END
  END Tile_X2Y0_NN4BEG[1]
  PIN Tile_X2Y0_NN4BEG[2]
    DIRECTION OUTPUT ;
    USE SIGNAL ;
    ANTENNADIFFAREA 2.724000 ;
    PORT
      LAYER Metal2 ;
        RECT 624.280 74.780 624.680 75.180 ;
    END
  END Tile_X2Y0_NN4BEG[2]
  PIN Tile_X2Y0_NN4BEG[3]
    DIRECTION OUTPUT ;
    USE SIGNAL ;
    ANTENNADIFFAREA 2.724000 ;
    PORT
      LAYER Metal2 ;
        RECT 626.200 74.780 626.600 75.180 ;
    END
  END Tile_X2Y0_NN4BEG[3]
  PIN Tile_X2Y0_NN4BEG[4]
    DIRECTION OUTPUT ;
    USE SIGNAL ;
    ANTENNADIFFAREA 2.724000 ;
    PORT
      LAYER Metal2 ;
        RECT 628.120 74.780 628.520 75.180 ;
    END
  END Tile_X2Y0_NN4BEG[4]
  PIN Tile_X2Y0_NN4BEG[5]
    DIRECTION OUTPUT ;
    USE SIGNAL ;
    ANTENNADIFFAREA 2.724000 ;
    PORT
      LAYER Metal2 ;
        RECT 630.040 74.780 630.440 75.180 ;
    END
  END Tile_X2Y0_NN4BEG[5]
  PIN Tile_X2Y0_NN4BEG[6]
    DIRECTION OUTPUT ;
    USE SIGNAL ;
    ANTENNADIFFAREA 2.724000 ;
    PORT
      LAYER Metal2 ;
        RECT 631.960 74.780 632.360 75.180 ;
    END
  END Tile_X2Y0_NN4BEG[6]
  PIN Tile_X2Y0_NN4BEG[7]
    DIRECTION OUTPUT ;
    USE SIGNAL ;
    ANTENNADIFFAREA 2.724000 ;
    PORT
      LAYER Metal2 ;
        RECT 633.880 74.780 634.280 75.180 ;
    END
  END Tile_X2Y0_NN4BEG[7]
  PIN Tile_X2Y0_NN4BEG[8]
    DIRECTION OUTPUT ;
    USE SIGNAL ;
    ANTENNADIFFAREA 2.724000 ;
    PORT
      LAYER Metal2 ;
        RECT 635.800 74.780 636.200 75.180 ;
    END
  END Tile_X2Y0_NN4BEG[8]
  PIN Tile_X2Y0_NN4BEG[9]
    DIRECTION OUTPUT ;
    USE SIGNAL ;
    ANTENNADIFFAREA 2.724000 ;
    PORT
      LAYER Metal2 ;
        RECT 637.720 74.780 638.120 75.180 ;
    END
  END Tile_X2Y0_NN4BEG[9]
  PIN Tile_X2Y0_S1END[0]
    DIRECTION INPUT ;
    USE SIGNAL ;
    ANTENNAGATEAREA 1.033500 ;
    ANTENNADIFFAREA 10.077000 ;
    PORT
      LAYER Metal2 ;
        RECT 654.040 74.780 654.440 75.180 ;
    END
  END Tile_X2Y0_S1END[0]
  PIN Tile_X2Y0_S1END[1]
    DIRECTION INPUT ;
    USE SIGNAL ;
    ANTENNAGATEAREA 1.033500 ;
    ANTENNADIFFAREA 10.077000 ;
    PORT
      LAYER Metal2 ;
        RECT 655.960 74.780 656.360 75.180 ;
    END
  END Tile_X2Y0_S1END[1]
  PIN Tile_X2Y0_S1END[2]
    DIRECTION INPUT ;
    USE SIGNAL ;
    ANTENNAGATEAREA 1.033500 ;
    ANTENNADIFFAREA 10.077000 ;
    PORT
      LAYER Metal2 ;
        RECT 657.880 74.780 658.280 75.180 ;
    END
  END Tile_X2Y0_S1END[2]
  PIN Tile_X2Y0_S1END[3]
    DIRECTION INPUT ;
    USE SIGNAL ;
    ANTENNAGATEAREA 1.033500 ;
    ANTENNADIFFAREA 10.077000 ;
    PORT
      LAYER Metal2 ;
        RECT 659.800 74.780 660.200 75.180 ;
    END
  END Tile_X2Y0_S1END[3]
  PIN Tile_X2Y0_S2END[0]
    DIRECTION INPUT ;
    USE SIGNAL ;
    ANTENNAGATEAREA 0.852800 ;
    ANTENNADIFFAREA 8.061600 ;
    PORT
      LAYER Metal2 ;
        RECT 679.960 74.780 680.360 75.180 ;
    END
  END Tile_X2Y0_S2END[0]
  PIN Tile_X2Y0_S2END[1]
    DIRECTION INPUT ;
    USE SIGNAL ;
    ANTENNAGATEAREA 0.852800 ;
    ANTENNADIFFAREA 8.061600 ;
    PORT
      LAYER Metal2 ;
        RECT 681.880 74.780 682.280 75.180 ;
    END
  END Tile_X2Y0_S2END[1]
  PIN Tile_X2Y0_S2END[2]
    DIRECTION INPUT ;
    USE SIGNAL ;
    ANTENNAGATEAREA 0.852800 ;
    ANTENNADIFFAREA 8.061600 ;
    PORT
      LAYER Metal2 ;
        RECT 683.800 74.780 684.200 75.180 ;
    END
  END Tile_X2Y0_S2END[2]
  PIN Tile_X2Y0_S2END[3]
    DIRECTION INPUT ;
    USE SIGNAL ;
    ANTENNAGATEAREA 0.852800 ;
    ANTENNADIFFAREA 8.061600 ;
    PORT
      LAYER Metal2 ;
        RECT 685.720 74.780 686.120 75.180 ;
    END
  END Tile_X2Y0_S2END[3]
  PIN Tile_X2Y0_S2END[4]
    DIRECTION INPUT ;
    USE SIGNAL ;
    ANTENNAGATEAREA 0.852800 ;
    ANTENNADIFFAREA 8.061600 ;
    PORT
      LAYER Metal2 ;
        RECT 687.640 74.780 688.040 75.180 ;
    END
  END Tile_X2Y0_S2END[4]
  PIN Tile_X2Y0_S2END[5]
    DIRECTION INPUT ;
    USE SIGNAL ;
    ANTENNAGATEAREA 0.852800 ;
    ANTENNADIFFAREA 8.061600 ;
    PORT
      LAYER Metal2 ;
        RECT 689.560 74.780 689.960 75.180 ;
    END
  END Tile_X2Y0_S2END[5]
  PIN Tile_X2Y0_S2END[6]
    DIRECTION INPUT ;
    USE SIGNAL ;
    ANTENNAGATEAREA 0.852800 ;
    ANTENNADIFFAREA 8.061600 ;
    PORT
      LAYER Metal2 ;
        RECT 691.480 74.780 691.880 75.180 ;
    END
  END Tile_X2Y0_S2END[6]
  PIN Tile_X2Y0_S2END[7]
    DIRECTION INPUT ;
    USE SIGNAL ;
    ANTENNAGATEAREA 0.852800 ;
    ANTENNADIFFAREA 8.061600 ;
    PORT
      LAYER Metal2 ;
        RECT 693.400 74.780 693.800 75.180 ;
    END
  END Tile_X2Y0_S2END[7]
  PIN Tile_X2Y0_S2MID[0]
    DIRECTION INPUT ;
    USE SIGNAL ;
    ANTENNAGATEAREA 1.246700 ;
    ANTENNADIFFAREA 12.092400 ;
    PORT
      LAYER Metal2 ;
        RECT 662.680 74.780 663.080 75.180 ;
    END
  END Tile_X2Y0_S2MID[0]
  PIN Tile_X2Y0_S2MID[1]
    DIRECTION INPUT ;
    USE SIGNAL ;
    ANTENNAGATEAREA 1.246700 ;
    ANTENNADIFFAREA 12.092400 ;
    PORT
      LAYER Metal2 ;
        RECT 664.600 74.780 665.000 75.180 ;
    END
  END Tile_X2Y0_S2MID[1]
  PIN Tile_X2Y0_S2MID[2]
    DIRECTION INPUT ;
    USE SIGNAL ;
    ANTENNAGATEAREA 1.246700 ;
    ANTENNADIFFAREA 12.092400 ;
    PORT
      LAYER Metal2 ;
        RECT 666.520 74.780 666.920 75.180 ;
    END
  END Tile_X2Y0_S2MID[2]
  PIN Tile_X2Y0_S2MID[3]
    DIRECTION INPUT ;
    USE SIGNAL ;
    ANTENNAGATEAREA 1.246700 ;
    ANTENNADIFFAREA 12.092400 ;
    PORT
      LAYER Metal2 ;
        RECT 668.440 74.780 668.840 75.180 ;
    END
  END Tile_X2Y0_S2MID[3]
  PIN Tile_X2Y0_S2MID[4]
    DIRECTION INPUT ;
    USE SIGNAL ;
    ANTENNAGATEAREA 1.246700 ;
    ANTENNADIFFAREA 12.092400 ;
    PORT
      LAYER Metal2 ;
        RECT 670.360 74.780 670.760 75.180 ;
    END
  END Tile_X2Y0_S2MID[4]
  PIN Tile_X2Y0_S2MID[5]
    DIRECTION INPUT ;
    USE SIGNAL ;
    ANTENNAGATEAREA 1.246700 ;
    ANTENNADIFFAREA 12.092400 ;
    PORT
      LAYER Metal2 ;
        RECT 672.280 74.780 672.680 75.180 ;
    END
  END Tile_X2Y0_S2MID[5]
  PIN Tile_X2Y0_S2MID[6]
    DIRECTION INPUT ;
    USE SIGNAL ;
    ANTENNAGATEAREA 1.246700 ;
    ANTENNADIFFAREA 12.092400 ;
    PORT
      LAYER Metal2 ;
        RECT 674.200 74.780 674.600 75.180 ;
    END
  END Tile_X2Y0_S2MID[6]
  PIN Tile_X2Y0_S2MID[7]
    DIRECTION INPUT ;
    USE SIGNAL ;
    ANTENNAGATEAREA 1.246700 ;
    ANTENNADIFFAREA 12.092400 ;
    PORT
      LAYER Metal2 ;
        RECT 676.120 74.780 676.520 75.180 ;
    END
  END Tile_X2Y0_S2MID[7]
  PIN Tile_X2Y0_S4END[0]
    DIRECTION INPUT ;
    USE SIGNAL ;
    ANTENNAGATEAREA 0.426400 ;
    ANTENNADIFFAREA 4.030800 ;
    PORT
      LAYER Metal2 ;
        RECT 698.200 74.780 698.600 75.180 ;
    END
  END Tile_X2Y0_S4END[0]
  PIN Tile_X2Y0_S4END[10]
    DIRECTION INPUT ;
    USE SIGNAL ;
    ANTENNAGATEAREA 0.426400 ;
    ANTENNADIFFAREA 4.030800 ;
    PORT
      LAYER Metal2 ;
        RECT 717.400 74.780 717.800 75.180 ;
    END
  END Tile_X2Y0_S4END[10]
  PIN Tile_X2Y0_S4END[11]
    DIRECTION INPUT ;
    USE SIGNAL ;
    ANTENNAGATEAREA 0.426400 ;
    ANTENNADIFFAREA 4.030800 ;
    PORT
      LAYER Metal2 ;
        RECT 719.320 74.780 719.720 75.180 ;
    END
  END Tile_X2Y0_S4END[11]
  PIN Tile_X2Y0_S4END[12]
    DIRECTION INPUT ;
    USE SIGNAL ;
    ANTENNAGATEAREA 0.426400 ;
    ANTENNADIFFAREA 4.030800 ;
    PORT
      LAYER Metal2 ;
        RECT 721.240 74.780 721.640 75.180 ;
    END
  END Tile_X2Y0_S4END[12]
  PIN Tile_X2Y0_S4END[13]
    DIRECTION INPUT ;
    USE SIGNAL ;
    ANTENNAGATEAREA 0.426400 ;
    ANTENNADIFFAREA 4.030800 ;
    PORT
      LAYER Metal2 ;
        RECT 723.160 74.780 723.560 75.180 ;
    END
  END Tile_X2Y0_S4END[13]
  PIN Tile_X2Y0_S4END[14]
    DIRECTION INPUT ;
    USE SIGNAL ;
    ANTENNAGATEAREA 0.426400 ;
    ANTENNADIFFAREA 4.030800 ;
    PORT
      LAYER Metal2 ;
        RECT 725.080 74.780 725.480 75.180 ;
    END
  END Tile_X2Y0_S4END[14]
  PIN Tile_X2Y0_S4END[15]
    DIRECTION INPUT ;
    USE SIGNAL ;
    ANTENNAGATEAREA 0.426400 ;
    ANTENNADIFFAREA 4.030800 ;
    PORT
      LAYER Metal2 ;
        RECT 727.000 74.780 727.400 75.180 ;
    END
  END Tile_X2Y0_S4END[15]
  PIN Tile_X2Y0_S4END[1]
    DIRECTION INPUT ;
    USE SIGNAL ;
    ANTENNAGATEAREA 0.426400 ;
    ANTENNADIFFAREA 4.030800 ;
    PORT
      LAYER Metal2 ;
        RECT 700.120 74.780 700.520 75.180 ;
    END
  END Tile_X2Y0_S4END[1]
  PIN Tile_X2Y0_S4END[2]
    DIRECTION INPUT ;
    USE SIGNAL ;
    ANTENNAGATEAREA 0.426400 ;
    ANTENNADIFFAREA 4.030800 ;
    PORT
      LAYER Metal2 ;
        RECT 702.040 74.780 702.440 75.180 ;
    END
  END Tile_X2Y0_S4END[2]
  PIN Tile_X2Y0_S4END[3]
    DIRECTION INPUT ;
    USE SIGNAL ;
    ANTENNAGATEAREA 0.426400 ;
    ANTENNADIFFAREA 4.030800 ;
    PORT
      LAYER Metal2 ;
        RECT 703.960 74.780 704.360 75.180 ;
    END
  END Tile_X2Y0_S4END[3]
  PIN Tile_X2Y0_S4END[4]
    DIRECTION INPUT ;
    USE SIGNAL ;
    ANTENNAGATEAREA 0.426400 ;
    ANTENNADIFFAREA 4.030800 ;
    PORT
      LAYER Metal2 ;
        RECT 705.880 74.780 706.280 75.180 ;
    END
  END Tile_X2Y0_S4END[4]
  PIN Tile_X2Y0_S4END[5]
    DIRECTION INPUT ;
    USE SIGNAL ;
    ANTENNAGATEAREA 0.426400 ;
    ANTENNADIFFAREA 4.030800 ;
    PORT
      LAYER Metal2 ;
        RECT 707.800 74.780 708.200 75.180 ;
    END
  END Tile_X2Y0_S4END[5]
  PIN Tile_X2Y0_S4END[6]
    DIRECTION INPUT ;
    USE SIGNAL ;
    ANTENNAGATEAREA 0.426400 ;
    ANTENNADIFFAREA 4.030800 ;
    PORT
      LAYER Metal2 ;
        RECT 709.720 74.780 710.120 75.180 ;
    END
  END Tile_X2Y0_S4END[6]
  PIN Tile_X2Y0_S4END[7]
    DIRECTION INPUT ;
    USE SIGNAL ;
    ANTENNAGATEAREA 0.426400 ;
    ANTENNADIFFAREA 4.030800 ;
    PORT
      LAYER Metal2 ;
        RECT 711.640 74.780 712.040 75.180 ;
    END
  END Tile_X2Y0_S4END[7]
  PIN Tile_X2Y0_S4END[8]
    DIRECTION INPUT ;
    USE SIGNAL ;
    ANTENNAGATEAREA 0.426400 ;
    ANTENNADIFFAREA 4.030800 ;
    PORT
      LAYER Metal2 ;
        RECT 713.560 74.780 713.960 75.180 ;
    END
  END Tile_X2Y0_S4END[8]
  PIN Tile_X2Y0_S4END[9]
    DIRECTION INPUT ;
    USE SIGNAL ;
    ANTENNAGATEAREA 0.426400 ;
    ANTENNADIFFAREA 4.030800 ;
    PORT
      LAYER Metal2 ;
        RECT 715.480 74.780 715.880 75.180 ;
    END
  END Tile_X2Y0_S4END[9]
  PIN Tile_X2Y0_SS4END[0]
    DIRECTION INPUT ;
    USE SIGNAL ;
    ANTENNAGATEAREA 0.426400 ;
    ANTENNADIFFAREA 4.030800 ;
    PORT
      LAYER Metal2 ;
        RECT 732.760 74.780 733.160 75.180 ;
    END
  END Tile_X2Y0_SS4END[0]
  PIN Tile_X2Y0_SS4END[10]
    DIRECTION INPUT ;
    USE SIGNAL ;
    ANTENNAGATEAREA 0.426400 ;
    ANTENNADIFFAREA 4.030800 ;
    PORT
      LAYER Metal2 ;
        RECT 751.960 74.780 752.360 75.180 ;
    END
  END Tile_X2Y0_SS4END[10]
  PIN Tile_X2Y0_SS4END[11]
    DIRECTION INPUT ;
    USE SIGNAL ;
    ANTENNAGATEAREA 0.426400 ;
    ANTENNADIFFAREA 4.030800 ;
    PORT
      LAYER Metal2 ;
        RECT 753.880 74.780 754.280 75.180 ;
    END
  END Tile_X2Y0_SS4END[11]
  PIN Tile_X2Y0_SS4END[12]
    DIRECTION INPUT ;
    USE SIGNAL ;
    ANTENNAGATEAREA 0.426400 ;
    ANTENNADIFFAREA 4.030800 ;
    PORT
      LAYER Metal2 ;
        RECT 755.800 74.780 756.200 75.180 ;
    END
  END Tile_X2Y0_SS4END[12]
  PIN Tile_X2Y0_SS4END[13]
    DIRECTION INPUT ;
    USE SIGNAL ;
    ANTENNAGATEAREA 0.426400 ;
    ANTENNADIFFAREA 4.030800 ;
    PORT
      LAYER Metal2 ;
        RECT 757.720 74.780 758.120 75.180 ;
    END
  END Tile_X2Y0_SS4END[13]
  PIN Tile_X2Y0_SS4END[14]
    DIRECTION INPUT ;
    USE SIGNAL ;
    ANTENNAGATEAREA 0.426400 ;
    ANTENNADIFFAREA 4.030800 ;
    PORT
      LAYER Metal2 ;
        RECT 759.640 74.780 760.040 75.180 ;
    END
  END Tile_X2Y0_SS4END[14]
  PIN Tile_X2Y0_SS4END[15]
    DIRECTION INPUT ;
    USE SIGNAL ;
    ANTENNAGATEAREA 0.426400 ;
    ANTENNADIFFAREA 4.030800 ;
    PORT
      LAYER Metal2 ;
        RECT 761.560 74.780 761.960 75.180 ;
    END
  END Tile_X2Y0_SS4END[15]
  PIN Tile_X2Y0_SS4END[1]
    DIRECTION INPUT ;
    USE SIGNAL ;
    ANTENNAGATEAREA 0.426400 ;
    ANTENNADIFFAREA 4.030800 ;
    PORT
      LAYER Metal2 ;
        RECT 734.680 74.780 735.080 75.180 ;
    END
  END Tile_X2Y0_SS4END[1]
  PIN Tile_X2Y0_SS4END[2]
    DIRECTION INPUT ;
    USE SIGNAL ;
    ANTENNAGATEAREA 0.426400 ;
    ANTENNADIFFAREA 4.030800 ;
    PORT
      LAYER Metal2 ;
        RECT 736.600 74.780 737.000 75.180 ;
    END
  END Tile_X2Y0_SS4END[2]
  PIN Tile_X2Y0_SS4END[3]
    DIRECTION INPUT ;
    USE SIGNAL ;
    ANTENNAGATEAREA 0.426400 ;
    ANTENNADIFFAREA 4.030800 ;
    PORT
      LAYER Metal2 ;
        RECT 738.520 74.780 738.920 75.180 ;
    END
  END Tile_X2Y0_SS4END[3]
  PIN Tile_X2Y0_SS4END[4]
    DIRECTION INPUT ;
    USE SIGNAL ;
    ANTENNAGATEAREA 0.426400 ;
    ANTENNADIFFAREA 4.030800 ;
    PORT
      LAYER Metal2 ;
        RECT 740.440 74.780 740.840 75.180 ;
    END
  END Tile_X2Y0_SS4END[4]
  PIN Tile_X2Y0_SS4END[5]
    DIRECTION INPUT ;
    USE SIGNAL ;
    ANTENNAGATEAREA 0.426400 ;
    ANTENNADIFFAREA 4.030800 ;
    PORT
      LAYER Metal2 ;
        RECT 742.360 74.780 742.760 75.180 ;
    END
  END Tile_X2Y0_SS4END[5]
  PIN Tile_X2Y0_SS4END[6]
    DIRECTION INPUT ;
    USE SIGNAL ;
    ANTENNAGATEAREA 0.426400 ;
    ANTENNADIFFAREA 4.030800 ;
    PORT
      LAYER Metal2 ;
        RECT 744.280 74.780 744.680 75.180 ;
    END
  END Tile_X2Y0_SS4END[6]
  PIN Tile_X2Y0_SS4END[7]
    DIRECTION INPUT ;
    USE SIGNAL ;
    ANTENNAGATEAREA 0.426400 ;
    ANTENNADIFFAREA 4.030800 ;
    PORT
      LAYER Metal2 ;
        RECT 746.200 74.780 746.600 75.180 ;
    END
  END Tile_X2Y0_SS4END[7]
  PIN Tile_X2Y0_SS4END[8]
    DIRECTION INPUT ;
    USE SIGNAL ;
    ANTENNAGATEAREA 0.426400 ;
    ANTENNADIFFAREA 4.030800 ;
    PORT
      LAYER Metal2 ;
        RECT 748.120 74.780 748.520 75.180 ;
    END
  END Tile_X2Y0_SS4END[8]
  PIN Tile_X2Y0_SS4END[9]
    DIRECTION INPUT ;
    USE SIGNAL ;
    ANTENNAGATEAREA 0.426400 ;
    ANTENNADIFFAREA 4.030800 ;
    PORT
      LAYER Metal2 ;
        RECT 750.040 74.780 750.440 75.180 ;
    END
  END Tile_X2Y0_SS4END[9]
  PIN Tile_X3Y0_Co
    DIRECTION OUTPUT ;
    USE SIGNAL ;
    ANTENNADIFFAREA 2.314600 ;
    PORT
      LAYER Metal2 ;
        RECT 1036.600 74.780 1037.000 75.180 ;
    END
  END Tile_X3Y0_Co
  PIN Tile_X3Y0_FrameStrobe[0]
    DIRECTION INPUT ;
    USE SIGNAL ;
    ANTENNAGATEAREA 11.745500 ;
    ANTENNADIFFAREA 66.508202 ;
    PORT
      LAYER Metal2 ;
        RECT 818.680 0.000 819.080 0.400 ;
    END
  END Tile_X3Y0_FrameStrobe[0]
  PIN Tile_X3Y0_FrameStrobe[10]
    DIRECTION INPUT ;
    USE SIGNAL ;
    ANTENNAGATEAREA 0.180700 ;
    ANTENNADIFFAREA 2.015400 ;
    PORT
      LAYER Metal2 ;
        RECT 953.080 0.000 953.480 0.400 ;
    END
  END Tile_X3Y0_FrameStrobe[10]
  PIN Tile_X3Y0_FrameStrobe[11]
    DIRECTION INPUT ;
    USE SIGNAL ;
    ANTENNAGATEAREA 0.180700 ;
    ANTENNADIFFAREA 2.015400 ;
    PORT
      LAYER Metal2 ;
        RECT 966.520 0.000 966.920 0.400 ;
    END
  END Tile_X3Y0_FrameStrobe[11]
  PIN Tile_X3Y0_FrameStrobe[12]
    DIRECTION INPUT ;
    USE SIGNAL ;
    ANTENNAGATEAREA 0.180700 ;
    ANTENNADIFFAREA 2.015400 ;
    PORT
      LAYER Metal2 ;
        RECT 979.960 0.000 980.360 0.400 ;
    END
  END Tile_X3Y0_FrameStrobe[12]
  PIN Tile_X3Y0_FrameStrobe[13]
    DIRECTION INPUT ;
    USE SIGNAL ;
    ANTENNAGATEAREA 0.180700 ;
    ANTENNADIFFAREA 2.015400 ;
    PORT
      LAYER Metal2 ;
        RECT 993.400 0.000 993.800 0.400 ;
    END
  END Tile_X3Y0_FrameStrobe[13]
  PIN Tile_X3Y0_FrameStrobe[14]
    DIRECTION INPUT ;
    USE SIGNAL ;
    ANTENNAGATEAREA 0.180700 ;
    ANTENNADIFFAREA 2.015400 ;
    PORT
      LAYER Metal2 ;
        RECT 1006.840 0.000 1007.240 0.400 ;
    END
  END Tile_X3Y0_FrameStrobe[14]
  PIN Tile_X3Y0_FrameStrobe[15]
    DIRECTION INPUT ;
    USE SIGNAL ;
    ANTENNAGATEAREA 0.180700 ;
    ANTENNADIFFAREA 2.015400 ;
    PORT
      LAYER Metal2 ;
        RECT 1020.280 0.000 1020.680 0.400 ;
    END
  END Tile_X3Y0_FrameStrobe[15]
  PIN Tile_X3Y0_FrameStrobe[16]
    DIRECTION INPUT ;
    USE SIGNAL ;
    ANTENNAGATEAREA 0.180700 ;
    ANTENNADIFFAREA 2.015400 ;
    PORT
      LAYER Metal2 ;
        RECT 1033.720 0.000 1034.120 0.400 ;
    END
  END Tile_X3Y0_FrameStrobe[16]
  PIN Tile_X3Y0_FrameStrobe[17]
    DIRECTION INPUT ;
    USE SIGNAL ;
    ANTENNAGATEAREA 0.180700 ;
    ANTENNADIFFAREA 2.015400 ;
    PORT
      LAYER Metal2 ;
        RECT 1047.160 0.000 1047.560 0.400 ;
    END
  END Tile_X3Y0_FrameStrobe[17]
  PIN Tile_X3Y0_FrameStrobe[18]
    DIRECTION INPUT ;
    USE SIGNAL ;
    ANTENNAGATEAREA 0.180700 ;
    ANTENNADIFFAREA 2.015400 ;
    PORT
      LAYER Metal2 ;
        RECT 1060.600 0.000 1061.000 0.400 ;
    END
  END Tile_X3Y0_FrameStrobe[18]
  PIN Tile_X3Y0_FrameStrobe[19]
    DIRECTION INPUT ;
    USE SIGNAL ;
    ANTENNAGATEAREA 0.180700 ;
    ANTENNADIFFAREA 2.015400 ;
    PORT
      LAYER Metal2 ;
        RECT 1074.040 0.000 1074.440 0.400 ;
    END
  END Tile_X3Y0_FrameStrobe[19]
  PIN Tile_X3Y0_FrameStrobe[1]
    DIRECTION INPUT ;
    USE SIGNAL ;
    ANTENNAGATEAREA 11.745500 ;
    ANTENNADIFFAREA 66.508202 ;
    PORT
      LAYER Metal2 ;
        RECT 832.120 0.000 832.520 0.400 ;
    END
  END Tile_X3Y0_FrameStrobe[1]
  PIN Tile_X3Y0_FrameStrobe[2]
    DIRECTION INPUT ;
    USE SIGNAL ;
    ANTENNAGATEAREA 11.745500 ;
    ANTENNADIFFAREA 66.508202 ;
    PORT
      LAYER Metal2 ;
        RECT 845.560 0.000 845.960 0.400 ;
    END
  END Tile_X3Y0_FrameStrobe[2]
  PIN Tile_X3Y0_FrameStrobe[3]
    DIRECTION INPUT ;
    USE SIGNAL ;
    ANTENNAGATEAREA 0.180700 ;
    ANTENNADIFFAREA 2.015400 ;
    PORT
      LAYER Metal2 ;
        RECT 859.000 0.000 859.400 0.400 ;
    END
  END Tile_X3Y0_FrameStrobe[3]
  PIN Tile_X3Y0_FrameStrobe[4]
    DIRECTION INPUT ;
    USE SIGNAL ;
    ANTENNAGATEAREA 0.180700 ;
    ANTENNADIFFAREA 2.015400 ;
    PORT
      LAYER Metal2 ;
        RECT 872.440 0.000 872.840 0.400 ;
    END
  END Tile_X3Y0_FrameStrobe[4]
  PIN Tile_X3Y0_FrameStrobe[5]
    DIRECTION INPUT ;
    USE SIGNAL ;
    ANTENNAGATEAREA 0.180700 ;
    ANTENNADIFFAREA 2.015400 ;
    PORT
      LAYER Metal2 ;
        RECT 885.880 0.000 886.280 0.400 ;
    END
  END Tile_X3Y0_FrameStrobe[5]
  PIN Tile_X3Y0_FrameStrobe[6]
    DIRECTION INPUT ;
    USE SIGNAL ;
    ANTENNAGATEAREA 0.180700 ;
    ANTENNADIFFAREA 2.015400 ;
    PORT
      LAYER Metal2 ;
        RECT 899.320 0.000 899.720 0.400 ;
    END
  END Tile_X3Y0_FrameStrobe[6]
  PIN Tile_X3Y0_FrameStrobe[7]
    DIRECTION INPUT ;
    USE SIGNAL ;
    ANTENNAGATEAREA 0.180700 ;
    ANTENNADIFFAREA 2.015400 ;
    PORT
      LAYER Metal2 ;
        RECT 912.760 0.000 913.160 0.400 ;
    END
  END Tile_X3Y0_FrameStrobe[7]
  PIN Tile_X3Y0_FrameStrobe[8]
    DIRECTION INPUT ;
    USE SIGNAL ;
    ANTENNAGATEAREA 0.180700 ;
    ANTENNADIFFAREA 2.015400 ;
    PORT
      LAYER Metal2 ;
        RECT 926.200 0.000 926.600 0.400 ;
    END
  END Tile_X3Y0_FrameStrobe[8]
  PIN Tile_X3Y0_FrameStrobe[9]
    DIRECTION INPUT ;
    USE SIGNAL ;
    ANTENNAGATEAREA 0.180700 ;
    ANTENNADIFFAREA 2.015400 ;
    PORT
      LAYER Metal2 ;
        RECT 939.640 0.000 940.040 0.400 ;
    END
  END Tile_X3Y0_FrameStrobe[9]
  PIN Tile_X3Y0_FrameStrobe_O[0]
    DIRECTION OUTPUT ;
    USE SIGNAL ;
    ANTENNADIFFAREA 2.724000 ;
    PORT
      LAYER Metal2 ;
        RECT 1041.400 74.780 1041.800 75.180 ;
    END
  END Tile_X3Y0_FrameStrobe_O[0]
  PIN Tile_X3Y0_FrameStrobe_O[10]
    DIRECTION OUTPUT ;
    USE SIGNAL ;
    ANTENNADIFFAREA 2.724000 ;
    PORT
      LAYER Metal2 ;
        RECT 1060.600 74.780 1061.000 75.180 ;
    END
  END Tile_X3Y0_FrameStrobe_O[10]
  PIN Tile_X3Y0_FrameStrobe_O[11]
    DIRECTION OUTPUT ;
    USE SIGNAL ;
    ANTENNADIFFAREA 2.724000 ;
    PORT
      LAYER Metal2 ;
        RECT 1062.520 74.780 1062.920 75.180 ;
    END
  END Tile_X3Y0_FrameStrobe_O[11]
  PIN Tile_X3Y0_FrameStrobe_O[12]
    DIRECTION OUTPUT ;
    USE SIGNAL ;
    ANTENNADIFFAREA 2.724000 ;
    PORT
      LAYER Metal2 ;
        RECT 1064.440 74.780 1064.840 75.180 ;
    END
  END Tile_X3Y0_FrameStrobe_O[12]
  PIN Tile_X3Y0_FrameStrobe_O[13]
    DIRECTION OUTPUT ;
    USE SIGNAL ;
    ANTENNADIFFAREA 2.724000 ;
    PORT
      LAYER Metal2 ;
        RECT 1066.360 74.780 1066.760 75.180 ;
    END
  END Tile_X3Y0_FrameStrobe_O[13]
  PIN Tile_X3Y0_FrameStrobe_O[14]
    DIRECTION OUTPUT ;
    USE SIGNAL ;
    ANTENNADIFFAREA 2.724000 ;
    PORT
      LAYER Metal2 ;
        RECT 1068.280 74.780 1068.680 75.180 ;
    END
  END Tile_X3Y0_FrameStrobe_O[14]
  PIN Tile_X3Y0_FrameStrobe_O[15]
    DIRECTION OUTPUT ;
    USE SIGNAL ;
    ANTENNADIFFAREA 2.724000 ;
    PORT
      LAYER Metal2 ;
        RECT 1070.200 74.780 1070.600 75.180 ;
    END
  END Tile_X3Y0_FrameStrobe_O[15]
  PIN Tile_X3Y0_FrameStrobe_O[16]
    DIRECTION OUTPUT ;
    USE SIGNAL ;
    ANTENNADIFFAREA 2.724000 ;
    PORT
      LAYER Metal2 ;
        RECT 1072.120 74.780 1072.520 75.180 ;
    END
  END Tile_X3Y0_FrameStrobe_O[16]
  PIN Tile_X3Y0_FrameStrobe_O[17]
    DIRECTION OUTPUT ;
    USE SIGNAL ;
    ANTENNADIFFAREA 2.724000 ;
    PORT
      LAYER Metal2 ;
        RECT 1074.040 74.780 1074.440 75.180 ;
    END
  END Tile_X3Y0_FrameStrobe_O[17]
  PIN Tile_X3Y0_FrameStrobe_O[18]
    DIRECTION OUTPUT ;
    USE SIGNAL ;
    ANTENNADIFFAREA 2.724000 ;
    PORT
      LAYER Metal2 ;
        RECT 1075.960 74.780 1076.360 75.180 ;
    END
  END Tile_X3Y0_FrameStrobe_O[18]
  PIN Tile_X3Y0_FrameStrobe_O[19]
    DIRECTION OUTPUT ;
    USE SIGNAL ;
    ANTENNADIFFAREA 2.724000 ;
    PORT
      LAYER Metal2 ;
        RECT 1077.880 74.780 1078.280 75.180 ;
    END
  END Tile_X3Y0_FrameStrobe_O[19]
  PIN Tile_X3Y0_FrameStrobe_O[1]
    DIRECTION OUTPUT ;
    USE SIGNAL ;
    ANTENNADIFFAREA 2.724000 ;
    PORT
      LAYER Metal2 ;
        RECT 1043.320 74.780 1043.720 75.180 ;
    END
  END Tile_X3Y0_FrameStrobe_O[1]
  PIN Tile_X3Y0_FrameStrobe_O[2]
    DIRECTION OUTPUT ;
    USE SIGNAL ;
    ANTENNADIFFAREA 2.724000 ;
    PORT
      LAYER Metal2 ;
        RECT 1045.240 74.780 1045.640 75.180 ;
    END
  END Tile_X3Y0_FrameStrobe_O[2]
  PIN Tile_X3Y0_FrameStrobe_O[3]
    DIRECTION OUTPUT ;
    USE SIGNAL ;
    ANTENNADIFFAREA 2.724000 ;
    PORT
      LAYER Metal2 ;
        RECT 1047.160 74.780 1047.560 75.180 ;
    END
  END Tile_X3Y0_FrameStrobe_O[3]
  PIN Tile_X3Y0_FrameStrobe_O[4]
    DIRECTION OUTPUT ;
    USE SIGNAL ;
    ANTENNADIFFAREA 2.724000 ;
    PORT
      LAYER Metal2 ;
        RECT 1049.080 74.780 1049.480 75.180 ;
    END
  END Tile_X3Y0_FrameStrobe_O[4]
  PIN Tile_X3Y0_FrameStrobe_O[5]
    DIRECTION OUTPUT ;
    USE SIGNAL ;
    ANTENNADIFFAREA 2.724000 ;
    PORT
      LAYER Metal2 ;
        RECT 1051.000 74.780 1051.400 75.180 ;
    END
  END Tile_X3Y0_FrameStrobe_O[5]
  PIN Tile_X3Y0_FrameStrobe_O[6]
    DIRECTION OUTPUT ;
    USE SIGNAL ;
    ANTENNADIFFAREA 2.724000 ;
    PORT
      LAYER Metal2 ;
        RECT 1052.920 74.780 1053.320 75.180 ;
    END
  END Tile_X3Y0_FrameStrobe_O[6]
  PIN Tile_X3Y0_FrameStrobe_O[7]
    DIRECTION OUTPUT ;
    USE SIGNAL ;
    ANTENNADIFFAREA 2.724000 ;
    PORT
      LAYER Metal2 ;
        RECT 1054.840 74.780 1055.240 75.180 ;
    END
  END Tile_X3Y0_FrameStrobe_O[7]
  PIN Tile_X3Y0_FrameStrobe_O[8]
    DIRECTION OUTPUT ;
    USE SIGNAL ;
    ANTENNADIFFAREA 2.724000 ;
    PORT
      LAYER Metal2 ;
        RECT 1056.760 74.780 1057.160 75.180 ;
    END
  END Tile_X3Y0_FrameStrobe_O[8]
  PIN Tile_X3Y0_FrameStrobe_O[9]
    DIRECTION OUTPUT ;
    USE SIGNAL ;
    ANTENNADIFFAREA 2.724000 ;
    PORT
      LAYER Metal2 ;
        RECT 1058.680 74.780 1059.080 75.180 ;
    END
  END Tile_X3Y0_FrameStrobe_O[9]
  PIN Tile_X3Y0_N1BEG[0]
    DIRECTION OUTPUT ;
    USE SIGNAL ;
    ANTENNADIFFAREA 2.724000 ;
    PORT
      LAYER Metal2 ;
        RECT 812.920 74.780 813.320 75.180 ;
    END
  END Tile_X3Y0_N1BEG[0]
  PIN Tile_X3Y0_N1BEG[1]
    DIRECTION OUTPUT ;
    USE SIGNAL ;
    ANTENNADIFFAREA 2.724000 ;
    PORT
      LAYER Metal2 ;
        RECT 814.840 74.780 815.240 75.180 ;
    END
  END Tile_X3Y0_N1BEG[1]
  PIN Tile_X3Y0_N1BEG[2]
    DIRECTION OUTPUT ;
    USE SIGNAL ;
    ANTENNADIFFAREA 2.724000 ;
    PORT
      LAYER Metal2 ;
        RECT 816.760 74.780 817.160 75.180 ;
    END
  END Tile_X3Y0_N1BEG[2]
  PIN Tile_X3Y0_N1BEG[3]
    DIRECTION OUTPUT ;
    USE SIGNAL ;
    ANTENNADIFFAREA 2.724000 ;
    PORT
      LAYER Metal2 ;
        RECT 818.680 74.780 819.080 75.180 ;
    END
  END Tile_X3Y0_N1BEG[3]
  PIN Tile_X3Y0_N2BEG[0]
    DIRECTION OUTPUT ;
    USE SIGNAL ;
    ANTENNADIFFAREA 2.724000 ;
    PORT
      LAYER Metal2 ;
        RECT 821.560 74.780 821.960 75.180 ;
    END
  END Tile_X3Y0_N2BEG[0]
  PIN Tile_X3Y0_N2BEG[1]
    DIRECTION OUTPUT ;
    USE SIGNAL ;
    ANTENNADIFFAREA 2.724000 ;
    PORT
      LAYER Metal2 ;
        RECT 823.480 74.780 823.880 75.180 ;
    END
  END Tile_X3Y0_N2BEG[1]
  PIN Tile_X3Y0_N2BEG[2]
    DIRECTION OUTPUT ;
    USE SIGNAL ;
    ANTENNADIFFAREA 2.724000 ;
    PORT
      LAYER Metal2 ;
        RECT 825.400 74.780 825.800 75.180 ;
    END
  END Tile_X3Y0_N2BEG[2]
  PIN Tile_X3Y0_N2BEG[3]
    DIRECTION OUTPUT ;
    USE SIGNAL ;
    ANTENNADIFFAREA 2.724000 ;
    PORT
      LAYER Metal2 ;
        RECT 827.320 74.780 827.720 75.180 ;
    END
  END Tile_X3Y0_N2BEG[3]
  PIN Tile_X3Y0_N2BEG[4]
    DIRECTION OUTPUT ;
    USE SIGNAL ;
    ANTENNADIFFAREA 2.724000 ;
    PORT
      LAYER Metal2 ;
        RECT 829.240 74.780 829.640 75.180 ;
    END
  END Tile_X3Y0_N2BEG[4]
  PIN Tile_X3Y0_N2BEG[5]
    DIRECTION OUTPUT ;
    USE SIGNAL ;
    ANTENNADIFFAREA 2.724000 ;
    PORT
      LAYER Metal2 ;
        RECT 831.160 74.780 831.560 75.180 ;
    END
  END Tile_X3Y0_N2BEG[5]
  PIN Tile_X3Y0_N2BEG[6]
    DIRECTION OUTPUT ;
    USE SIGNAL ;
    ANTENNADIFFAREA 2.724000 ;
    PORT
      LAYER Metal2 ;
        RECT 833.080 74.780 833.480 75.180 ;
    END
  END Tile_X3Y0_N2BEG[6]
  PIN Tile_X3Y0_N2BEG[7]
    DIRECTION OUTPUT ;
    USE SIGNAL ;
    ANTENNADIFFAREA 2.724000 ;
    PORT
      LAYER Metal2 ;
        RECT 835.000 74.780 835.400 75.180 ;
    END
  END Tile_X3Y0_N2BEG[7]
  PIN Tile_X3Y0_N2BEGb[0]
    DIRECTION OUTPUT ;
    USE SIGNAL ;
    ANTENNADIFFAREA 2.724000 ;
    PORT
      LAYER Metal2 ;
        RECT 837.880 74.780 838.280 75.180 ;
    END
  END Tile_X3Y0_N2BEGb[0]
  PIN Tile_X3Y0_N2BEGb[1]
    DIRECTION OUTPUT ;
    USE SIGNAL ;
    ANTENNADIFFAREA 2.724000 ;
    PORT
      LAYER Metal2 ;
        RECT 839.800 74.780 840.200 75.180 ;
    END
  END Tile_X3Y0_N2BEGb[1]
  PIN Tile_X3Y0_N2BEGb[2]
    DIRECTION OUTPUT ;
    USE SIGNAL ;
    ANTENNADIFFAREA 2.724000 ;
    PORT
      LAYER Metal2 ;
        RECT 841.720 74.780 842.120 75.180 ;
    END
  END Tile_X3Y0_N2BEGb[2]
  PIN Tile_X3Y0_N2BEGb[3]
    DIRECTION OUTPUT ;
    USE SIGNAL ;
    ANTENNADIFFAREA 2.724000 ;
    PORT
      LAYER Metal2 ;
        RECT 843.640 74.780 844.040 75.180 ;
    END
  END Tile_X3Y0_N2BEGb[3]
  PIN Tile_X3Y0_N2BEGb[4]
    DIRECTION OUTPUT ;
    USE SIGNAL ;
    ANTENNADIFFAREA 2.724000 ;
    PORT
      LAYER Metal2 ;
        RECT 845.560 74.780 845.960 75.180 ;
    END
  END Tile_X3Y0_N2BEGb[4]
  PIN Tile_X3Y0_N2BEGb[5]
    DIRECTION OUTPUT ;
    USE SIGNAL ;
    ANTENNADIFFAREA 2.724000 ;
    PORT
      LAYER Metal2 ;
        RECT 847.480 74.780 847.880 75.180 ;
    END
  END Tile_X3Y0_N2BEGb[5]
  PIN Tile_X3Y0_N2BEGb[6]
    DIRECTION OUTPUT ;
    USE SIGNAL ;
    ANTENNADIFFAREA 2.724000 ;
    PORT
      LAYER Metal2 ;
        RECT 849.400 74.780 849.800 75.180 ;
    END
  END Tile_X3Y0_N2BEGb[6]
  PIN Tile_X3Y0_N2BEGb[7]
    DIRECTION OUTPUT ;
    USE SIGNAL ;
    ANTENNADIFFAREA 2.724000 ;
    PORT
      LAYER Metal2 ;
        RECT 851.320 74.780 851.720 75.180 ;
    END
  END Tile_X3Y0_N2BEGb[7]
  PIN Tile_X3Y0_N4BEG[0]
    DIRECTION OUTPUT ;
    USE SIGNAL ;
    ANTENNADIFFAREA 2.724000 ;
    PORT
      LAYER Metal2 ;
        RECT 856.120 74.780 856.520 75.180 ;
    END
  END Tile_X3Y0_N4BEG[0]
  PIN Tile_X3Y0_N4BEG[10]
    DIRECTION OUTPUT ;
    USE SIGNAL ;
    ANTENNADIFFAREA 2.724000 ;
    PORT
      LAYER Metal2 ;
        RECT 875.320 74.780 875.720 75.180 ;
    END
  END Tile_X3Y0_N4BEG[10]
  PIN Tile_X3Y0_N4BEG[11]
    DIRECTION OUTPUT ;
    USE SIGNAL ;
    ANTENNADIFFAREA 2.724000 ;
    PORT
      LAYER Metal2 ;
        RECT 877.240 74.780 877.640 75.180 ;
    END
  END Tile_X3Y0_N4BEG[11]
  PIN Tile_X3Y0_N4BEG[12]
    DIRECTION OUTPUT ;
    USE SIGNAL ;
    ANTENNADIFFAREA 2.724000 ;
    PORT
      LAYER Metal2 ;
        RECT 879.160 74.780 879.560 75.180 ;
    END
  END Tile_X3Y0_N4BEG[12]
  PIN Tile_X3Y0_N4BEG[13]
    DIRECTION OUTPUT ;
    USE SIGNAL ;
    ANTENNADIFFAREA 2.724000 ;
    PORT
      LAYER Metal2 ;
        RECT 881.080 74.780 881.480 75.180 ;
    END
  END Tile_X3Y0_N4BEG[13]
  PIN Tile_X3Y0_N4BEG[14]
    DIRECTION OUTPUT ;
    USE SIGNAL ;
    ANTENNADIFFAREA 2.724000 ;
    PORT
      LAYER Metal2 ;
        RECT 883.000 74.780 883.400 75.180 ;
    END
  END Tile_X3Y0_N4BEG[14]
  PIN Tile_X3Y0_N4BEG[15]
    DIRECTION OUTPUT ;
    USE SIGNAL ;
    ANTENNADIFFAREA 2.724000 ;
    PORT
      LAYER Metal2 ;
        RECT 884.920 74.780 885.320 75.180 ;
    END
  END Tile_X3Y0_N4BEG[15]
  PIN Tile_X3Y0_N4BEG[1]
    DIRECTION OUTPUT ;
    USE SIGNAL ;
    ANTENNADIFFAREA 2.724000 ;
    PORT
      LAYER Metal2 ;
        RECT 858.040 74.780 858.440 75.180 ;
    END
  END Tile_X3Y0_N4BEG[1]
  PIN Tile_X3Y0_N4BEG[2]
    DIRECTION OUTPUT ;
    USE SIGNAL ;
    ANTENNADIFFAREA 2.724000 ;
    PORT
      LAYER Metal2 ;
        RECT 859.960 74.780 860.360 75.180 ;
    END
  END Tile_X3Y0_N4BEG[2]
  PIN Tile_X3Y0_N4BEG[3]
    DIRECTION OUTPUT ;
    USE SIGNAL ;
    ANTENNADIFFAREA 2.724000 ;
    PORT
      LAYER Metal2 ;
        RECT 861.880 74.780 862.280 75.180 ;
    END
  END Tile_X3Y0_N4BEG[3]
  PIN Tile_X3Y0_N4BEG[4]
    DIRECTION OUTPUT ;
    USE SIGNAL ;
    ANTENNADIFFAREA 2.724000 ;
    PORT
      LAYER Metal2 ;
        RECT 863.800 74.780 864.200 75.180 ;
    END
  END Tile_X3Y0_N4BEG[4]
  PIN Tile_X3Y0_N4BEG[5]
    DIRECTION OUTPUT ;
    USE SIGNAL ;
    ANTENNADIFFAREA 2.724000 ;
    PORT
      LAYER Metal2 ;
        RECT 865.720 74.780 866.120 75.180 ;
    END
  END Tile_X3Y0_N4BEG[5]
  PIN Tile_X3Y0_N4BEG[6]
    DIRECTION OUTPUT ;
    USE SIGNAL ;
    ANTENNADIFFAREA 2.724000 ;
    PORT
      LAYER Metal2 ;
        RECT 867.640 74.780 868.040 75.180 ;
    END
  END Tile_X3Y0_N4BEG[6]
  PIN Tile_X3Y0_N4BEG[7]
    DIRECTION OUTPUT ;
    USE SIGNAL ;
    ANTENNADIFFAREA 2.724000 ;
    PORT
      LAYER Metal2 ;
        RECT 869.560 74.780 869.960 75.180 ;
    END
  END Tile_X3Y0_N4BEG[7]
  PIN Tile_X3Y0_N4BEG[8]
    DIRECTION OUTPUT ;
    USE SIGNAL ;
    ANTENNADIFFAREA 2.724000 ;
    PORT
      LAYER Metal2 ;
        RECT 871.480 74.780 871.880 75.180 ;
    END
  END Tile_X3Y0_N4BEG[8]
  PIN Tile_X3Y0_N4BEG[9]
    DIRECTION OUTPUT ;
    USE SIGNAL ;
    ANTENNADIFFAREA 2.724000 ;
    PORT
      LAYER Metal2 ;
        RECT 873.400 74.780 873.800 75.180 ;
    END
  END Tile_X3Y0_N4BEG[9]
  PIN Tile_X3Y0_NN4BEG[0]
    DIRECTION OUTPUT ;
    USE SIGNAL ;
    ANTENNADIFFAREA 2.724000 ;
    PORT
      LAYER Metal2 ;
        RECT 890.680 74.780 891.080 75.180 ;
    END
  END Tile_X3Y0_NN4BEG[0]
  PIN Tile_X3Y0_NN4BEG[10]
    DIRECTION OUTPUT ;
    USE SIGNAL ;
    ANTENNADIFFAREA 2.724000 ;
    PORT
      LAYER Metal2 ;
        RECT 909.880 74.780 910.280 75.180 ;
    END
  END Tile_X3Y0_NN4BEG[10]
  PIN Tile_X3Y0_NN4BEG[11]
    DIRECTION OUTPUT ;
    USE SIGNAL ;
    ANTENNADIFFAREA 2.724000 ;
    PORT
      LAYER Metal2 ;
        RECT 911.800 74.780 912.200 75.180 ;
    END
  END Tile_X3Y0_NN4BEG[11]
  PIN Tile_X3Y0_NN4BEG[12]
    DIRECTION OUTPUT ;
    USE SIGNAL ;
    ANTENNADIFFAREA 2.724000 ;
    PORT
      LAYER Metal2 ;
        RECT 913.720 74.780 914.120 75.180 ;
    END
  END Tile_X3Y0_NN4BEG[12]
  PIN Tile_X3Y0_NN4BEG[13]
    DIRECTION OUTPUT ;
    USE SIGNAL ;
    ANTENNADIFFAREA 2.724000 ;
    PORT
      LAYER Metal2 ;
        RECT 915.640 74.780 916.040 75.180 ;
    END
  END Tile_X3Y0_NN4BEG[13]
  PIN Tile_X3Y0_NN4BEG[14]
    DIRECTION OUTPUT ;
    USE SIGNAL ;
    ANTENNADIFFAREA 2.724000 ;
    PORT
      LAYER Metal2 ;
        RECT 917.560 74.780 917.960 75.180 ;
    END
  END Tile_X3Y0_NN4BEG[14]
  PIN Tile_X3Y0_NN4BEG[15]
    DIRECTION OUTPUT ;
    USE SIGNAL ;
    ANTENNADIFFAREA 2.724000 ;
    PORT
      LAYER Metal2 ;
        RECT 919.480 74.780 919.880 75.180 ;
    END
  END Tile_X3Y0_NN4BEG[15]
  PIN Tile_X3Y0_NN4BEG[1]
    DIRECTION OUTPUT ;
    USE SIGNAL ;
    ANTENNADIFFAREA 2.724000 ;
    PORT
      LAYER Metal2 ;
        RECT 892.600 74.780 893.000 75.180 ;
    END
  END Tile_X3Y0_NN4BEG[1]
  PIN Tile_X3Y0_NN4BEG[2]
    DIRECTION OUTPUT ;
    USE SIGNAL ;
    ANTENNADIFFAREA 2.724000 ;
    PORT
      LAYER Metal2 ;
        RECT 894.520 74.780 894.920 75.180 ;
    END
  END Tile_X3Y0_NN4BEG[2]
  PIN Tile_X3Y0_NN4BEG[3]
    DIRECTION OUTPUT ;
    USE SIGNAL ;
    ANTENNADIFFAREA 2.724000 ;
    PORT
      LAYER Metal2 ;
        RECT 896.440 74.780 896.840 75.180 ;
    END
  END Tile_X3Y0_NN4BEG[3]
  PIN Tile_X3Y0_NN4BEG[4]
    DIRECTION OUTPUT ;
    USE SIGNAL ;
    ANTENNADIFFAREA 2.724000 ;
    PORT
      LAYER Metal2 ;
        RECT 898.360 74.780 898.760 75.180 ;
    END
  END Tile_X3Y0_NN4BEG[4]
  PIN Tile_X3Y0_NN4BEG[5]
    DIRECTION OUTPUT ;
    USE SIGNAL ;
    ANTENNADIFFAREA 2.724000 ;
    PORT
      LAYER Metal2 ;
        RECT 900.280 74.780 900.680 75.180 ;
    END
  END Tile_X3Y0_NN4BEG[5]
  PIN Tile_X3Y0_NN4BEG[6]
    DIRECTION OUTPUT ;
    USE SIGNAL ;
    ANTENNADIFFAREA 2.724000 ;
    PORT
      LAYER Metal2 ;
        RECT 902.200 74.780 902.600 75.180 ;
    END
  END Tile_X3Y0_NN4BEG[6]
  PIN Tile_X3Y0_NN4BEG[7]
    DIRECTION OUTPUT ;
    USE SIGNAL ;
    ANTENNADIFFAREA 2.724000 ;
    PORT
      LAYER Metal2 ;
        RECT 904.120 74.780 904.520 75.180 ;
    END
  END Tile_X3Y0_NN4BEG[7]
  PIN Tile_X3Y0_NN4BEG[8]
    DIRECTION OUTPUT ;
    USE SIGNAL ;
    ANTENNADIFFAREA 2.724000 ;
    PORT
      LAYER Metal2 ;
        RECT 906.040 74.780 906.440 75.180 ;
    END
  END Tile_X3Y0_NN4BEG[8]
  PIN Tile_X3Y0_NN4BEG[9]
    DIRECTION OUTPUT ;
    USE SIGNAL ;
    ANTENNADIFFAREA 2.724000 ;
    PORT
      LAYER Metal2 ;
        RECT 907.960 74.780 908.360 75.180 ;
    END
  END Tile_X3Y0_NN4BEG[9]
  PIN Tile_X3Y0_S1END[0]
    DIRECTION INPUT ;
    USE SIGNAL ;
    ANTENNAGATEAREA 1.033500 ;
    ANTENNADIFFAREA 10.077000 ;
    PORT
      LAYER Metal2 ;
        RECT 924.280 74.780 924.680 75.180 ;
    END
  END Tile_X3Y0_S1END[0]
  PIN Tile_X3Y0_S1END[1]
    DIRECTION INPUT ;
    USE SIGNAL ;
    ANTENNAGATEAREA 1.033500 ;
    ANTENNADIFFAREA 10.077000 ;
    PORT
      LAYER Metal2 ;
        RECT 926.200 74.780 926.600 75.180 ;
    END
  END Tile_X3Y0_S1END[1]
  PIN Tile_X3Y0_S1END[2]
    DIRECTION INPUT ;
    USE SIGNAL ;
    ANTENNAGATEAREA 1.033500 ;
    ANTENNADIFFAREA 10.077000 ;
    PORT
      LAYER Metal2 ;
        RECT 928.120 74.780 928.520 75.180 ;
    END
  END Tile_X3Y0_S1END[2]
  PIN Tile_X3Y0_S1END[3]
    DIRECTION INPUT ;
    USE SIGNAL ;
    ANTENNAGATEAREA 1.033500 ;
    ANTENNADIFFAREA 10.077000 ;
    PORT
      LAYER Metal2 ;
        RECT 930.040 74.780 930.440 75.180 ;
    END
  END Tile_X3Y0_S1END[3]
  PIN Tile_X3Y0_S2END[0]
    DIRECTION INPUT ;
    USE SIGNAL ;
    ANTENNAGATEAREA 0.852800 ;
    ANTENNADIFFAREA 8.061600 ;
    PORT
      LAYER Metal2 ;
        RECT 950.200 74.780 950.600 75.180 ;
    END
  END Tile_X3Y0_S2END[0]
  PIN Tile_X3Y0_S2END[1]
    DIRECTION INPUT ;
    USE SIGNAL ;
    ANTENNAGATEAREA 0.852800 ;
    ANTENNADIFFAREA 8.061600 ;
    PORT
      LAYER Metal2 ;
        RECT 952.120 74.780 952.520 75.180 ;
    END
  END Tile_X3Y0_S2END[1]
  PIN Tile_X3Y0_S2END[2]
    DIRECTION INPUT ;
    USE SIGNAL ;
    ANTENNAGATEAREA 0.852800 ;
    ANTENNADIFFAREA 8.061600 ;
    PORT
      LAYER Metal2 ;
        RECT 954.040 74.780 954.440 75.180 ;
    END
  END Tile_X3Y0_S2END[2]
  PIN Tile_X3Y0_S2END[3]
    DIRECTION INPUT ;
    USE SIGNAL ;
    ANTENNAGATEAREA 0.852800 ;
    ANTENNADIFFAREA 8.061600 ;
    PORT
      LAYER Metal2 ;
        RECT 955.960 74.780 956.360 75.180 ;
    END
  END Tile_X3Y0_S2END[3]
  PIN Tile_X3Y0_S2END[4]
    DIRECTION INPUT ;
    USE SIGNAL ;
    ANTENNAGATEAREA 0.852800 ;
    ANTENNADIFFAREA 8.061600 ;
    PORT
      LAYER Metal2 ;
        RECT 957.880 74.780 958.280 75.180 ;
    END
  END Tile_X3Y0_S2END[4]
  PIN Tile_X3Y0_S2END[5]
    DIRECTION INPUT ;
    USE SIGNAL ;
    ANTENNAGATEAREA 0.852800 ;
    ANTENNADIFFAREA 8.061600 ;
    PORT
      LAYER Metal2 ;
        RECT 959.800 74.780 960.200 75.180 ;
    END
  END Tile_X3Y0_S2END[5]
  PIN Tile_X3Y0_S2END[6]
    DIRECTION INPUT ;
    USE SIGNAL ;
    ANTENNAGATEAREA 0.852800 ;
    ANTENNADIFFAREA 8.061600 ;
    PORT
      LAYER Metal2 ;
        RECT 961.720 74.780 962.120 75.180 ;
    END
  END Tile_X3Y0_S2END[6]
  PIN Tile_X3Y0_S2END[7]
    DIRECTION INPUT ;
    USE SIGNAL ;
    ANTENNAGATEAREA 0.852800 ;
    ANTENNADIFFAREA 8.061600 ;
    PORT
      LAYER Metal2 ;
        RECT 963.640 74.780 964.040 75.180 ;
    END
  END Tile_X3Y0_S2END[7]
  PIN Tile_X3Y0_S2MID[0]
    DIRECTION INPUT ;
    USE SIGNAL ;
    ANTENNAGATEAREA 1.246700 ;
    ANTENNADIFFAREA 12.092400 ;
    PORT
      LAYER Metal2 ;
        RECT 932.920 74.780 933.320 75.180 ;
    END
  END Tile_X3Y0_S2MID[0]
  PIN Tile_X3Y0_S2MID[1]
    DIRECTION INPUT ;
    USE SIGNAL ;
    ANTENNAGATEAREA 1.246700 ;
    ANTENNADIFFAREA 12.092400 ;
    PORT
      LAYER Metal2 ;
        RECT 934.840 74.780 935.240 75.180 ;
    END
  END Tile_X3Y0_S2MID[1]
  PIN Tile_X3Y0_S2MID[2]
    DIRECTION INPUT ;
    USE SIGNAL ;
    ANTENNAGATEAREA 1.246700 ;
    ANTENNADIFFAREA 12.092400 ;
    PORT
      LAYER Metal2 ;
        RECT 936.760 74.780 937.160 75.180 ;
    END
  END Tile_X3Y0_S2MID[2]
  PIN Tile_X3Y0_S2MID[3]
    DIRECTION INPUT ;
    USE SIGNAL ;
    ANTENNAGATEAREA 1.246700 ;
    ANTENNADIFFAREA 12.092400 ;
    PORT
      LAYER Metal2 ;
        RECT 938.680 74.780 939.080 75.180 ;
    END
  END Tile_X3Y0_S2MID[3]
  PIN Tile_X3Y0_S2MID[4]
    DIRECTION INPUT ;
    USE SIGNAL ;
    ANTENNAGATEAREA 1.246700 ;
    ANTENNADIFFAREA 12.092400 ;
    PORT
      LAYER Metal2 ;
        RECT 940.600 74.780 941.000 75.180 ;
    END
  END Tile_X3Y0_S2MID[4]
  PIN Tile_X3Y0_S2MID[5]
    DIRECTION INPUT ;
    USE SIGNAL ;
    ANTENNAGATEAREA 1.246700 ;
    ANTENNADIFFAREA 12.092400 ;
    PORT
      LAYER Metal2 ;
        RECT 942.520 74.780 942.920 75.180 ;
    END
  END Tile_X3Y0_S2MID[5]
  PIN Tile_X3Y0_S2MID[6]
    DIRECTION INPUT ;
    USE SIGNAL ;
    ANTENNAGATEAREA 1.246700 ;
    ANTENNADIFFAREA 12.092400 ;
    PORT
      LAYER Metal2 ;
        RECT 944.440 74.780 944.840 75.180 ;
    END
  END Tile_X3Y0_S2MID[6]
  PIN Tile_X3Y0_S2MID[7]
    DIRECTION INPUT ;
    USE SIGNAL ;
    ANTENNAGATEAREA 1.246700 ;
    ANTENNADIFFAREA 12.092400 ;
    PORT
      LAYER Metal2 ;
        RECT 946.360 74.780 946.760 75.180 ;
    END
  END Tile_X3Y0_S2MID[7]
  PIN Tile_X3Y0_S4END[0]
    DIRECTION INPUT ;
    USE SIGNAL ;
    ANTENNAGATEAREA 0.426400 ;
    ANTENNADIFFAREA 4.030800 ;
    PORT
      LAYER Metal2 ;
        RECT 968.440 74.780 968.840 75.180 ;
    END
  END Tile_X3Y0_S4END[0]
  PIN Tile_X3Y0_S4END[10]
    DIRECTION INPUT ;
    USE SIGNAL ;
    ANTENNAGATEAREA 0.426400 ;
    ANTENNADIFFAREA 4.030800 ;
    PORT
      LAYER Metal2 ;
        RECT 987.640 74.780 988.040 75.180 ;
    END
  END Tile_X3Y0_S4END[10]
  PIN Tile_X3Y0_S4END[11]
    DIRECTION INPUT ;
    USE SIGNAL ;
    ANTENNAGATEAREA 0.426400 ;
    ANTENNADIFFAREA 4.030800 ;
    PORT
      LAYER Metal2 ;
        RECT 989.560 74.780 989.960 75.180 ;
    END
  END Tile_X3Y0_S4END[11]
  PIN Tile_X3Y0_S4END[12]
    DIRECTION INPUT ;
    USE SIGNAL ;
    ANTENNAGATEAREA 0.426400 ;
    ANTENNADIFFAREA 4.030800 ;
    PORT
      LAYER Metal2 ;
        RECT 991.480 74.780 991.880 75.180 ;
    END
  END Tile_X3Y0_S4END[12]
  PIN Tile_X3Y0_S4END[13]
    DIRECTION INPUT ;
    USE SIGNAL ;
    ANTENNAGATEAREA 0.426400 ;
    ANTENNADIFFAREA 4.030800 ;
    PORT
      LAYER Metal2 ;
        RECT 993.400 74.780 993.800 75.180 ;
    END
  END Tile_X3Y0_S4END[13]
  PIN Tile_X3Y0_S4END[14]
    DIRECTION INPUT ;
    USE SIGNAL ;
    ANTENNAGATEAREA 0.426400 ;
    ANTENNADIFFAREA 4.030800 ;
    PORT
      LAYER Metal2 ;
        RECT 995.320 74.780 995.720 75.180 ;
    END
  END Tile_X3Y0_S4END[14]
  PIN Tile_X3Y0_S4END[15]
    DIRECTION INPUT ;
    USE SIGNAL ;
    ANTENNAGATEAREA 0.426400 ;
    ANTENNADIFFAREA 4.030800 ;
    PORT
      LAYER Metal2 ;
        RECT 997.240 74.780 997.640 75.180 ;
    END
  END Tile_X3Y0_S4END[15]
  PIN Tile_X3Y0_S4END[1]
    DIRECTION INPUT ;
    USE SIGNAL ;
    ANTENNAGATEAREA 0.426400 ;
    ANTENNADIFFAREA 4.030800 ;
    PORT
      LAYER Metal2 ;
        RECT 970.360 74.780 970.760 75.180 ;
    END
  END Tile_X3Y0_S4END[1]
  PIN Tile_X3Y0_S4END[2]
    DIRECTION INPUT ;
    USE SIGNAL ;
    ANTENNAGATEAREA 0.426400 ;
    ANTENNADIFFAREA 4.030800 ;
    PORT
      LAYER Metal2 ;
        RECT 972.280 74.780 972.680 75.180 ;
    END
  END Tile_X3Y0_S4END[2]
  PIN Tile_X3Y0_S4END[3]
    DIRECTION INPUT ;
    USE SIGNAL ;
    ANTENNAGATEAREA 0.426400 ;
    ANTENNADIFFAREA 4.030800 ;
    PORT
      LAYER Metal2 ;
        RECT 974.200 74.780 974.600 75.180 ;
    END
  END Tile_X3Y0_S4END[3]
  PIN Tile_X3Y0_S4END[4]
    DIRECTION INPUT ;
    USE SIGNAL ;
    ANTENNAGATEAREA 0.426400 ;
    ANTENNADIFFAREA 4.030800 ;
    PORT
      LAYER Metal2 ;
        RECT 976.120 74.780 976.520 75.180 ;
    END
  END Tile_X3Y0_S4END[4]
  PIN Tile_X3Y0_S4END[5]
    DIRECTION INPUT ;
    USE SIGNAL ;
    ANTENNAGATEAREA 0.426400 ;
    ANTENNADIFFAREA 4.030800 ;
    PORT
      LAYER Metal2 ;
        RECT 978.040 74.780 978.440 75.180 ;
    END
  END Tile_X3Y0_S4END[5]
  PIN Tile_X3Y0_S4END[6]
    DIRECTION INPUT ;
    USE SIGNAL ;
    ANTENNAGATEAREA 0.426400 ;
    ANTENNADIFFAREA 4.030800 ;
    PORT
      LAYER Metal2 ;
        RECT 979.960 74.780 980.360 75.180 ;
    END
  END Tile_X3Y0_S4END[6]
  PIN Tile_X3Y0_S4END[7]
    DIRECTION INPUT ;
    USE SIGNAL ;
    ANTENNAGATEAREA 0.426400 ;
    ANTENNADIFFAREA 4.030800 ;
    PORT
      LAYER Metal2 ;
        RECT 981.880 74.780 982.280 75.180 ;
    END
  END Tile_X3Y0_S4END[7]
  PIN Tile_X3Y0_S4END[8]
    DIRECTION INPUT ;
    USE SIGNAL ;
    ANTENNAGATEAREA 0.426400 ;
    ANTENNADIFFAREA 4.030800 ;
    PORT
      LAYER Metal2 ;
        RECT 983.800 74.780 984.200 75.180 ;
    END
  END Tile_X3Y0_S4END[8]
  PIN Tile_X3Y0_S4END[9]
    DIRECTION INPUT ;
    USE SIGNAL ;
    ANTENNAGATEAREA 0.426400 ;
    ANTENNADIFFAREA 4.030800 ;
    PORT
      LAYER Metal2 ;
        RECT 985.720 74.780 986.120 75.180 ;
    END
  END Tile_X3Y0_S4END[9]
  PIN Tile_X3Y0_SS4END[0]
    DIRECTION INPUT ;
    USE SIGNAL ;
    ANTENNAGATEAREA 0.426400 ;
    ANTENNADIFFAREA 4.030800 ;
    PORT
      LAYER Metal2 ;
        RECT 1003.000 74.780 1003.400 75.180 ;
    END
  END Tile_X3Y0_SS4END[0]
  PIN Tile_X3Y0_SS4END[10]
    DIRECTION INPUT ;
    USE SIGNAL ;
    ANTENNAGATEAREA 0.426400 ;
    ANTENNADIFFAREA 4.030800 ;
    PORT
      LAYER Metal2 ;
        RECT 1022.200 74.780 1022.600 75.180 ;
    END
  END Tile_X3Y0_SS4END[10]
  PIN Tile_X3Y0_SS4END[11]
    DIRECTION INPUT ;
    USE SIGNAL ;
    ANTENNAGATEAREA 0.426400 ;
    ANTENNADIFFAREA 4.030800 ;
    PORT
      LAYER Metal2 ;
        RECT 1024.120 74.780 1024.520 75.180 ;
    END
  END Tile_X3Y0_SS4END[11]
  PIN Tile_X3Y0_SS4END[12]
    DIRECTION INPUT ;
    USE SIGNAL ;
    ANTENNAGATEAREA 0.426400 ;
    ANTENNADIFFAREA 4.030800 ;
    PORT
      LAYER Metal2 ;
        RECT 1026.040 74.780 1026.440 75.180 ;
    END
  END Tile_X3Y0_SS4END[12]
  PIN Tile_X3Y0_SS4END[13]
    DIRECTION INPUT ;
    USE SIGNAL ;
    ANTENNAGATEAREA 0.426400 ;
    ANTENNADIFFAREA 4.030800 ;
    PORT
      LAYER Metal2 ;
        RECT 1027.960 74.780 1028.360 75.180 ;
    END
  END Tile_X3Y0_SS4END[13]
  PIN Tile_X3Y0_SS4END[14]
    DIRECTION INPUT ;
    USE SIGNAL ;
    ANTENNAGATEAREA 0.426400 ;
    ANTENNADIFFAREA 4.030800 ;
    PORT
      LAYER Metal2 ;
        RECT 1029.880 74.780 1030.280 75.180 ;
    END
  END Tile_X3Y0_SS4END[14]
  PIN Tile_X3Y0_SS4END[15]
    DIRECTION INPUT ;
    USE SIGNAL ;
    ANTENNAGATEAREA 0.426400 ;
    ANTENNADIFFAREA 4.030800 ;
    PORT
      LAYER Metal2 ;
        RECT 1031.800 74.780 1032.200 75.180 ;
    END
  END Tile_X3Y0_SS4END[15]
  PIN Tile_X3Y0_SS4END[1]
    DIRECTION INPUT ;
    USE SIGNAL ;
    ANTENNAGATEAREA 0.426400 ;
    ANTENNADIFFAREA 4.030800 ;
    PORT
      LAYER Metal2 ;
        RECT 1004.920 74.780 1005.320 75.180 ;
    END
  END Tile_X3Y0_SS4END[1]
  PIN Tile_X3Y0_SS4END[2]
    DIRECTION INPUT ;
    USE SIGNAL ;
    ANTENNAGATEAREA 0.426400 ;
    ANTENNADIFFAREA 4.030800 ;
    PORT
      LAYER Metal2 ;
        RECT 1006.840 74.780 1007.240 75.180 ;
    END
  END Tile_X3Y0_SS4END[2]
  PIN Tile_X3Y0_SS4END[3]
    DIRECTION INPUT ;
    USE SIGNAL ;
    ANTENNAGATEAREA 0.426400 ;
    ANTENNADIFFAREA 4.030800 ;
    PORT
      LAYER Metal2 ;
        RECT 1008.760 74.780 1009.160 75.180 ;
    END
  END Tile_X3Y0_SS4END[3]
  PIN Tile_X3Y0_SS4END[4]
    DIRECTION INPUT ;
    USE SIGNAL ;
    ANTENNAGATEAREA 0.426400 ;
    ANTENNADIFFAREA 4.030800 ;
    PORT
      LAYER Metal2 ;
        RECT 1010.680 74.780 1011.080 75.180 ;
    END
  END Tile_X3Y0_SS4END[4]
  PIN Tile_X3Y0_SS4END[5]
    DIRECTION INPUT ;
    USE SIGNAL ;
    ANTENNAGATEAREA 0.426400 ;
    ANTENNADIFFAREA 4.030800 ;
    PORT
      LAYER Metal2 ;
        RECT 1012.600 74.780 1013.000 75.180 ;
    END
  END Tile_X3Y0_SS4END[5]
  PIN Tile_X3Y0_SS4END[6]
    DIRECTION INPUT ;
    USE SIGNAL ;
    ANTENNAGATEAREA 0.426400 ;
    ANTENNADIFFAREA 4.030800 ;
    PORT
      LAYER Metal2 ;
        RECT 1014.520 74.780 1014.920 75.180 ;
    END
  END Tile_X3Y0_SS4END[6]
  PIN Tile_X3Y0_SS4END[7]
    DIRECTION INPUT ;
    USE SIGNAL ;
    ANTENNAGATEAREA 0.426400 ;
    ANTENNADIFFAREA 4.030800 ;
    PORT
      LAYER Metal2 ;
        RECT 1016.440 74.780 1016.840 75.180 ;
    END
  END Tile_X3Y0_SS4END[7]
  PIN Tile_X3Y0_SS4END[8]
    DIRECTION INPUT ;
    USE SIGNAL ;
    ANTENNAGATEAREA 0.426400 ;
    ANTENNADIFFAREA 4.030800 ;
    PORT
      LAYER Metal2 ;
        RECT 1018.360 74.780 1018.760 75.180 ;
    END
  END Tile_X3Y0_SS4END[8]
  PIN Tile_X3Y0_SS4END[9]
    DIRECTION INPUT ;
    USE SIGNAL ;
    ANTENNAGATEAREA 0.426400 ;
    ANTENNADIFFAREA 4.030800 ;
    PORT
      LAYER Metal2 ;
        RECT 1020.280 74.780 1020.680 75.180 ;
    END
  END Tile_X3Y0_SS4END[9]
  PIN Tile_X4Y0_Co
    DIRECTION OUTPUT ;
    USE SIGNAL ;
    ANTENNADIFFAREA 2.314600 ;
    PORT
      LAYER Metal2 ;
        RECT 1306.840 74.780 1307.240 75.180 ;
    END
  END Tile_X4Y0_Co
  PIN Tile_X4Y0_FrameData_O[0]
    DIRECTION OUTPUT ;
    USE SIGNAL ;
    ANTENNADIFFAREA 2.724000 ;
    PORT
      LAYER Metal3 ;
        RECT 1350.800 12.820 1351.200 13.220 ;
    END
  END Tile_X4Y0_FrameData_O[0]
  PIN Tile_X4Y0_FrameData_O[10]
    DIRECTION OUTPUT ;
    USE SIGNAL ;
    ANTENNADIFFAREA 2.724000 ;
    PORT
      LAYER Metal3 ;
        RECT 1350.800 29.620 1351.200 30.020 ;
    END
  END Tile_X4Y0_FrameData_O[10]
  PIN Tile_X4Y0_FrameData_O[11]
    DIRECTION OUTPUT ;
    USE SIGNAL ;
    ANTENNADIFFAREA 2.724000 ;
    PORT
      LAYER Metal3 ;
        RECT 1350.800 31.300 1351.200 31.700 ;
    END
  END Tile_X4Y0_FrameData_O[11]
  PIN Tile_X4Y0_FrameData_O[12]
    DIRECTION OUTPUT ;
    USE SIGNAL ;
    ANTENNADIFFAREA 2.724000 ;
    PORT
      LAYER Metal3 ;
        RECT 1350.800 32.980 1351.200 33.380 ;
    END
  END Tile_X4Y0_FrameData_O[12]
  PIN Tile_X4Y0_FrameData_O[13]
    DIRECTION OUTPUT ;
    USE SIGNAL ;
    ANTENNADIFFAREA 2.724000 ;
    PORT
      LAYER Metal3 ;
        RECT 1350.800 34.660 1351.200 35.060 ;
    END
  END Tile_X4Y0_FrameData_O[13]
  PIN Tile_X4Y0_FrameData_O[14]
    DIRECTION OUTPUT ;
    USE SIGNAL ;
    ANTENNADIFFAREA 2.724000 ;
    PORT
      LAYER Metal3 ;
        RECT 1350.800 36.340 1351.200 36.740 ;
    END
  END Tile_X4Y0_FrameData_O[14]
  PIN Tile_X4Y0_FrameData_O[15]
    DIRECTION OUTPUT ;
    USE SIGNAL ;
    ANTENNADIFFAREA 2.724000 ;
    PORT
      LAYER Metal3 ;
        RECT 1350.800 38.020 1351.200 38.420 ;
    END
  END Tile_X4Y0_FrameData_O[15]
  PIN Tile_X4Y0_FrameData_O[16]
    DIRECTION OUTPUT ;
    USE SIGNAL ;
    ANTENNADIFFAREA 2.724000 ;
    PORT
      LAYER Metal3 ;
        RECT 1350.800 39.700 1351.200 40.100 ;
    END
  END Tile_X4Y0_FrameData_O[16]
  PIN Tile_X4Y0_FrameData_O[17]
    DIRECTION OUTPUT ;
    USE SIGNAL ;
    ANTENNADIFFAREA 2.724000 ;
    PORT
      LAYER Metal3 ;
        RECT 1350.800 41.380 1351.200 41.780 ;
    END
  END Tile_X4Y0_FrameData_O[17]
  PIN Tile_X4Y0_FrameData_O[18]
    DIRECTION OUTPUT ;
    USE SIGNAL ;
    ANTENNADIFFAREA 2.724000 ;
    PORT
      LAYER Metal3 ;
        RECT 1350.800 43.060 1351.200 43.460 ;
    END
  END Tile_X4Y0_FrameData_O[18]
  PIN Tile_X4Y0_FrameData_O[19]
    DIRECTION OUTPUT ;
    USE SIGNAL ;
    ANTENNADIFFAREA 2.724000 ;
    PORT
      LAYER Metal3 ;
        RECT 1350.800 44.740 1351.200 45.140 ;
    END
  END Tile_X4Y0_FrameData_O[19]
  PIN Tile_X4Y0_FrameData_O[1]
    DIRECTION OUTPUT ;
    USE SIGNAL ;
    ANTENNADIFFAREA 2.724000 ;
    PORT
      LAYER Metal3 ;
        RECT 1350.800 14.500 1351.200 14.900 ;
    END
  END Tile_X4Y0_FrameData_O[1]
  PIN Tile_X4Y0_FrameData_O[20]
    DIRECTION OUTPUT ;
    USE SIGNAL ;
    ANTENNADIFFAREA 2.724000 ;
    PORT
      LAYER Metal3 ;
        RECT 1350.800 46.420 1351.200 46.820 ;
    END
  END Tile_X4Y0_FrameData_O[20]
  PIN Tile_X4Y0_FrameData_O[21]
    DIRECTION OUTPUT ;
    USE SIGNAL ;
    ANTENNADIFFAREA 2.724000 ;
    PORT
      LAYER Metal3 ;
        RECT 1350.800 48.100 1351.200 48.500 ;
    END
  END Tile_X4Y0_FrameData_O[21]
  PIN Tile_X4Y0_FrameData_O[22]
    DIRECTION OUTPUT ;
    USE SIGNAL ;
    ANTENNADIFFAREA 2.724000 ;
    PORT
      LAYER Metal3 ;
        RECT 1350.800 49.780 1351.200 50.180 ;
    END
  END Tile_X4Y0_FrameData_O[22]
  PIN Tile_X4Y0_FrameData_O[23]
    DIRECTION OUTPUT ;
    USE SIGNAL ;
    ANTENNADIFFAREA 2.724000 ;
    PORT
      LAYER Metal3 ;
        RECT 1350.800 51.460 1351.200 51.860 ;
    END
  END Tile_X4Y0_FrameData_O[23]
  PIN Tile_X4Y0_FrameData_O[24]
    DIRECTION OUTPUT ;
    USE SIGNAL ;
    ANTENNADIFFAREA 2.724000 ;
    PORT
      LAYER Metal3 ;
        RECT 1350.800 53.140 1351.200 53.540 ;
    END
  END Tile_X4Y0_FrameData_O[24]
  PIN Tile_X4Y0_FrameData_O[25]
    DIRECTION OUTPUT ;
    USE SIGNAL ;
    ANTENNADIFFAREA 2.724000 ;
    PORT
      LAYER Metal3 ;
        RECT 1350.800 54.820 1351.200 55.220 ;
    END
  END Tile_X4Y0_FrameData_O[25]
  PIN Tile_X4Y0_FrameData_O[26]
    DIRECTION OUTPUT ;
    USE SIGNAL ;
    ANTENNADIFFAREA 2.724000 ;
    PORT
      LAYER Metal3 ;
        RECT 1350.800 56.500 1351.200 56.900 ;
    END
  END Tile_X4Y0_FrameData_O[26]
  PIN Tile_X4Y0_FrameData_O[27]
    DIRECTION OUTPUT ;
    USE SIGNAL ;
    ANTENNADIFFAREA 2.724000 ;
    PORT
      LAYER Metal3 ;
        RECT 1350.800 58.180 1351.200 58.580 ;
    END
  END Tile_X4Y0_FrameData_O[27]
  PIN Tile_X4Y0_FrameData_O[28]
    DIRECTION OUTPUT ;
    USE SIGNAL ;
    ANTENNADIFFAREA 2.724000 ;
    PORT
      LAYER Metal3 ;
        RECT 1350.800 59.860 1351.200 60.260 ;
    END
  END Tile_X4Y0_FrameData_O[28]
  PIN Tile_X4Y0_FrameData_O[29]
    DIRECTION OUTPUT ;
    USE SIGNAL ;
    ANTENNADIFFAREA 2.724000 ;
    PORT
      LAYER Metal3 ;
        RECT 1350.800 61.540 1351.200 61.940 ;
    END
  END Tile_X4Y0_FrameData_O[29]
  PIN Tile_X4Y0_FrameData_O[2]
    DIRECTION OUTPUT ;
    USE SIGNAL ;
    ANTENNADIFFAREA 2.724000 ;
    PORT
      LAYER Metal3 ;
        RECT 1350.800 16.180 1351.200 16.580 ;
    END
  END Tile_X4Y0_FrameData_O[2]
  PIN Tile_X4Y0_FrameData_O[30]
    DIRECTION OUTPUT ;
    USE SIGNAL ;
    ANTENNADIFFAREA 2.724000 ;
    PORT
      LAYER Metal3 ;
        RECT 1350.800 63.220 1351.200 63.620 ;
    END
  END Tile_X4Y0_FrameData_O[30]
  PIN Tile_X4Y0_FrameData_O[31]
    DIRECTION OUTPUT ;
    USE SIGNAL ;
    ANTENNADIFFAREA 2.724000 ;
    PORT
      LAYER Metal3 ;
        RECT 1350.800 64.900 1351.200 65.300 ;
    END
  END Tile_X4Y0_FrameData_O[31]
  PIN Tile_X4Y0_FrameData_O[3]
    DIRECTION OUTPUT ;
    USE SIGNAL ;
    ANTENNADIFFAREA 2.724000 ;
    PORT
      LAYER Metal3 ;
        RECT 1350.800 17.860 1351.200 18.260 ;
    END
  END Tile_X4Y0_FrameData_O[3]
  PIN Tile_X4Y0_FrameData_O[4]
    DIRECTION OUTPUT ;
    USE SIGNAL ;
    ANTENNADIFFAREA 2.724000 ;
    PORT
      LAYER Metal3 ;
        RECT 1350.800 19.540 1351.200 19.940 ;
    END
  END Tile_X4Y0_FrameData_O[4]
  PIN Tile_X4Y0_FrameData_O[5]
    DIRECTION OUTPUT ;
    USE SIGNAL ;
    ANTENNADIFFAREA 2.724000 ;
    PORT
      LAYER Metal3 ;
        RECT 1350.800 21.220 1351.200 21.620 ;
    END
  END Tile_X4Y0_FrameData_O[5]
  PIN Tile_X4Y0_FrameData_O[6]
    DIRECTION OUTPUT ;
    USE SIGNAL ;
    ANTENNADIFFAREA 2.724000 ;
    PORT
      LAYER Metal3 ;
        RECT 1350.800 22.900 1351.200 23.300 ;
    END
  END Tile_X4Y0_FrameData_O[6]
  PIN Tile_X4Y0_FrameData_O[7]
    DIRECTION OUTPUT ;
    USE SIGNAL ;
    ANTENNADIFFAREA 2.724000 ;
    PORT
      LAYER Metal3 ;
        RECT 1350.800 24.580 1351.200 24.980 ;
    END
  END Tile_X4Y0_FrameData_O[7]
  PIN Tile_X4Y0_FrameData_O[8]
    DIRECTION OUTPUT ;
    USE SIGNAL ;
    ANTENNADIFFAREA 2.724000 ;
    PORT
      LAYER Metal3 ;
        RECT 1350.800 26.260 1351.200 26.660 ;
    END
  END Tile_X4Y0_FrameData_O[8]
  PIN Tile_X4Y0_FrameData_O[9]
    DIRECTION OUTPUT ;
    USE SIGNAL ;
    ANTENNADIFFAREA 2.724000 ;
    PORT
      LAYER Metal3 ;
        RECT 1350.800 27.940 1351.200 28.340 ;
    END
  END Tile_X4Y0_FrameData_O[9]
  PIN Tile_X4Y0_FrameStrobe[0]
    DIRECTION INPUT ;
    USE SIGNAL ;
    ANTENNAGATEAREA 5.240300 ;
    ANTENNADIFFAREA 30.230999 ;
    PORT
      LAYER Metal2 ;
        RECT 1088.920 0.000 1089.320 0.400 ;
    END
  END Tile_X4Y0_FrameStrobe[0]
  PIN Tile_X4Y0_FrameStrobe[10]
    DIRECTION INPUT ;
    USE SIGNAL ;
    ANTENNAGATEAREA 0.180700 ;
    ANTENNADIFFAREA 2.015400 ;
    PORT
      LAYER Metal2 ;
        RECT 1108.120 0.000 1108.520 0.400 ;
    END
  END Tile_X4Y0_FrameStrobe[10]
  PIN Tile_X4Y0_FrameStrobe[11]
    DIRECTION INPUT ;
    USE SIGNAL ;
    ANTENNAGATEAREA 0.180700 ;
    ANTENNADIFFAREA 2.015400 ;
    PORT
      LAYER Metal2 ;
        RECT 1110.040 0.000 1110.440 0.400 ;
    END
  END Tile_X4Y0_FrameStrobe[11]
  PIN Tile_X4Y0_FrameStrobe[12]
    DIRECTION INPUT ;
    USE SIGNAL ;
    ANTENNAGATEAREA 0.180700 ;
    ANTENNADIFFAREA 2.015400 ;
    PORT
      LAYER Metal2 ;
        RECT 1111.960 0.000 1112.360 0.400 ;
    END
  END Tile_X4Y0_FrameStrobe[12]
  PIN Tile_X4Y0_FrameStrobe[13]
    DIRECTION INPUT ;
    USE SIGNAL ;
    ANTENNAGATEAREA 0.180700 ;
    ANTENNADIFFAREA 2.015400 ;
    PORT
      LAYER Metal2 ;
        RECT 1113.880 0.000 1114.280 0.400 ;
    END
  END Tile_X4Y0_FrameStrobe[13]
  PIN Tile_X4Y0_FrameStrobe[14]
    DIRECTION INPUT ;
    USE SIGNAL ;
    ANTENNAGATEAREA 0.180700 ;
    ANTENNADIFFAREA 2.015400 ;
    PORT
      LAYER Metal2 ;
        RECT 1115.800 0.000 1116.200 0.400 ;
    END
  END Tile_X4Y0_FrameStrobe[14]
  PIN Tile_X4Y0_FrameStrobe[15]
    DIRECTION INPUT ;
    USE SIGNAL ;
    ANTENNAGATEAREA 0.180700 ;
    ANTENNADIFFAREA 2.015400 ;
    PORT
      LAYER Metal2 ;
        RECT 1117.720 0.000 1118.120 0.400 ;
    END
  END Tile_X4Y0_FrameStrobe[15]
  PIN Tile_X4Y0_FrameStrobe[16]
    DIRECTION INPUT ;
    USE SIGNAL ;
    ANTENNAGATEAREA 0.180700 ;
    ANTENNADIFFAREA 2.015400 ;
    PORT
      LAYER Metal2 ;
        RECT 1119.640 0.000 1120.040 0.400 ;
    END
  END Tile_X4Y0_FrameStrobe[16]
  PIN Tile_X4Y0_FrameStrobe[17]
    DIRECTION INPUT ;
    USE SIGNAL ;
    ANTENNAGATEAREA 0.180700 ;
    ANTENNADIFFAREA 2.015400 ;
    PORT
      LAYER Metal2 ;
        RECT 1121.560 0.000 1121.960 0.400 ;
    END
  END Tile_X4Y0_FrameStrobe[17]
  PIN Tile_X4Y0_FrameStrobe[18]
    DIRECTION INPUT ;
    USE SIGNAL ;
    ANTENNAGATEAREA 0.180700 ;
    ANTENNADIFFAREA 2.015400 ;
    PORT
      LAYER Metal2 ;
        RECT 1123.480 0.000 1123.880 0.400 ;
    END
  END Tile_X4Y0_FrameStrobe[18]
  PIN Tile_X4Y0_FrameStrobe[19]
    DIRECTION INPUT ;
    USE SIGNAL ;
    ANTENNAGATEAREA 0.180700 ;
    ANTENNADIFFAREA 2.015400 ;
    PORT
      LAYER Metal2 ;
        RECT 1125.400 0.000 1125.800 0.400 ;
    END
  END Tile_X4Y0_FrameStrobe[19]
  PIN Tile_X4Y0_FrameStrobe[1]
    DIRECTION INPUT ;
    USE SIGNAL ;
    ANTENNAGATEAREA 0.180700 ;
    ANTENNADIFFAREA 2.015400 ;
    PORT
      LAYER Metal2 ;
        RECT 1090.840 0.000 1091.240 0.400 ;
    END
  END Tile_X4Y0_FrameStrobe[1]
  PIN Tile_X4Y0_FrameStrobe[2]
    DIRECTION INPUT ;
    USE SIGNAL ;
    ANTENNAGATEAREA 0.180700 ;
    ANTENNADIFFAREA 2.015400 ;
    PORT
      LAYER Metal2 ;
        RECT 1092.760 0.000 1093.160 0.400 ;
    END
  END Tile_X4Y0_FrameStrobe[2]
  PIN Tile_X4Y0_FrameStrobe[3]
    DIRECTION INPUT ;
    USE SIGNAL ;
    ANTENNAGATEAREA 0.180700 ;
    ANTENNADIFFAREA 2.015400 ;
    PORT
      LAYER Metal2 ;
        RECT 1094.680 0.000 1095.080 0.400 ;
    END
  END Tile_X4Y0_FrameStrobe[3]
  PIN Tile_X4Y0_FrameStrobe[4]
    DIRECTION INPUT ;
    USE SIGNAL ;
    ANTENNAGATEAREA 0.180700 ;
    ANTENNADIFFAREA 2.015400 ;
    PORT
      LAYER Metal2 ;
        RECT 1096.600 0.000 1097.000 0.400 ;
    END
  END Tile_X4Y0_FrameStrobe[4]
  PIN Tile_X4Y0_FrameStrobe[5]
    DIRECTION INPUT ;
    USE SIGNAL ;
    ANTENNAGATEAREA 0.180700 ;
    ANTENNADIFFAREA 2.015400 ;
    PORT
      LAYER Metal2 ;
        RECT 1098.520 0.000 1098.920 0.400 ;
    END
  END Tile_X4Y0_FrameStrobe[5]
  PIN Tile_X4Y0_FrameStrobe[6]
    DIRECTION INPUT ;
    USE SIGNAL ;
    ANTENNAGATEAREA 0.180700 ;
    ANTENNADIFFAREA 2.015400 ;
    PORT
      LAYER Metal2 ;
        RECT 1100.440 0.000 1100.840 0.400 ;
    END
  END Tile_X4Y0_FrameStrobe[6]
  PIN Tile_X4Y0_FrameStrobe[7]
    DIRECTION INPUT ;
    USE SIGNAL ;
    ANTENNAGATEAREA 0.180700 ;
    ANTENNADIFFAREA 2.015400 ;
    PORT
      LAYER Metal2 ;
        RECT 1102.360 0.000 1102.760 0.400 ;
    END
  END Tile_X4Y0_FrameStrobe[7]
  PIN Tile_X4Y0_FrameStrobe[8]
    DIRECTION INPUT ;
    USE SIGNAL ;
    ANTENNAGATEAREA 0.180700 ;
    ANTENNADIFFAREA 2.015400 ;
    PORT
      LAYER Metal2 ;
        RECT 1104.280 0.000 1104.680 0.400 ;
    END
  END Tile_X4Y0_FrameStrobe[8]
  PIN Tile_X4Y0_FrameStrobe[9]
    DIRECTION INPUT ;
    USE SIGNAL ;
    ANTENNAGATEAREA 0.180700 ;
    ANTENNADIFFAREA 2.015400 ;
    PORT
      LAYER Metal2 ;
        RECT 1106.200 0.000 1106.600 0.400 ;
    END
  END Tile_X4Y0_FrameStrobe[9]
  PIN Tile_X4Y0_FrameStrobe_O[0]
    DIRECTION OUTPUT ;
    USE SIGNAL ;
    ANTENNADIFFAREA 2.724000 ;
    PORT
      LAYER Metal2 ;
        RECT 1311.640 74.780 1312.040 75.180 ;
    END
  END Tile_X4Y0_FrameStrobe_O[0]
  PIN Tile_X4Y0_FrameStrobe_O[10]
    DIRECTION OUTPUT ;
    USE SIGNAL ;
    ANTENNADIFFAREA 2.724000 ;
    PORT
      LAYER Metal2 ;
        RECT 1330.840 74.780 1331.240 75.180 ;
    END
  END Tile_X4Y0_FrameStrobe_O[10]
  PIN Tile_X4Y0_FrameStrobe_O[11]
    DIRECTION OUTPUT ;
    USE SIGNAL ;
    ANTENNADIFFAREA 2.724000 ;
    PORT
      LAYER Metal2 ;
        RECT 1332.760 74.780 1333.160 75.180 ;
    END
  END Tile_X4Y0_FrameStrobe_O[11]
  PIN Tile_X4Y0_FrameStrobe_O[12]
    DIRECTION OUTPUT ;
    USE SIGNAL ;
    ANTENNADIFFAREA 2.724000 ;
    PORT
      LAYER Metal2 ;
        RECT 1334.680 74.780 1335.080 75.180 ;
    END
  END Tile_X4Y0_FrameStrobe_O[12]
  PIN Tile_X4Y0_FrameStrobe_O[13]
    DIRECTION OUTPUT ;
    USE SIGNAL ;
    ANTENNADIFFAREA 2.724000 ;
    PORT
      LAYER Metal2 ;
        RECT 1336.600 74.780 1337.000 75.180 ;
    END
  END Tile_X4Y0_FrameStrobe_O[13]
  PIN Tile_X4Y0_FrameStrobe_O[14]
    DIRECTION OUTPUT ;
    USE SIGNAL ;
    ANTENNADIFFAREA 2.724000 ;
    PORT
      LAYER Metal2 ;
        RECT 1338.520 74.780 1338.920 75.180 ;
    END
  END Tile_X4Y0_FrameStrobe_O[14]
  PIN Tile_X4Y0_FrameStrobe_O[15]
    DIRECTION OUTPUT ;
    USE SIGNAL ;
    ANTENNADIFFAREA 2.724000 ;
    PORT
      LAYER Metal2 ;
        RECT 1340.440 74.780 1340.840 75.180 ;
    END
  END Tile_X4Y0_FrameStrobe_O[15]
  PIN Tile_X4Y0_FrameStrobe_O[16]
    DIRECTION OUTPUT ;
    USE SIGNAL ;
    ANTENNADIFFAREA 2.724000 ;
    PORT
      LAYER Metal2 ;
        RECT 1342.360 74.780 1342.760 75.180 ;
    END
  END Tile_X4Y0_FrameStrobe_O[16]
  PIN Tile_X4Y0_FrameStrobe_O[17]
    DIRECTION OUTPUT ;
    USE SIGNAL ;
    ANTENNADIFFAREA 2.724000 ;
    PORT
      LAYER Metal2 ;
        RECT 1344.280 74.780 1344.680 75.180 ;
    END
  END Tile_X4Y0_FrameStrobe_O[17]
  PIN Tile_X4Y0_FrameStrobe_O[18]
    DIRECTION OUTPUT ;
    USE SIGNAL ;
    ANTENNADIFFAREA 2.724000 ;
    PORT
      LAYER Metal2 ;
        RECT 1346.200 74.780 1346.600 75.180 ;
    END
  END Tile_X4Y0_FrameStrobe_O[18]
  PIN Tile_X4Y0_FrameStrobe_O[19]
    DIRECTION OUTPUT ;
    USE SIGNAL ;
    ANTENNADIFFAREA 2.724000 ;
    PORT
      LAYER Metal2 ;
        RECT 1348.120 74.780 1348.520 75.180 ;
    END
  END Tile_X4Y0_FrameStrobe_O[19]
  PIN Tile_X4Y0_FrameStrobe_O[1]
    DIRECTION OUTPUT ;
    USE SIGNAL ;
    ANTENNADIFFAREA 2.724000 ;
    PORT
      LAYER Metal2 ;
        RECT 1313.560 74.780 1313.960 75.180 ;
    END
  END Tile_X4Y0_FrameStrobe_O[1]
  PIN Tile_X4Y0_FrameStrobe_O[2]
    DIRECTION OUTPUT ;
    USE SIGNAL ;
    ANTENNADIFFAREA 2.724000 ;
    PORT
      LAYER Metal2 ;
        RECT 1315.480 74.780 1315.880 75.180 ;
    END
  END Tile_X4Y0_FrameStrobe_O[2]
  PIN Tile_X4Y0_FrameStrobe_O[3]
    DIRECTION OUTPUT ;
    USE SIGNAL ;
    ANTENNADIFFAREA 2.724000 ;
    PORT
      LAYER Metal2 ;
        RECT 1317.400 74.780 1317.800 75.180 ;
    END
  END Tile_X4Y0_FrameStrobe_O[3]
  PIN Tile_X4Y0_FrameStrobe_O[4]
    DIRECTION OUTPUT ;
    USE SIGNAL ;
    ANTENNADIFFAREA 2.724000 ;
    PORT
      LAYER Metal2 ;
        RECT 1319.320 74.780 1319.720 75.180 ;
    END
  END Tile_X4Y0_FrameStrobe_O[4]
  PIN Tile_X4Y0_FrameStrobe_O[5]
    DIRECTION OUTPUT ;
    USE SIGNAL ;
    ANTENNADIFFAREA 2.724000 ;
    PORT
      LAYER Metal2 ;
        RECT 1321.240 74.780 1321.640 75.180 ;
    END
  END Tile_X4Y0_FrameStrobe_O[5]
  PIN Tile_X4Y0_FrameStrobe_O[6]
    DIRECTION OUTPUT ;
    USE SIGNAL ;
    ANTENNADIFFAREA 2.724000 ;
    PORT
      LAYER Metal2 ;
        RECT 1323.160 74.780 1323.560 75.180 ;
    END
  END Tile_X4Y0_FrameStrobe_O[6]
  PIN Tile_X4Y0_FrameStrobe_O[7]
    DIRECTION OUTPUT ;
    USE SIGNAL ;
    ANTENNADIFFAREA 2.724000 ;
    PORT
      LAYER Metal2 ;
        RECT 1325.080 74.780 1325.480 75.180 ;
    END
  END Tile_X4Y0_FrameStrobe_O[7]
  PIN Tile_X4Y0_FrameStrobe_O[8]
    DIRECTION OUTPUT ;
    USE SIGNAL ;
    ANTENNADIFFAREA 2.724000 ;
    PORT
      LAYER Metal2 ;
        RECT 1327.000 74.780 1327.400 75.180 ;
    END
  END Tile_X4Y0_FrameStrobe_O[8]
  PIN Tile_X4Y0_FrameStrobe_O[9]
    DIRECTION OUTPUT ;
    USE SIGNAL ;
    ANTENNADIFFAREA 2.724000 ;
    PORT
      LAYER Metal2 ;
        RECT 1328.920 74.780 1329.320 75.180 ;
    END
  END Tile_X4Y0_FrameStrobe_O[9]
  PIN Tile_X4Y0_N1BEG[0]
    DIRECTION OUTPUT ;
    USE SIGNAL ;
    ANTENNADIFFAREA 2.724000 ;
    PORT
      LAYER Metal2 ;
        RECT 1083.160 74.780 1083.560 75.180 ;
    END
  END Tile_X4Y0_N1BEG[0]
  PIN Tile_X4Y0_N1BEG[1]
    DIRECTION OUTPUT ;
    USE SIGNAL ;
    ANTENNADIFFAREA 2.724000 ;
    PORT
      LAYER Metal2 ;
        RECT 1085.080 74.780 1085.480 75.180 ;
    END
  END Tile_X4Y0_N1BEG[1]
  PIN Tile_X4Y0_N1BEG[2]
    DIRECTION OUTPUT ;
    USE SIGNAL ;
    ANTENNADIFFAREA 2.724000 ;
    PORT
      LAYER Metal2 ;
        RECT 1087.000 74.780 1087.400 75.180 ;
    END
  END Tile_X4Y0_N1BEG[2]
  PIN Tile_X4Y0_N1BEG[3]
    DIRECTION OUTPUT ;
    USE SIGNAL ;
    ANTENNADIFFAREA 2.724000 ;
    PORT
      LAYER Metal2 ;
        RECT 1088.920 74.780 1089.320 75.180 ;
    END
  END Tile_X4Y0_N1BEG[3]
  PIN Tile_X4Y0_N2BEG[0]
    DIRECTION OUTPUT ;
    USE SIGNAL ;
    ANTENNADIFFAREA 2.724000 ;
    PORT
      LAYER Metal2 ;
        RECT 1091.800 74.780 1092.200 75.180 ;
    END
  END Tile_X4Y0_N2BEG[0]
  PIN Tile_X4Y0_N2BEG[1]
    DIRECTION OUTPUT ;
    USE SIGNAL ;
    ANTENNADIFFAREA 2.724000 ;
    PORT
      LAYER Metal2 ;
        RECT 1093.720 74.780 1094.120 75.180 ;
    END
  END Tile_X4Y0_N2BEG[1]
  PIN Tile_X4Y0_N2BEG[2]
    DIRECTION OUTPUT ;
    USE SIGNAL ;
    ANTENNADIFFAREA 2.724000 ;
    PORT
      LAYER Metal2 ;
        RECT 1095.640 74.780 1096.040 75.180 ;
    END
  END Tile_X4Y0_N2BEG[2]
  PIN Tile_X4Y0_N2BEG[3]
    DIRECTION OUTPUT ;
    USE SIGNAL ;
    ANTENNADIFFAREA 2.724000 ;
    PORT
      LAYER Metal2 ;
        RECT 1097.560 74.780 1097.960 75.180 ;
    END
  END Tile_X4Y0_N2BEG[3]
  PIN Tile_X4Y0_N2BEG[4]
    DIRECTION OUTPUT ;
    USE SIGNAL ;
    ANTENNADIFFAREA 2.724000 ;
    PORT
      LAYER Metal2 ;
        RECT 1099.480 74.780 1099.880 75.180 ;
    END
  END Tile_X4Y0_N2BEG[4]
  PIN Tile_X4Y0_N2BEG[5]
    DIRECTION OUTPUT ;
    USE SIGNAL ;
    ANTENNADIFFAREA 2.724000 ;
    PORT
      LAYER Metal2 ;
        RECT 1101.400 74.780 1101.800 75.180 ;
    END
  END Tile_X4Y0_N2BEG[5]
  PIN Tile_X4Y0_N2BEG[6]
    DIRECTION OUTPUT ;
    USE SIGNAL ;
    ANTENNADIFFAREA 2.724000 ;
    PORT
      LAYER Metal2 ;
        RECT 1103.320 74.780 1103.720 75.180 ;
    END
  END Tile_X4Y0_N2BEG[6]
  PIN Tile_X4Y0_N2BEG[7]
    DIRECTION OUTPUT ;
    USE SIGNAL ;
    ANTENNADIFFAREA 2.724000 ;
    PORT
      LAYER Metal2 ;
        RECT 1105.240 74.780 1105.640 75.180 ;
    END
  END Tile_X4Y0_N2BEG[7]
  PIN Tile_X4Y0_N2BEGb[0]
    DIRECTION OUTPUT ;
    USE SIGNAL ;
    ANTENNADIFFAREA 2.724000 ;
    PORT
      LAYER Metal2 ;
        RECT 1108.120 74.780 1108.520 75.180 ;
    END
  END Tile_X4Y0_N2BEGb[0]
  PIN Tile_X4Y0_N2BEGb[1]
    DIRECTION OUTPUT ;
    USE SIGNAL ;
    ANTENNADIFFAREA 2.724000 ;
    PORT
      LAYER Metal2 ;
        RECT 1110.040 74.780 1110.440 75.180 ;
    END
  END Tile_X4Y0_N2BEGb[1]
  PIN Tile_X4Y0_N2BEGb[2]
    DIRECTION OUTPUT ;
    USE SIGNAL ;
    ANTENNADIFFAREA 2.724000 ;
    PORT
      LAYER Metal2 ;
        RECT 1111.960 74.780 1112.360 75.180 ;
    END
  END Tile_X4Y0_N2BEGb[2]
  PIN Tile_X4Y0_N2BEGb[3]
    DIRECTION OUTPUT ;
    USE SIGNAL ;
    ANTENNADIFFAREA 2.724000 ;
    PORT
      LAYER Metal2 ;
        RECT 1113.880 74.780 1114.280 75.180 ;
    END
  END Tile_X4Y0_N2BEGb[3]
  PIN Tile_X4Y0_N2BEGb[4]
    DIRECTION OUTPUT ;
    USE SIGNAL ;
    ANTENNADIFFAREA 2.724000 ;
    PORT
      LAYER Metal2 ;
        RECT 1115.800 74.780 1116.200 75.180 ;
    END
  END Tile_X4Y0_N2BEGb[4]
  PIN Tile_X4Y0_N2BEGb[5]
    DIRECTION OUTPUT ;
    USE SIGNAL ;
    ANTENNADIFFAREA 2.724000 ;
    PORT
      LAYER Metal2 ;
        RECT 1117.720 74.780 1118.120 75.180 ;
    END
  END Tile_X4Y0_N2BEGb[5]
  PIN Tile_X4Y0_N2BEGb[6]
    DIRECTION OUTPUT ;
    USE SIGNAL ;
    ANTENNADIFFAREA 2.724000 ;
    PORT
      LAYER Metal2 ;
        RECT 1119.640 74.780 1120.040 75.180 ;
    END
  END Tile_X4Y0_N2BEGb[6]
  PIN Tile_X4Y0_N2BEGb[7]
    DIRECTION OUTPUT ;
    USE SIGNAL ;
    ANTENNADIFFAREA 2.724000 ;
    PORT
      LAYER Metal2 ;
        RECT 1121.560 74.780 1121.960 75.180 ;
    END
  END Tile_X4Y0_N2BEGb[7]
  PIN Tile_X4Y0_N4BEG[0]
    DIRECTION OUTPUT ;
    USE SIGNAL ;
    ANTENNADIFFAREA 2.724000 ;
    PORT
      LAYER Metal2 ;
        RECT 1126.360 74.780 1126.760 75.180 ;
    END
  END Tile_X4Y0_N4BEG[0]
  PIN Tile_X4Y0_N4BEG[10]
    DIRECTION OUTPUT ;
    USE SIGNAL ;
    ANTENNADIFFAREA 2.724000 ;
    PORT
      LAYER Metal2 ;
        RECT 1145.560 74.780 1145.960 75.180 ;
    END
  END Tile_X4Y0_N4BEG[10]
  PIN Tile_X4Y0_N4BEG[11]
    DIRECTION OUTPUT ;
    USE SIGNAL ;
    ANTENNADIFFAREA 2.724000 ;
    PORT
      LAYER Metal2 ;
        RECT 1147.480 74.780 1147.880 75.180 ;
    END
  END Tile_X4Y0_N4BEG[11]
  PIN Tile_X4Y0_N4BEG[12]
    DIRECTION OUTPUT ;
    USE SIGNAL ;
    ANTENNADIFFAREA 2.724000 ;
    PORT
      LAYER Metal2 ;
        RECT 1149.400 74.780 1149.800 75.180 ;
    END
  END Tile_X4Y0_N4BEG[12]
  PIN Tile_X4Y0_N4BEG[13]
    DIRECTION OUTPUT ;
    USE SIGNAL ;
    ANTENNADIFFAREA 2.724000 ;
    PORT
      LAYER Metal2 ;
        RECT 1151.320 74.780 1151.720 75.180 ;
    END
  END Tile_X4Y0_N4BEG[13]
  PIN Tile_X4Y0_N4BEG[14]
    DIRECTION OUTPUT ;
    USE SIGNAL ;
    ANTENNADIFFAREA 2.724000 ;
    PORT
      LAYER Metal2 ;
        RECT 1153.240 74.780 1153.640 75.180 ;
    END
  END Tile_X4Y0_N4BEG[14]
  PIN Tile_X4Y0_N4BEG[15]
    DIRECTION OUTPUT ;
    USE SIGNAL ;
    ANTENNADIFFAREA 2.724000 ;
    PORT
      LAYER Metal2 ;
        RECT 1155.160 74.780 1155.560 75.180 ;
    END
  END Tile_X4Y0_N4BEG[15]
  PIN Tile_X4Y0_N4BEG[1]
    DIRECTION OUTPUT ;
    USE SIGNAL ;
    ANTENNADIFFAREA 2.724000 ;
    PORT
      LAYER Metal2 ;
        RECT 1128.280 74.780 1128.680 75.180 ;
    END
  END Tile_X4Y0_N4BEG[1]
  PIN Tile_X4Y0_N4BEG[2]
    DIRECTION OUTPUT ;
    USE SIGNAL ;
    ANTENNADIFFAREA 2.724000 ;
    PORT
      LAYER Metal2 ;
        RECT 1130.200 74.780 1130.600 75.180 ;
    END
  END Tile_X4Y0_N4BEG[2]
  PIN Tile_X4Y0_N4BEG[3]
    DIRECTION OUTPUT ;
    USE SIGNAL ;
    ANTENNADIFFAREA 2.724000 ;
    PORT
      LAYER Metal2 ;
        RECT 1132.120 74.780 1132.520 75.180 ;
    END
  END Tile_X4Y0_N4BEG[3]
  PIN Tile_X4Y0_N4BEG[4]
    DIRECTION OUTPUT ;
    USE SIGNAL ;
    ANTENNADIFFAREA 2.724000 ;
    PORT
      LAYER Metal2 ;
        RECT 1134.040 74.780 1134.440 75.180 ;
    END
  END Tile_X4Y0_N4BEG[4]
  PIN Tile_X4Y0_N4BEG[5]
    DIRECTION OUTPUT ;
    USE SIGNAL ;
    ANTENNADIFFAREA 2.724000 ;
    PORT
      LAYER Metal2 ;
        RECT 1135.960 74.780 1136.360 75.180 ;
    END
  END Tile_X4Y0_N4BEG[5]
  PIN Tile_X4Y0_N4BEG[6]
    DIRECTION OUTPUT ;
    USE SIGNAL ;
    ANTENNADIFFAREA 2.724000 ;
    PORT
      LAYER Metal2 ;
        RECT 1137.880 74.780 1138.280 75.180 ;
    END
  END Tile_X4Y0_N4BEG[6]
  PIN Tile_X4Y0_N4BEG[7]
    DIRECTION OUTPUT ;
    USE SIGNAL ;
    ANTENNADIFFAREA 2.724000 ;
    PORT
      LAYER Metal2 ;
        RECT 1139.800 74.780 1140.200 75.180 ;
    END
  END Tile_X4Y0_N4BEG[7]
  PIN Tile_X4Y0_N4BEG[8]
    DIRECTION OUTPUT ;
    USE SIGNAL ;
    ANTENNADIFFAREA 2.724000 ;
    PORT
      LAYER Metal2 ;
        RECT 1141.720 74.780 1142.120 75.180 ;
    END
  END Tile_X4Y0_N4BEG[8]
  PIN Tile_X4Y0_N4BEG[9]
    DIRECTION OUTPUT ;
    USE SIGNAL ;
    ANTENNADIFFAREA 2.724000 ;
    PORT
      LAYER Metal2 ;
        RECT 1143.640 74.780 1144.040 75.180 ;
    END
  END Tile_X4Y0_N4BEG[9]
  PIN Tile_X4Y0_NN4BEG[0]
    DIRECTION OUTPUT ;
    USE SIGNAL ;
    ANTENNADIFFAREA 2.724000 ;
    PORT
      LAYER Metal2 ;
        RECT 1160.920 74.780 1161.320 75.180 ;
    END
  END Tile_X4Y0_NN4BEG[0]
  PIN Tile_X4Y0_NN4BEG[10]
    DIRECTION OUTPUT ;
    USE SIGNAL ;
    ANTENNADIFFAREA 2.724000 ;
    PORT
      LAYER Metal2 ;
        RECT 1180.120 74.780 1180.520 75.180 ;
    END
  END Tile_X4Y0_NN4BEG[10]
  PIN Tile_X4Y0_NN4BEG[11]
    DIRECTION OUTPUT ;
    USE SIGNAL ;
    ANTENNADIFFAREA 2.724000 ;
    PORT
      LAYER Metal2 ;
        RECT 1182.040 74.780 1182.440 75.180 ;
    END
  END Tile_X4Y0_NN4BEG[11]
  PIN Tile_X4Y0_NN4BEG[12]
    DIRECTION OUTPUT ;
    USE SIGNAL ;
    ANTENNADIFFAREA 2.724000 ;
    PORT
      LAYER Metal2 ;
        RECT 1183.960 74.780 1184.360 75.180 ;
    END
  END Tile_X4Y0_NN4BEG[12]
  PIN Tile_X4Y0_NN4BEG[13]
    DIRECTION OUTPUT ;
    USE SIGNAL ;
    ANTENNADIFFAREA 2.724000 ;
    PORT
      LAYER Metal2 ;
        RECT 1185.880 74.780 1186.280 75.180 ;
    END
  END Tile_X4Y0_NN4BEG[13]
  PIN Tile_X4Y0_NN4BEG[14]
    DIRECTION OUTPUT ;
    USE SIGNAL ;
    ANTENNADIFFAREA 2.724000 ;
    PORT
      LAYER Metal2 ;
        RECT 1187.800 74.780 1188.200 75.180 ;
    END
  END Tile_X4Y0_NN4BEG[14]
  PIN Tile_X4Y0_NN4BEG[15]
    DIRECTION OUTPUT ;
    USE SIGNAL ;
    ANTENNADIFFAREA 2.724000 ;
    PORT
      LAYER Metal2 ;
        RECT 1189.720 74.780 1190.120 75.180 ;
    END
  END Tile_X4Y0_NN4BEG[15]
  PIN Tile_X4Y0_NN4BEG[1]
    DIRECTION OUTPUT ;
    USE SIGNAL ;
    ANTENNADIFFAREA 2.724000 ;
    PORT
      LAYER Metal2 ;
        RECT 1162.840 74.780 1163.240 75.180 ;
    END
  END Tile_X4Y0_NN4BEG[1]
  PIN Tile_X4Y0_NN4BEG[2]
    DIRECTION OUTPUT ;
    USE SIGNAL ;
    ANTENNADIFFAREA 2.724000 ;
    PORT
      LAYER Metal2 ;
        RECT 1164.760 74.780 1165.160 75.180 ;
    END
  END Tile_X4Y0_NN4BEG[2]
  PIN Tile_X4Y0_NN4BEG[3]
    DIRECTION OUTPUT ;
    USE SIGNAL ;
    ANTENNADIFFAREA 2.724000 ;
    PORT
      LAYER Metal2 ;
        RECT 1166.680 74.780 1167.080 75.180 ;
    END
  END Tile_X4Y0_NN4BEG[3]
  PIN Tile_X4Y0_NN4BEG[4]
    DIRECTION OUTPUT ;
    USE SIGNAL ;
    ANTENNADIFFAREA 2.724000 ;
    PORT
      LAYER Metal2 ;
        RECT 1168.600 74.780 1169.000 75.180 ;
    END
  END Tile_X4Y0_NN4BEG[4]
  PIN Tile_X4Y0_NN4BEG[5]
    DIRECTION OUTPUT ;
    USE SIGNAL ;
    ANTENNADIFFAREA 2.724000 ;
    PORT
      LAYER Metal2 ;
        RECT 1170.520 74.780 1170.920 75.180 ;
    END
  END Tile_X4Y0_NN4BEG[5]
  PIN Tile_X4Y0_NN4BEG[6]
    DIRECTION OUTPUT ;
    USE SIGNAL ;
    ANTENNADIFFAREA 2.724000 ;
    PORT
      LAYER Metal2 ;
        RECT 1172.440 74.780 1172.840 75.180 ;
    END
  END Tile_X4Y0_NN4BEG[6]
  PIN Tile_X4Y0_NN4BEG[7]
    DIRECTION OUTPUT ;
    USE SIGNAL ;
    ANTENNADIFFAREA 2.724000 ;
    PORT
      LAYER Metal2 ;
        RECT 1174.360 74.780 1174.760 75.180 ;
    END
  END Tile_X4Y0_NN4BEG[7]
  PIN Tile_X4Y0_NN4BEG[8]
    DIRECTION OUTPUT ;
    USE SIGNAL ;
    ANTENNADIFFAREA 2.724000 ;
    PORT
      LAYER Metal2 ;
        RECT 1176.280 74.780 1176.680 75.180 ;
    END
  END Tile_X4Y0_NN4BEG[8]
  PIN Tile_X4Y0_NN4BEG[9]
    DIRECTION OUTPUT ;
    USE SIGNAL ;
    ANTENNADIFFAREA 2.724000 ;
    PORT
      LAYER Metal2 ;
        RECT 1178.200 74.780 1178.600 75.180 ;
    END
  END Tile_X4Y0_NN4BEG[9]
  PIN Tile_X4Y0_S1END[0]
    DIRECTION INPUT ;
    USE SIGNAL ;
    ANTENNAGATEAREA 0.393900 ;
    ANTENNADIFFAREA 4.030800 ;
    PORT
      LAYER Metal2 ;
        RECT 1194.520 74.780 1194.920 75.180 ;
    END
  END Tile_X4Y0_S1END[0]
  PIN Tile_X4Y0_S1END[1]
    DIRECTION INPUT ;
    USE SIGNAL ;
    ANTENNAGATEAREA 0.393900 ;
    ANTENNADIFFAREA 4.030800 ;
    PORT
      LAYER Metal2 ;
        RECT 1196.440 74.780 1196.840 75.180 ;
    END
  END Tile_X4Y0_S1END[1]
  PIN Tile_X4Y0_S1END[2]
    DIRECTION INPUT ;
    USE SIGNAL ;
    ANTENNAGATEAREA 0.393900 ;
    ANTENNADIFFAREA 4.030800 ;
    PORT
      LAYER Metal2 ;
        RECT 1198.360 74.780 1198.760 75.180 ;
    END
  END Tile_X4Y0_S1END[2]
  PIN Tile_X4Y0_S1END[3]
    DIRECTION INPUT ;
    USE SIGNAL ;
    ANTENNAGATEAREA 0.180700 ;
    ANTENNADIFFAREA 2.015400 ;
    PORT
      LAYER Metal2 ;
        RECT 1200.280 74.780 1200.680 75.180 ;
    END
  END Tile_X4Y0_S1END[3]
  PIN Tile_X4Y0_S2END[0]
    DIRECTION INPUT ;
    USE SIGNAL ;
    ANTENNAGATEAREA 0.180700 ;
    ANTENNADIFFAREA 2.015400 ;
    PORT
      LAYER Metal2 ;
        RECT 1220.440 74.780 1220.840 75.180 ;
    END
  END Tile_X4Y0_S2END[0]
  PIN Tile_X4Y0_S2END[1]
    DIRECTION INPUT ;
    USE SIGNAL ;
    ANTENNAGATEAREA 0.180700 ;
    ANTENNADIFFAREA 2.015400 ;
    PORT
      LAYER Metal2 ;
        RECT 1222.360 74.780 1222.760 75.180 ;
    END
  END Tile_X4Y0_S2END[1]
  PIN Tile_X4Y0_S2END[2]
    DIRECTION INPUT ;
    USE SIGNAL ;
    ANTENNAGATEAREA 0.180700 ;
    ANTENNADIFFAREA 2.015400 ;
    PORT
      LAYER Metal2 ;
        RECT 1224.280 74.780 1224.680 75.180 ;
    END
  END Tile_X4Y0_S2END[2]
  PIN Tile_X4Y0_S2END[3]
    DIRECTION INPUT ;
    USE SIGNAL ;
    ANTENNAGATEAREA 0.180700 ;
    ANTENNADIFFAREA 2.015400 ;
    PORT
      LAYER Metal2 ;
        RECT 1226.200 74.780 1226.600 75.180 ;
    END
  END Tile_X4Y0_S2END[3]
  PIN Tile_X4Y0_S2END[4]
    DIRECTION INPUT ;
    USE SIGNAL ;
    ANTENNAGATEAREA 0.180700 ;
    ANTENNADIFFAREA 2.015400 ;
    PORT
      LAYER Metal2 ;
        RECT 1228.120 74.780 1228.520 75.180 ;
    END
  END Tile_X4Y0_S2END[4]
  PIN Tile_X4Y0_S2END[5]
    DIRECTION INPUT ;
    USE SIGNAL ;
    ANTENNAGATEAREA 0.393900 ;
    ANTENNADIFFAREA 4.030800 ;
    PORT
      LAYER Metal2 ;
        RECT 1230.040 74.780 1230.440 75.180 ;
    END
  END Tile_X4Y0_S2END[5]
  PIN Tile_X4Y0_S2END[6]
    DIRECTION INPUT ;
    USE SIGNAL ;
    ANTENNAGATEAREA 0.393900 ;
    ANTENNADIFFAREA 4.030800 ;
    PORT
      LAYER Metal2 ;
        RECT 1231.960 74.780 1232.360 75.180 ;
    END
  END Tile_X4Y0_S2END[6]
  PIN Tile_X4Y0_S2END[7]
    DIRECTION INPUT ;
    USE SIGNAL ;
    ANTENNAGATEAREA 0.393900 ;
    ANTENNADIFFAREA 4.030800 ;
    PORT
      LAYER Metal2 ;
        RECT 1233.880 74.780 1234.280 75.180 ;
    END
  END Tile_X4Y0_S2END[7]
  PIN Tile_X4Y0_S2MID[0]
    DIRECTION INPUT ;
    USE SIGNAL ;
    ANTENNAGATEAREA 0.393900 ;
    ANTENNADIFFAREA 4.030800 ;
    PORT
      LAYER Metal2 ;
        RECT 1203.160 74.780 1203.560 75.180 ;
    END
  END Tile_X4Y0_S2MID[0]
  PIN Tile_X4Y0_S2MID[1]
    DIRECTION INPUT ;
    USE SIGNAL ;
    ANTENNAGATEAREA 0.393900 ;
    ANTENNADIFFAREA 4.030800 ;
    PORT
      LAYER Metal2 ;
        RECT 1205.080 74.780 1205.480 75.180 ;
    END
  END Tile_X4Y0_S2MID[1]
  PIN Tile_X4Y0_S2MID[2]
    DIRECTION INPUT ;
    USE SIGNAL ;
    ANTENNAGATEAREA 0.393900 ;
    ANTENNADIFFAREA 4.030800 ;
    PORT
      LAYER Metal2 ;
        RECT 1207.000 74.780 1207.400 75.180 ;
    END
  END Tile_X4Y0_S2MID[2]
  PIN Tile_X4Y0_S2MID[3]
    DIRECTION INPUT ;
    USE SIGNAL ;
    ANTENNAGATEAREA 0.180700 ;
    ANTENNADIFFAREA 2.015400 ;
    PORT
      LAYER Metal2 ;
        RECT 1208.920 74.780 1209.320 75.180 ;
    END
  END Tile_X4Y0_S2MID[3]
  PIN Tile_X4Y0_S2MID[4]
    DIRECTION INPUT ;
    USE SIGNAL ;
    ANTENNAGATEAREA 0.180700 ;
    ANTENNADIFFAREA 2.015400 ;
    PORT
      LAYER Metal2 ;
        RECT 1210.840 74.780 1211.240 75.180 ;
    END
  END Tile_X4Y0_S2MID[4]
  PIN Tile_X4Y0_S2MID[5]
    DIRECTION INPUT ;
    USE SIGNAL ;
    ANTENNAGATEAREA 0.393900 ;
    ANTENNADIFFAREA 4.030800 ;
    PORT
      LAYER Metal2 ;
        RECT 1212.760 74.780 1213.160 75.180 ;
    END
  END Tile_X4Y0_S2MID[5]
  PIN Tile_X4Y0_S2MID[6]
    DIRECTION INPUT ;
    USE SIGNAL ;
    ANTENNAGATEAREA 0.393900 ;
    ANTENNADIFFAREA 4.030800 ;
    PORT
      LAYER Metal2 ;
        RECT 1214.680 74.780 1215.080 75.180 ;
    END
  END Tile_X4Y0_S2MID[6]
  PIN Tile_X4Y0_S2MID[7]
    DIRECTION INPUT ;
    USE SIGNAL ;
    ANTENNAGATEAREA 0.393900 ;
    ANTENNADIFFAREA 4.030800 ;
    PORT
      LAYER Metal2 ;
        RECT 1216.600 74.780 1217.000 75.180 ;
    END
  END Tile_X4Y0_S2MID[7]
  PIN Tile_X4Y0_S4END[0]
    DIRECTION INPUT ;
    USE SIGNAL ;
    ANTENNAGATEAREA 0.180700 ;
    ANTENNADIFFAREA 2.015400 ;
    PORT
      LAYER Metal2 ;
        RECT 1238.680 74.780 1239.080 75.180 ;
    END
  END Tile_X4Y0_S4END[0]
  PIN Tile_X4Y0_S4END[10]
    DIRECTION INPUT ;
    USE SIGNAL ;
    ANTENNAGATEAREA 0.180700 ;
    ANTENNADIFFAREA 2.015400 ;
    PORT
      LAYER Metal2 ;
        RECT 1257.880 74.780 1258.280 75.180 ;
    END
  END Tile_X4Y0_S4END[10]
  PIN Tile_X4Y0_S4END[11]
    DIRECTION INPUT ;
    USE SIGNAL ;
    ANTENNAGATEAREA 0.180700 ;
    ANTENNADIFFAREA 2.015400 ;
    PORT
      LAYER Metal2 ;
        RECT 1259.800 74.780 1260.200 75.180 ;
    END
  END Tile_X4Y0_S4END[11]
  PIN Tile_X4Y0_S4END[12]
    DIRECTION INPUT ;
    USE SIGNAL ;
    ANTENNAGATEAREA 0.180700 ;
    ANTENNADIFFAREA 2.015400 ;
    PORT
      LAYER Metal2 ;
        RECT 1261.720 74.780 1262.120 75.180 ;
    END
  END Tile_X4Y0_S4END[12]
  PIN Tile_X4Y0_S4END[13]
    DIRECTION INPUT ;
    USE SIGNAL ;
    ANTENNAGATEAREA 0.180700 ;
    ANTENNADIFFAREA 2.015400 ;
    PORT
      LAYER Metal2 ;
        RECT 1263.640 74.780 1264.040 75.180 ;
    END
  END Tile_X4Y0_S4END[13]
  PIN Tile_X4Y0_S4END[14]
    DIRECTION INPUT ;
    USE SIGNAL ;
    ANTENNAGATEAREA 0.180700 ;
    ANTENNADIFFAREA 2.015400 ;
    PORT
      LAYER Metal2 ;
        RECT 1265.560 74.780 1265.960 75.180 ;
    END
  END Tile_X4Y0_S4END[14]
  PIN Tile_X4Y0_S4END[15]
    DIRECTION INPUT ;
    USE SIGNAL ;
    ANTENNAGATEAREA 0.180700 ;
    ANTENNADIFFAREA 2.015400 ;
    PORT
      LAYER Metal2 ;
        RECT 1267.480 74.780 1267.880 75.180 ;
    END
  END Tile_X4Y0_S4END[15]
  PIN Tile_X4Y0_S4END[1]
    DIRECTION INPUT ;
    USE SIGNAL ;
    ANTENNAGATEAREA 0.180700 ;
    ANTENNADIFFAREA 2.015400 ;
    PORT
      LAYER Metal2 ;
        RECT 1240.600 74.780 1241.000 75.180 ;
    END
  END Tile_X4Y0_S4END[1]
  PIN Tile_X4Y0_S4END[2]
    DIRECTION INPUT ;
    USE SIGNAL ;
    ANTENNAGATEAREA 0.180700 ;
    ANTENNADIFFAREA 2.015400 ;
    PORT
      LAYER Metal2 ;
        RECT 1242.520 74.780 1242.920 75.180 ;
    END
  END Tile_X4Y0_S4END[2]
  PIN Tile_X4Y0_S4END[3]
    DIRECTION INPUT ;
    USE SIGNAL ;
    ANTENNAGATEAREA 0.180700 ;
    ANTENNADIFFAREA 2.015400 ;
    PORT
      LAYER Metal2 ;
        RECT 1244.440 74.780 1244.840 75.180 ;
    END
  END Tile_X4Y0_S4END[3]
  PIN Tile_X4Y0_S4END[4]
    DIRECTION INPUT ;
    USE SIGNAL ;
    ANTENNAGATEAREA 0.180700 ;
    ANTENNADIFFAREA 2.015400 ;
    PORT
      LAYER Metal2 ;
        RECT 1246.360 74.780 1246.760 75.180 ;
    END
  END Tile_X4Y0_S4END[4]
  PIN Tile_X4Y0_S4END[5]
    DIRECTION INPUT ;
    USE SIGNAL ;
    ANTENNAGATEAREA 0.180700 ;
    ANTENNADIFFAREA 2.015400 ;
    PORT
      LAYER Metal2 ;
        RECT 1248.280 74.780 1248.680 75.180 ;
    END
  END Tile_X4Y0_S4END[5]
  PIN Tile_X4Y0_S4END[6]
    DIRECTION INPUT ;
    USE SIGNAL ;
    ANTENNAGATEAREA 0.180700 ;
    ANTENNADIFFAREA 2.015400 ;
    PORT
      LAYER Metal2 ;
        RECT 1250.200 74.780 1250.600 75.180 ;
    END
  END Tile_X4Y0_S4END[6]
  PIN Tile_X4Y0_S4END[7]
    DIRECTION INPUT ;
    USE SIGNAL ;
    ANTENNAGATEAREA 0.180700 ;
    ANTENNADIFFAREA 2.015400 ;
    PORT
      LAYER Metal2 ;
        RECT 1252.120 74.780 1252.520 75.180 ;
    END
  END Tile_X4Y0_S4END[7]
  PIN Tile_X4Y0_S4END[8]
    DIRECTION INPUT ;
    USE SIGNAL ;
    ANTENNAGATEAREA 0.180700 ;
    ANTENNADIFFAREA 2.015400 ;
    PORT
      LAYER Metal2 ;
        RECT 1254.040 74.780 1254.440 75.180 ;
    END
  END Tile_X4Y0_S4END[8]
  PIN Tile_X4Y0_S4END[9]
    DIRECTION INPUT ;
    USE SIGNAL ;
    ANTENNAGATEAREA 0.180700 ;
    ANTENNADIFFAREA 2.015400 ;
    PORT
      LAYER Metal2 ;
        RECT 1255.960 74.780 1256.360 75.180 ;
    END
  END Tile_X4Y0_S4END[9]
  PIN Tile_X4Y0_SS4END[0]
    DIRECTION INPUT ;
    USE SIGNAL ;
    ANTENNAGATEAREA 0.180700 ;
    ANTENNADIFFAREA 2.015400 ;
    PORT
      LAYER Metal2 ;
        RECT 1273.240 74.780 1273.640 75.180 ;
    END
  END Tile_X4Y0_SS4END[0]
  PIN Tile_X4Y0_SS4END[10]
    DIRECTION INPUT ;
    USE SIGNAL ;
    ANTENNAGATEAREA 0.180700 ;
    ANTENNADIFFAREA 2.015400 ;
    PORT
      LAYER Metal2 ;
        RECT 1292.440 74.780 1292.840 75.180 ;
    END
  END Tile_X4Y0_SS4END[10]
  PIN Tile_X4Y0_SS4END[11]
    DIRECTION INPUT ;
    USE SIGNAL ;
    ANTENNAGATEAREA 0.180700 ;
    ANTENNADIFFAREA 2.015400 ;
    PORT
      LAYER Metal2 ;
        RECT 1294.360 74.780 1294.760 75.180 ;
    END
  END Tile_X4Y0_SS4END[11]
  PIN Tile_X4Y0_SS4END[12]
    DIRECTION INPUT ;
    USE SIGNAL ;
    ANTENNAGATEAREA 0.180700 ;
    ANTENNADIFFAREA 2.015400 ;
    PORT
      LAYER Metal2 ;
        RECT 1296.280 74.780 1296.680 75.180 ;
    END
  END Tile_X4Y0_SS4END[12]
  PIN Tile_X4Y0_SS4END[13]
    DIRECTION INPUT ;
    USE SIGNAL ;
    ANTENNAGATEAREA 0.180700 ;
    ANTENNADIFFAREA 2.015400 ;
    PORT
      LAYER Metal2 ;
        RECT 1298.200 74.780 1298.600 75.180 ;
    END
  END Tile_X4Y0_SS4END[13]
  PIN Tile_X4Y0_SS4END[14]
    DIRECTION INPUT ;
    USE SIGNAL ;
    ANTENNAGATEAREA 0.180700 ;
    ANTENNADIFFAREA 2.015400 ;
    PORT
      LAYER Metal2 ;
        RECT 1300.120 74.780 1300.520 75.180 ;
    END
  END Tile_X4Y0_SS4END[14]
  PIN Tile_X4Y0_SS4END[15]
    DIRECTION INPUT ;
    USE SIGNAL ;
    ANTENNAGATEAREA 0.180700 ;
    ANTENNADIFFAREA 2.015400 ;
    PORT
      LAYER Metal2 ;
        RECT 1302.040 74.780 1302.440 75.180 ;
    END
  END Tile_X4Y0_SS4END[15]
  PIN Tile_X4Y0_SS4END[1]
    DIRECTION INPUT ;
    USE SIGNAL ;
    ANTENNAGATEAREA 0.180700 ;
    ANTENNADIFFAREA 2.015400 ;
    PORT
      LAYER Metal2 ;
        RECT 1275.160 74.780 1275.560 75.180 ;
    END
  END Tile_X4Y0_SS4END[1]
  PIN Tile_X4Y0_SS4END[2]
    DIRECTION INPUT ;
    USE SIGNAL ;
    ANTENNAGATEAREA 0.180700 ;
    ANTENNADIFFAREA 2.015400 ;
    PORT
      LAYER Metal2 ;
        RECT 1277.080 74.780 1277.480 75.180 ;
    END
  END Tile_X4Y0_SS4END[2]
  PIN Tile_X4Y0_SS4END[3]
    DIRECTION INPUT ;
    USE SIGNAL ;
    ANTENNAGATEAREA 0.180700 ;
    ANTENNADIFFAREA 2.015400 ;
    PORT
      LAYER Metal2 ;
        RECT 1279.000 74.780 1279.400 75.180 ;
    END
  END Tile_X4Y0_SS4END[3]
  PIN Tile_X4Y0_SS4END[4]
    DIRECTION INPUT ;
    USE SIGNAL ;
    ANTENNAGATEAREA 0.180700 ;
    ANTENNADIFFAREA 2.015400 ;
    PORT
      LAYER Metal2 ;
        RECT 1280.920 74.780 1281.320 75.180 ;
    END
  END Tile_X4Y0_SS4END[4]
  PIN Tile_X4Y0_SS4END[5]
    DIRECTION INPUT ;
    USE SIGNAL ;
    ANTENNAGATEAREA 0.180700 ;
    ANTENNADIFFAREA 2.015400 ;
    PORT
      LAYER Metal2 ;
        RECT 1282.840 74.780 1283.240 75.180 ;
    END
  END Tile_X4Y0_SS4END[5]
  PIN Tile_X4Y0_SS4END[6]
    DIRECTION INPUT ;
    USE SIGNAL ;
    ANTENNAGATEAREA 0.180700 ;
    ANTENNADIFFAREA 2.015400 ;
    PORT
      LAYER Metal2 ;
        RECT 1284.760 74.780 1285.160 75.180 ;
    END
  END Tile_X4Y0_SS4END[6]
  PIN Tile_X4Y0_SS4END[7]
    DIRECTION INPUT ;
    USE SIGNAL ;
    ANTENNAGATEAREA 0.180700 ;
    ANTENNADIFFAREA 2.015400 ;
    PORT
      LAYER Metal2 ;
        RECT 1286.680 74.780 1287.080 75.180 ;
    END
  END Tile_X4Y0_SS4END[7]
  PIN Tile_X4Y0_SS4END[8]
    DIRECTION INPUT ;
    USE SIGNAL ;
    ANTENNAGATEAREA 0.180700 ;
    ANTENNADIFFAREA 2.015400 ;
    PORT
      LAYER Metal2 ;
        RECT 1288.600 74.780 1289.000 75.180 ;
    END
  END Tile_X4Y0_SS4END[8]
  PIN Tile_X4Y0_SS4END[9]
    DIRECTION INPUT ;
    USE SIGNAL ;
    ANTENNAGATEAREA 0.180700 ;
    ANTENNADIFFAREA 2.015400 ;
    PORT
      LAYER Metal2 ;
        RECT 1290.520 74.780 1290.920 75.180 ;
    END
  END Tile_X4Y0_SS4END[9]
  PIN Tile_X4Y0_UserCLKo
    DIRECTION OUTPUT ;
    USE SIGNAL ;
    ANTENNADIFFAREA 2.724000 ;
    PORT
      LAYER Metal3 ;
        RECT 1350.800 1.900 1351.200 2.300 ;
    END
  END Tile_X4Y0_UserCLKo
  PIN VGND
    DIRECTION INOUT ;
    USE GROUND ;
    PORT
      LAYER Metal4 ;
        RECT 13.940 0.000 14.940 75.180 ;
    END
    PORT
      LAYER Metal4 ;
        RECT 63.940 0.000 64.940 75.180 ;
    END
    PORT
      LAYER Metal4 ;
        RECT 113.940 0.000 114.940 75.180 ;
    END
    PORT
      LAYER Metal4 ;
        RECT 163.940 0.000 164.940 75.180 ;
    END
    PORT
      LAYER Metal4 ;
        RECT 213.940 0.000 214.940 75.180 ;
    END
    PORT
      LAYER Metal4 ;
        RECT 263.940 0.000 264.940 75.180 ;
    END
    PORT
      LAYER Metal4 ;
        RECT 284.180 0.000 285.180 75.180 ;
    END
    PORT
      LAYER Metal4 ;
        RECT 334.180 0.000 335.180 75.180 ;
    END
    PORT
      LAYER Metal4 ;
        RECT 384.180 0.000 385.180 75.180 ;
    END
    PORT
      LAYER Metal4 ;
        RECT 434.180 0.000 435.180 75.180 ;
    END
    PORT
      LAYER Metal4 ;
        RECT 484.180 0.000 485.180 75.180 ;
    END
    PORT
      LAYER Metal4 ;
        RECT 534.180 0.000 535.180 75.180 ;
    END
    PORT
      LAYER Metal4 ;
        RECT 554.420 0.000 555.420 75.180 ;
    END
    PORT
      LAYER Metal4 ;
        RECT 604.420 0.000 605.420 75.180 ;
    END
    PORT
      LAYER Metal4 ;
        RECT 654.420 0.000 655.420 75.180 ;
    END
    PORT
      LAYER Metal4 ;
        RECT 704.420 0.000 705.420 75.180 ;
    END
    PORT
      LAYER Metal4 ;
        RECT 754.420 0.000 755.420 75.180 ;
    END
    PORT
      LAYER Metal4 ;
        RECT 804.420 0.000 805.420 75.180 ;
    END
    PORT
      LAYER Metal4 ;
        RECT 824.660 0.000 825.660 75.180 ;
    END
    PORT
      LAYER Metal4 ;
        RECT 874.660 0.000 875.660 75.180 ;
    END
    PORT
      LAYER Metal4 ;
        RECT 924.660 0.000 925.660 75.180 ;
    END
    PORT
      LAYER Metal4 ;
        RECT 974.660 0.000 975.660 75.180 ;
    END
    PORT
      LAYER Metal4 ;
        RECT 1024.660 0.000 1025.660 75.180 ;
    END
    PORT
      LAYER Metal4 ;
        RECT 1074.660 0.000 1075.660 75.180 ;
    END
    PORT
      LAYER Metal4 ;
        RECT 1094.900 0.000 1095.900 75.180 ;
    END
    PORT
      LAYER Metal4 ;
        RECT 1144.900 0.000 1145.900 75.180 ;
    END
    PORT
      LAYER Metal4 ;
        RECT 1194.900 0.000 1195.900 75.180 ;
    END
    PORT
      LAYER Metal4 ;
        RECT 1244.900 0.000 1245.900 75.180 ;
    END
    PORT
      LAYER Metal4 ;
        RECT 1294.900 0.000 1295.900 75.180 ;
    END
    PORT
      LAYER Metal4 ;
        RECT 1344.900 0.000 1345.900 75.180 ;
    END
  END VGND
  PIN VPWR
    DIRECTION INOUT ;
    USE POWER ;
    PORT
      LAYER Metal4 ;
        RECT 10.940 0.000 11.940 75.180 ;
    END
    PORT
      LAYER Metal4 ;
        RECT 60.940 0.000 61.940 75.180 ;
    END
    PORT
      LAYER Metal4 ;
        RECT 110.940 0.000 111.940 75.180 ;
    END
    PORT
      LAYER Metal4 ;
        RECT 160.940 0.000 161.940 75.180 ;
    END
    PORT
      LAYER Metal4 ;
        RECT 210.940 0.000 211.940 75.180 ;
    END
    PORT
      LAYER Metal4 ;
        RECT 260.940 0.000 261.940 75.180 ;
    END
    PORT
      LAYER Metal4 ;
        RECT 281.180 0.000 282.180 75.180 ;
    END
    PORT
      LAYER Metal4 ;
        RECT 331.180 0.000 332.180 75.180 ;
    END
    PORT
      LAYER Metal4 ;
        RECT 381.180 0.000 382.180 75.180 ;
    END
    PORT
      LAYER Metal4 ;
        RECT 431.180 0.000 432.180 75.180 ;
    END
    PORT
      LAYER Metal4 ;
        RECT 481.180 0.000 482.180 75.180 ;
    END
    PORT
      LAYER Metal4 ;
        RECT 531.180 0.000 532.180 75.180 ;
    END
    PORT
      LAYER Metal4 ;
        RECT 551.420 0.000 552.420 75.180 ;
    END
    PORT
      LAYER Metal4 ;
        RECT 601.420 0.000 602.420 75.180 ;
    END
    PORT
      LAYER Metal4 ;
        RECT 651.420 0.000 652.420 75.180 ;
    END
    PORT
      LAYER Metal4 ;
        RECT 701.420 0.000 702.420 75.180 ;
    END
    PORT
      LAYER Metal4 ;
        RECT 751.420 0.000 752.420 75.180 ;
    END
    PORT
      LAYER Metal4 ;
        RECT 801.420 0.000 802.420 75.180 ;
    END
    PORT
      LAYER Metal4 ;
        RECT 821.660 0.000 822.660 75.180 ;
    END
    PORT
      LAYER Metal4 ;
        RECT 871.660 0.000 872.660 75.180 ;
    END
    PORT
      LAYER Metal4 ;
        RECT 921.660 0.000 922.660 75.180 ;
    END
    PORT
      LAYER Metal4 ;
        RECT 971.660 0.000 972.660 75.180 ;
    END
    PORT
      LAYER Metal4 ;
        RECT 1021.660 0.000 1022.660 75.180 ;
    END
    PORT
      LAYER Metal4 ;
        RECT 1071.660 0.000 1072.660 75.180 ;
    END
    PORT
      LAYER Metal4 ;
        RECT 1091.900 0.000 1092.900 75.180 ;
    END
    PORT
      LAYER Metal4 ;
        RECT 1141.900 0.000 1142.900 75.180 ;
    END
    PORT
      LAYER Metal4 ;
        RECT 1191.900 0.000 1192.900 75.180 ;
    END
    PORT
      LAYER Metal4 ;
        RECT 1241.900 0.000 1242.900 75.180 ;
    END
    PORT
      LAYER Metal4 ;
        RECT 1291.900 0.000 1292.900 75.180 ;
    END
    PORT
      LAYER Metal4 ;
        RECT 1341.900 0.000 1342.900 75.180 ;
    END
  END VPWR
  OBS
      LAYER GatPoly ;
        RECT 1.440 3.630 1349.760 68.190 ;
      LAYER Metal1 ;
        RECT 1.440 3.560 1349.760 68.260 ;
      LAYER Metal2 ;
        RECT 0.855 74.570 1.990 74.905 ;
        RECT 2.810 74.570 3.910 74.905 ;
        RECT 4.730 74.570 5.830 74.905 ;
        RECT 6.650 74.570 7.750 74.905 ;
        RECT 8.570 74.570 10.630 74.905 ;
        RECT 11.450 74.570 12.550 74.905 ;
        RECT 13.370 74.570 14.470 74.905 ;
        RECT 15.290 74.570 16.390 74.905 ;
        RECT 17.210 74.570 18.310 74.905 ;
        RECT 19.130 74.570 20.230 74.905 ;
        RECT 21.050 74.570 22.150 74.905 ;
        RECT 22.970 74.570 24.070 74.905 ;
        RECT 24.890 74.570 26.950 74.905 ;
        RECT 27.770 74.570 28.870 74.905 ;
        RECT 29.690 74.570 30.790 74.905 ;
        RECT 31.610 74.570 32.710 74.905 ;
        RECT 33.530 74.570 34.630 74.905 ;
        RECT 35.450 74.570 36.550 74.905 ;
        RECT 37.370 74.570 38.470 74.905 ;
        RECT 39.290 74.570 40.390 74.905 ;
        RECT 41.210 74.570 45.190 74.905 ;
        RECT 46.010 74.570 47.110 74.905 ;
        RECT 47.930 74.570 49.030 74.905 ;
        RECT 49.850 74.570 50.950 74.905 ;
        RECT 51.770 74.570 52.870 74.905 ;
        RECT 53.690 74.570 54.790 74.905 ;
        RECT 55.610 74.570 56.710 74.905 ;
        RECT 57.530 74.570 58.630 74.905 ;
        RECT 59.450 74.570 60.550 74.905 ;
        RECT 61.370 74.570 62.470 74.905 ;
        RECT 63.290 74.570 64.390 74.905 ;
        RECT 65.210 74.570 66.310 74.905 ;
        RECT 67.130 74.570 68.230 74.905 ;
        RECT 69.050 74.570 70.150 74.905 ;
        RECT 70.970 74.570 72.070 74.905 ;
        RECT 72.890 74.570 73.990 74.905 ;
        RECT 74.810 74.570 79.750 74.905 ;
        RECT 80.570 74.570 81.670 74.905 ;
        RECT 82.490 74.570 83.590 74.905 ;
        RECT 84.410 74.570 85.510 74.905 ;
        RECT 86.330 74.570 87.430 74.905 ;
        RECT 88.250 74.570 89.350 74.905 ;
        RECT 90.170 74.570 91.270 74.905 ;
        RECT 92.090 74.570 93.190 74.905 ;
        RECT 94.010 74.570 95.110 74.905 ;
        RECT 95.930 74.570 97.030 74.905 ;
        RECT 97.850 74.570 98.950 74.905 ;
        RECT 99.770 74.570 100.870 74.905 ;
        RECT 101.690 74.570 102.790 74.905 ;
        RECT 103.610 74.570 104.710 74.905 ;
        RECT 105.530 74.570 106.630 74.905 ;
        RECT 107.450 74.570 108.550 74.905 ;
        RECT 109.370 74.570 113.350 74.905 ;
        RECT 114.170 74.570 115.270 74.905 ;
        RECT 116.090 74.570 117.190 74.905 ;
        RECT 118.010 74.570 119.110 74.905 ;
        RECT 119.930 74.570 121.990 74.905 ;
        RECT 122.810 74.570 123.910 74.905 ;
        RECT 124.730 74.570 125.830 74.905 ;
        RECT 126.650 74.570 127.750 74.905 ;
        RECT 128.570 74.570 129.670 74.905 ;
        RECT 130.490 74.570 131.590 74.905 ;
        RECT 132.410 74.570 133.510 74.905 ;
        RECT 134.330 74.570 135.430 74.905 ;
        RECT 136.250 74.570 139.270 74.905 ;
        RECT 140.090 74.570 141.190 74.905 ;
        RECT 142.010 74.570 143.110 74.905 ;
        RECT 143.930 74.570 145.030 74.905 ;
        RECT 145.850 74.570 146.950 74.905 ;
        RECT 147.770 74.570 148.870 74.905 ;
        RECT 149.690 74.570 150.790 74.905 ;
        RECT 151.610 74.570 152.710 74.905 ;
        RECT 153.530 74.570 157.510 74.905 ;
        RECT 158.330 74.570 159.430 74.905 ;
        RECT 160.250 74.570 161.350 74.905 ;
        RECT 162.170 74.570 163.270 74.905 ;
        RECT 164.090 74.570 165.190 74.905 ;
        RECT 166.010 74.570 167.110 74.905 ;
        RECT 167.930 74.570 169.030 74.905 ;
        RECT 169.850 74.570 170.950 74.905 ;
        RECT 171.770 74.570 172.870 74.905 ;
        RECT 173.690 74.570 174.790 74.905 ;
        RECT 175.610 74.570 176.710 74.905 ;
        RECT 177.530 74.570 178.630 74.905 ;
        RECT 179.450 74.570 180.550 74.905 ;
        RECT 181.370 74.570 182.470 74.905 ;
        RECT 183.290 74.570 184.390 74.905 ;
        RECT 185.210 74.570 186.310 74.905 ;
        RECT 187.130 74.570 192.070 74.905 ;
        RECT 192.890 74.570 193.990 74.905 ;
        RECT 194.810 74.570 195.910 74.905 ;
        RECT 196.730 74.570 197.830 74.905 ;
        RECT 198.650 74.570 199.750 74.905 ;
        RECT 200.570 74.570 201.670 74.905 ;
        RECT 202.490 74.570 203.590 74.905 ;
        RECT 204.410 74.570 205.510 74.905 ;
        RECT 206.330 74.570 207.430 74.905 ;
        RECT 208.250 74.570 209.350 74.905 ;
        RECT 210.170 74.570 211.270 74.905 ;
        RECT 212.090 74.570 213.190 74.905 ;
        RECT 214.010 74.570 215.110 74.905 ;
        RECT 215.930 74.570 217.030 74.905 ;
        RECT 217.850 74.570 218.950 74.905 ;
        RECT 219.770 74.570 220.870 74.905 ;
        RECT 221.690 74.570 225.670 74.905 ;
        RECT 226.490 74.570 230.470 74.905 ;
        RECT 231.290 74.570 232.390 74.905 ;
        RECT 233.210 74.570 234.310 74.905 ;
        RECT 235.130 74.570 236.230 74.905 ;
        RECT 237.050 74.570 238.150 74.905 ;
        RECT 238.970 74.570 240.070 74.905 ;
        RECT 240.890 74.570 241.990 74.905 ;
        RECT 242.810 74.570 243.910 74.905 ;
        RECT 244.730 74.570 245.830 74.905 ;
        RECT 246.650 74.570 247.750 74.905 ;
        RECT 248.570 74.570 249.670 74.905 ;
        RECT 250.490 74.570 251.590 74.905 ;
        RECT 252.410 74.570 253.510 74.905 ;
        RECT 254.330 74.570 255.430 74.905 ;
        RECT 256.250 74.570 257.350 74.905 ;
        RECT 258.170 74.570 259.270 74.905 ;
        RECT 260.090 74.570 261.190 74.905 ;
        RECT 262.010 74.570 263.110 74.905 ;
        RECT 263.930 74.570 265.030 74.905 ;
        RECT 265.850 74.570 266.950 74.905 ;
        RECT 267.770 74.570 272.230 74.905 ;
        RECT 273.050 74.570 274.150 74.905 ;
        RECT 274.970 74.570 276.070 74.905 ;
        RECT 276.890 74.570 277.990 74.905 ;
        RECT 278.810 74.570 280.870 74.905 ;
        RECT 281.690 74.570 282.790 74.905 ;
        RECT 283.610 74.570 284.710 74.905 ;
        RECT 285.530 74.570 286.630 74.905 ;
        RECT 287.450 74.570 288.550 74.905 ;
        RECT 289.370 74.570 290.470 74.905 ;
        RECT 291.290 74.570 292.390 74.905 ;
        RECT 293.210 74.570 294.310 74.905 ;
        RECT 295.130 74.570 297.190 74.905 ;
        RECT 298.010 74.570 299.110 74.905 ;
        RECT 299.930 74.570 301.030 74.905 ;
        RECT 301.850 74.570 302.950 74.905 ;
        RECT 303.770 74.570 304.870 74.905 ;
        RECT 305.690 74.570 306.790 74.905 ;
        RECT 307.610 74.570 308.710 74.905 ;
        RECT 309.530 74.570 310.630 74.905 ;
        RECT 311.450 74.570 315.430 74.905 ;
        RECT 316.250 74.570 317.350 74.905 ;
        RECT 318.170 74.570 319.270 74.905 ;
        RECT 320.090 74.570 321.190 74.905 ;
        RECT 322.010 74.570 323.110 74.905 ;
        RECT 323.930 74.570 325.030 74.905 ;
        RECT 325.850 74.570 326.950 74.905 ;
        RECT 327.770 74.570 328.870 74.905 ;
        RECT 329.690 74.570 330.790 74.905 ;
        RECT 331.610 74.570 332.710 74.905 ;
        RECT 333.530 74.570 334.630 74.905 ;
        RECT 335.450 74.570 336.550 74.905 ;
        RECT 337.370 74.570 338.470 74.905 ;
        RECT 339.290 74.570 340.390 74.905 ;
        RECT 341.210 74.570 342.310 74.905 ;
        RECT 343.130 74.570 344.230 74.905 ;
        RECT 345.050 74.570 349.990 74.905 ;
        RECT 350.810 74.570 351.910 74.905 ;
        RECT 352.730 74.570 353.830 74.905 ;
        RECT 354.650 74.570 355.750 74.905 ;
        RECT 356.570 74.570 357.670 74.905 ;
        RECT 358.490 74.570 359.590 74.905 ;
        RECT 360.410 74.570 361.510 74.905 ;
        RECT 362.330 74.570 363.430 74.905 ;
        RECT 364.250 74.570 365.350 74.905 ;
        RECT 366.170 74.570 367.270 74.905 ;
        RECT 368.090 74.570 369.190 74.905 ;
        RECT 370.010 74.570 371.110 74.905 ;
        RECT 371.930 74.570 373.030 74.905 ;
        RECT 373.850 74.570 374.950 74.905 ;
        RECT 375.770 74.570 376.870 74.905 ;
        RECT 377.690 74.570 378.790 74.905 ;
        RECT 379.610 74.570 383.590 74.905 ;
        RECT 384.410 74.570 385.510 74.905 ;
        RECT 386.330 74.570 387.430 74.905 ;
        RECT 388.250 74.570 389.350 74.905 ;
        RECT 390.170 74.570 392.230 74.905 ;
        RECT 393.050 74.570 394.150 74.905 ;
        RECT 394.970 74.570 396.070 74.905 ;
        RECT 396.890 74.570 397.990 74.905 ;
        RECT 398.810 74.570 399.910 74.905 ;
        RECT 400.730 74.570 401.830 74.905 ;
        RECT 402.650 74.570 403.750 74.905 ;
        RECT 404.570 74.570 405.670 74.905 ;
        RECT 406.490 74.570 409.510 74.905 ;
        RECT 410.330 74.570 411.430 74.905 ;
        RECT 412.250 74.570 413.350 74.905 ;
        RECT 414.170 74.570 415.270 74.905 ;
        RECT 416.090 74.570 417.190 74.905 ;
        RECT 418.010 74.570 419.110 74.905 ;
        RECT 419.930 74.570 421.030 74.905 ;
        RECT 421.850 74.570 422.950 74.905 ;
        RECT 423.770 74.570 427.750 74.905 ;
        RECT 428.570 74.570 429.670 74.905 ;
        RECT 430.490 74.570 431.590 74.905 ;
        RECT 432.410 74.570 433.510 74.905 ;
        RECT 434.330 74.570 435.430 74.905 ;
        RECT 436.250 74.570 437.350 74.905 ;
        RECT 438.170 74.570 439.270 74.905 ;
        RECT 440.090 74.570 441.190 74.905 ;
        RECT 442.010 74.570 443.110 74.905 ;
        RECT 443.930 74.570 445.030 74.905 ;
        RECT 445.850 74.570 446.950 74.905 ;
        RECT 447.770 74.570 448.870 74.905 ;
        RECT 449.690 74.570 450.790 74.905 ;
        RECT 451.610 74.570 452.710 74.905 ;
        RECT 453.530 74.570 454.630 74.905 ;
        RECT 455.450 74.570 456.550 74.905 ;
        RECT 457.370 74.570 462.310 74.905 ;
        RECT 463.130 74.570 464.230 74.905 ;
        RECT 465.050 74.570 466.150 74.905 ;
        RECT 466.970 74.570 468.070 74.905 ;
        RECT 468.890 74.570 469.990 74.905 ;
        RECT 470.810 74.570 471.910 74.905 ;
        RECT 472.730 74.570 473.830 74.905 ;
        RECT 474.650 74.570 475.750 74.905 ;
        RECT 476.570 74.570 477.670 74.905 ;
        RECT 478.490 74.570 479.590 74.905 ;
        RECT 480.410 74.570 481.510 74.905 ;
        RECT 482.330 74.570 483.430 74.905 ;
        RECT 484.250 74.570 485.350 74.905 ;
        RECT 486.170 74.570 487.270 74.905 ;
        RECT 488.090 74.570 489.190 74.905 ;
        RECT 490.010 74.570 491.110 74.905 ;
        RECT 491.930 74.570 495.910 74.905 ;
        RECT 496.730 74.570 500.710 74.905 ;
        RECT 501.530 74.570 502.630 74.905 ;
        RECT 503.450 74.570 504.550 74.905 ;
        RECT 505.370 74.570 506.470 74.905 ;
        RECT 507.290 74.570 508.390 74.905 ;
        RECT 509.210 74.570 510.310 74.905 ;
        RECT 511.130 74.570 512.230 74.905 ;
        RECT 513.050 74.570 514.150 74.905 ;
        RECT 514.970 74.570 516.070 74.905 ;
        RECT 516.890 74.570 517.990 74.905 ;
        RECT 518.810 74.570 519.910 74.905 ;
        RECT 520.730 74.570 521.830 74.905 ;
        RECT 522.650 74.570 523.750 74.905 ;
        RECT 524.570 74.570 525.670 74.905 ;
        RECT 526.490 74.570 527.590 74.905 ;
        RECT 528.410 74.570 529.510 74.905 ;
        RECT 530.330 74.570 531.430 74.905 ;
        RECT 532.250 74.570 533.350 74.905 ;
        RECT 534.170 74.570 535.270 74.905 ;
        RECT 536.090 74.570 537.190 74.905 ;
        RECT 538.010 74.570 542.470 74.905 ;
        RECT 543.290 74.570 544.390 74.905 ;
        RECT 545.210 74.570 546.310 74.905 ;
        RECT 547.130 74.570 548.230 74.905 ;
        RECT 549.050 74.570 551.110 74.905 ;
        RECT 551.930 74.570 553.030 74.905 ;
        RECT 553.850 74.570 554.950 74.905 ;
        RECT 555.770 74.570 556.870 74.905 ;
        RECT 557.690 74.570 558.790 74.905 ;
        RECT 559.610 74.570 560.710 74.905 ;
        RECT 561.530 74.570 562.630 74.905 ;
        RECT 563.450 74.570 564.550 74.905 ;
        RECT 565.370 74.570 567.430 74.905 ;
        RECT 568.250 74.570 569.350 74.905 ;
        RECT 570.170 74.570 571.270 74.905 ;
        RECT 572.090 74.570 573.190 74.905 ;
        RECT 574.010 74.570 575.110 74.905 ;
        RECT 575.930 74.570 577.030 74.905 ;
        RECT 577.850 74.570 578.950 74.905 ;
        RECT 579.770 74.570 580.870 74.905 ;
        RECT 581.690 74.570 585.670 74.905 ;
        RECT 586.490 74.570 587.590 74.905 ;
        RECT 588.410 74.570 589.510 74.905 ;
        RECT 590.330 74.570 591.430 74.905 ;
        RECT 592.250 74.570 593.350 74.905 ;
        RECT 594.170 74.570 595.270 74.905 ;
        RECT 596.090 74.570 597.190 74.905 ;
        RECT 598.010 74.570 599.110 74.905 ;
        RECT 599.930 74.570 601.030 74.905 ;
        RECT 601.850 74.570 602.950 74.905 ;
        RECT 603.770 74.570 604.870 74.905 ;
        RECT 605.690 74.570 606.790 74.905 ;
        RECT 607.610 74.570 608.710 74.905 ;
        RECT 609.530 74.570 610.630 74.905 ;
        RECT 611.450 74.570 612.550 74.905 ;
        RECT 613.370 74.570 614.470 74.905 ;
        RECT 615.290 74.570 620.230 74.905 ;
        RECT 621.050 74.570 622.150 74.905 ;
        RECT 622.970 74.570 624.070 74.905 ;
        RECT 624.890 74.570 625.990 74.905 ;
        RECT 626.810 74.570 627.910 74.905 ;
        RECT 628.730 74.570 629.830 74.905 ;
        RECT 630.650 74.570 631.750 74.905 ;
        RECT 632.570 74.570 633.670 74.905 ;
        RECT 634.490 74.570 635.590 74.905 ;
        RECT 636.410 74.570 637.510 74.905 ;
        RECT 638.330 74.570 639.430 74.905 ;
        RECT 640.250 74.570 641.350 74.905 ;
        RECT 642.170 74.570 643.270 74.905 ;
        RECT 644.090 74.570 645.190 74.905 ;
        RECT 646.010 74.570 647.110 74.905 ;
        RECT 647.930 74.570 649.030 74.905 ;
        RECT 649.850 74.570 653.830 74.905 ;
        RECT 654.650 74.570 655.750 74.905 ;
        RECT 656.570 74.570 657.670 74.905 ;
        RECT 658.490 74.570 659.590 74.905 ;
        RECT 660.410 74.570 662.470 74.905 ;
        RECT 663.290 74.570 664.390 74.905 ;
        RECT 665.210 74.570 666.310 74.905 ;
        RECT 667.130 74.570 668.230 74.905 ;
        RECT 669.050 74.570 670.150 74.905 ;
        RECT 670.970 74.570 672.070 74.905 ;
        RECT 672.890 74.570 673.990 74.905 ;
        RECT 674.810 74.570 675.910 74.905 ;
        RECT 676.730 74.570 679.750 74.905 ;
        RECT 680.570 74.570 681.670 74.905 ;
        RECT 682.490 74.570 683.590 74.905 ;
        RECT 684.410 74.570 685.510 74.905 ;
        RECT 686.330 74.570 687.430 74.905 ;
        RECT 688.250 74.570 689.350 74.905 ;
        RECT 690.170 74.570 691.270 74.905 ;
        RECT 692.090 74.570 693.190 74.905 ;
        RECT 694.010 74.570 697.990 74.905 ;
        RECT 698.810 74.570 699.910 74.905 ;
        RECT 700.730 74.570 701.830 74.905 ;
        RECT 702.650 74.570 703.750 74.905 ;
        RECT 704.570 74.570 705.670 74.905 ;
        RECT 706.490 74.570 707.590 74.905 ;
        RECT 708.410 74.570 709.510 74.905 ;
        RECT 710.330 74.570 711.430 74.905 ;
        RECT 712.250 74.570 713.350 74.905 ;
        RECT 714.170 74.570 715.270 74.905 ;
        RECT 716.090 74.570 717.190 74.905 ;
        RECT 718.010 74.570 719.110 74.905 ;
        RECT 719.930 74.570 721.030 74.905 ;
        RECT 721.850 74.570 722.950 74.905 ;
        RECT 723.770 74.570 724.870 74.905 ;
        RECT 725.690 74.570 726.790 74.905 ;
        RECT 727.610 74.570 732.550 74.905 ;
        RECT 733.370 74.570 734.470 74.905 ;
        RECT 735.290 74.570 736.390 74.905 ;
        RECT 737.210 74.570 738.310 74.905 ;
        RECT 739.130 74.570 740.230 74.905 ;
        RECT 741.050 74.570 742.150 74.905 ;
        RECT 742.970 74.570 744.070 74.905 ;
        RECT 744.890 74.570 745.990 74.905 ;
        RECT 746.810 74.570 747.910 74.905 ;
        RECT 748.730 74.570 749.830 74.905 ;
        RECT 750.650 74.570 751.750 74.905 ;
        RECT 752.570 74.570 753.670 74.905 ;
        RECT 754.490 74.570 755.590 74.905 ;
        RECT 756.410 74.570 757.510 74.905 ;
        RECT 758.330 74.570 759.430 74.905 ;
        RECT 760.250 74.570 761.350 74.905 ;
        RECT 762.170 74.570 766.150 74.905 ;
        RECT 766.970 74.570 770.950 74.905 ;
        RECT 771.770 74.570 772.870 74.905 ;
        RECT 773.690 74.570 774.790 74.905 ;
        RECT 775.610 74.570 776.710 74.905 ;
        RECT 777.530 74.570 778.630 74.905 ;
        RECT 779.450 74.570 780.550 74.905 ;
        RECT 781.370 74.570 782.470 74.905 ;
        RECT 783.290 74.570 784.390 74.905 ;
        RECT 785.210 74.570 786.310 74.905 ;
        RECT 787.130 74.570 788.230 74.905 ;
        RECT 789.050 74.570 790.150 74.905 ;
        RECT 790.970 74.570 792.070 74.905 ;
        RECT 792.890 74.570 793.990 74.905 ;
        RECT 794.810 74.570 795.910 74.905 ;
        RECT 796.730 74.570 797.830 74.905 ;
        RECT 798.650 74.570 799.750 74.905 ;
        RECT 800.570 74.570 801.670 74.905 ;
        RECT 802.490 74.570 803.590 74.905 ;
        RECT 804.410 74.570 805.510 74.905 ;
        RECT 806.330 74.570 807.430 74.905 ;
        RECT 808.250 74.570 812.710 74.905 ;
        RECT 813.530 74.570 814.630 74.905 ;
        RECT 815.450 74.570 816.550 74.905 ;
        RECT 817.370 74.570 818.470 74.905 ;
        RECT 819.290 74.570 821.350 74.905 ;
        RECT 822.170 74.570 823.270 74.905 ;
        RECT 824.090 74.570 825.190 74.905 ;
        RECT 826.010 74.570 827.110 74.905 ;
        RECT 827.930 74.570 829.030 74.905 ;
        RECT 829.850 74.570 830.950 74.905 ;
        RECT 831.770 74.570 832.870 74.905 ;
        RECT 833.690 74.570 834.790 74.905 ;
        RECT 835.610 74.570 837.670 74.905 ;
        RECT 838.490 74.570 839.590 74.905 ;
        RECT 840.410 74.570 841.510 74.905 ;
        RECT 842.330 74.570 843.430 74.905 ;
        RECT 844.250 74.570 845.350 74.905 ;
        RECT 846.170 74.570 847.270 74.905 ;
        RECT 848.090 74.570 849.190 74.905 ;
        RECT 850.010 74.570 851.110 74.905 ;
        RECT 851.930 74.570 855.910 74.905 ;
        RECT 856.730 74.570 857.830 74.905 ;
        RECT 858.650 74.570 859.750 74.905 ;
        RECT 860.570 74.570 861.670 74.905 ;
        RECT 862.490 74.570 863.590 74.905 ;
        RECT 864.410 74.570 865.510 74.905 ;
        RECT 866.330 74.570 867.430 74.905 ;
        RECT 868.250 74.570 869.350 74.905 ;
        RECT 870.170 74.570 871.270 74.905 ;
        RECT 872.090 74.570 873.190 74.905 ;
        RECT 874.010 74.570 875.110 74.905 ;
        RECT 875.930 74.570 877.030 74.905 ;
        RECT 877.850 74.570 878.950 74.905 ;
        RECT 879.770 74.570 880.870 74.905 ;
        RECT 881.690 74.570 882.790 74.905 ;
        RECT 883.610 74.570 884.710 74.905 ;
        RECT 885.530 74.570 890.470 74.905 ;
        RECT 891.290 74.570 892.390 74.905 ;
        RECT 893.210 74.570 894.310 74.905 ;
        RECT 895.130 74.570 896.230 74.905 ;
        RECT 897.050 74.570 898.150 74.905 ;
        RECT 898.970 74.570 900.070 74.905 ;
        RECT 900.890 74.570 901.990 74.905 ;
        RECT 902.810 74.570 903.910 74.905 ;
        RECT 904.730 74.570 905.830 74.905 ;
        RECT 906.650 74.570 907.750 74.905 ;
        RECT 908.570 74.570 909.670 74.905 ;
        RECT 910.490 74.570 911.590 74.905 ;
        RECT 912.410 74.570 913.510 74.905 ;
        RECT 914.330 74.570 915.430 74.905 ;
        RECT 916.250 74.570 917.350 74.905 ;
        RECT 918.170 74.570 919.270 74.905 ;
        RECT 920.090 74.570 924.070 74.905 ;
        RECT 924.890 74.570 925.990 74.905 ;
        RECT 926.810 74.570 927.910 74.905 ;
        RECT 928.730 74.570 929.830 74.905 ;
        RECT 930.650 74.570 932.710 74.905 ;
        RECT 933.530 74.570 934.630 74.905 ;
        RECT 935.450 74.570 936.550 74.905 ;
        RECT 937.370 74.570 938.470 74.905 ;
        RECT 939.290 74.570 940.390 74.905 ;
        RECT 941.210 74.570 942.310 74.905 ;
        RECT 943.130 74.570 944.230 74.905 ;
        RECT 945.050 74.570 946.150 74.905 ;
        RECT 946.970 74.570 949.990 74.905 ;
        RECT 950.810 74.570 951.910 74.905 ;
        RECT 952.730 74.570 953.830 74.905 ;
        RECT 954.650 74.570 955.750 74.905 ;
        RECT 956.570 74.570 957.670 74.905 ;
        RECT 958.490 74.570 959.590 74.905 ;
        RECT 960.410 74.570 961.510 74.905 ;
        RECT 962.330 74.570 963.430 74.905 ;
        RECT 964.250 74.570 968.230 74.905 ;
        RECT 969.050 74.570 970.150 74.905 ;
        RECT 970.970 74.570 972.070 74.905 ;
        RECT 972.890 74.570 973.990 74.905 ;
        RECT 974.810 74.570 975.910 74.905 ;
        RECT 976.730 74.570 977.830 74.905 ;
        RECT 978.650 74.570 979.750 74.905 ;
        RECT 980.570 74.570 981.670 74.905 ;
        RECT 982.490 74.570 983.590 74.905 ;
        RECT 984.410 74.570 985.510 74.905 ;
        RECT 986.330 74.570 987.430 74.905 ;
        RECT 988.250 74.570 989.350 74.905 ;
        RECT 990.170 74.570 991.270 74.905 ;
        RECT 992.090 74.570 993.190 74.905 ;
        RECT 994.010 74.570 995.110 74.905 ;
        RECT 995.930 74.570 997.030 74.905 ;
        RECT 997.850 74.570 1002.790 74.905 ;
        RECT 1003.610 74.570 1004.710 74.905 ;
        RECT 1005.530 74.570 1006.630 74.905 ;
        RECT 1007.450 74.570 1008.550 74.905 ;
        RECT 1009.370 74.570 1010.470 74.905 ;
        RECT 1011.290 74.570 1012.390 74.905 ;
        RECT 1013.210 74.570 1014.310 74.905 ;
        RECT 1015.130 74.570 1016.230 74.905 ;
        RECT 1017.050 74.570 1018.150 74.905 ;
        RECT 1018.970 74.570 1020.070 74.905 ;
        RECT 1020.890 74.570 1021.990 74.905 ;
        RECT 1022.810 74.570 1023.910 74.905 ;
        RECT 1024.730 74.570 1025.830 74.905 ;
        RECT 1026.650 74.570 1027.750 74.905 ;
        RECT 1028.570 74.570 1029.670 74.905 ;
        RECT 1030.490 74.570 1031.590 74.905 ;
        RECT 1032.410 74.570 1036.390 74.905 ;
        RECT 1037.210 74.570 1041.190 74.905 ;
        RECT 1042.010 74.570 1043.110 74.905 ;
        RECT 1043.930 74.570 1045.030 74.905 ;
        RECT 1045.850 74.570 1046.950 74.905 ;
        RECT 1047.770 74.570 1048.870 74.905 ;
        RECT 1049.690 74.570 1050.790 74.905 ;
        RECT 1051.610 74.570 1052.710 74.905 ;
        RECT 1053.530 74.570 1054.630 74.905 ;
        RECT 1055.450 74.570 1056.550 74.905 ;
        RECT 1057.370 74.570 1058.470 74.905 ;
        RECT 1059.290 74.570 1060.390 74.905 ;
        RECT 1061.210 74.570 1062.310 74.905 ;
        RECT 1063.130 74.570 1064.230 74.905 ;
        RECT 1065.050 74.570 1066.150 74.905 ;
        RECT 1066.970 74.570 1068.070 74.905 ;
        RECT 1068.890 74.570 1069.990 74.905 ;
        RECT 1070.810 74.570 1071.910 74.905 ;
        RECT 1072.730 74.570 1073.830 74.905 ;
        RECT 1074.650 74.570 1075.750 74.905 ;
        RECT 1076.570 74.570 1077.670 74.905 ;
        RECT 1078.490 74.570 1082.950 74.905 ;
        RECT 1083.770 74.570 1084.870 74.905 ;
        RECT 1085.690 74.570 1086.790 74.905 ;
        RECT 1087.610 74.570 1088.710 74.905 ;
        RECT 1089.530 74.570 1091.590 74.905 ;
        RECT 1092.410 74.570 1093.510 74.905 ;
        RECT 1094.330 74.570 1095.430 74.905 ;
        RECT 1096.250 74.570 1097.350 74.905 ;
        RECT 1098.170 74.570 1099.270 74.905 ;
        RECT 1100.090 74.570 1101.190 74.905 ;
        RECT 1102.010 74.570 1103.110 74.905 ;
        RECT 1103.930 74.570 1105.030 74.905 ;
        RECT 1105.850 74.570 1107.910 74.905 ;
        RECT 1108.730 74.570 1109.830 74.905 ;
        RECT 1110.650 74.570 1111.750 74.905 ;
        RECT 1112.570 74.570 1113.670 74.905 ;
        RECT 1114.490 74.570 1115.590 74.905 ;
        RECT 1116.410 74.570 1117.510 74.905 ;
        RECT 1118.330 74.570 1119.430 74.905 ;
        RECT 1120.250 74.570 1121.350 74.905 ;
        RECT 1122.170 74.570 1126.150 74.905 ;
        RECT 1126.970 74.570 1128.070 74.905 ;
        RECT 1128.890 74.570 1129.990 74.905 ;
        RECT 1130.810 74.570 1131.910 74.905 ;
        RECT 1132.730 74.570 1133.830 74.905 ;
        RECT 1134.650 74.570 1135.750 74.905 ;
        RECT 1136.570 74.570 1137.670 74.905 ;
        RECT 1138.490 74.570 1139.590 74.905 ;
        RECT 1140.410 74.570 1141.510 74.905 ;
        RECT 1142.330 74.570 1143.430 74.905 ;
        RECT 1144.250 74.570 1145.350 74.905 ;
        RECT 1146.170 74.570 1147.270 74.905 ;
        RECT 1148.090 74.570 1149.190 74.905 ;
        RECT 1150.010 74.570 1151.110 74.905 ;
        RECT 1151.930 74.570 1153.030 74.905 ;
        RECT 1153.850 74.570 1154.950 74.905 ;
        RECT 1155.770 74.570 1160.710 74.905 ;
        RECT 1161.530 74.570 1162.630 74.905 ;
        RECT 1163.450 74.570 1164.550 74.905 ;
        RECT 1165.370 74.570 1166.470 74.905 ;
        RECT 1167.290 74.570 1168.390 74.905 ;
        RECT 1169.210 74.570 1170.310 74.905 ;
        RECT 1171.130 74.570 1172.230 74.905 ;
        RECT 1173.050 74.570 1174.150 74.905 ;
        RECT 1174.970 74.570 1176.070 74.905 ;
        RECT 1176.890 74.570 1177.990 74.905 ;
        RECT 1178.810 74.570 1179.910 74.905 ;
        RECT 1180.730 74.570 1181.830 74.905 ;
        RECT 1182.650 74.570 1183.750 74.905 ;
        RECT 1184.570 74.570 1185.670 74.905 ;
        RECT 1186.490 74.570 1187.590 74.905 ;
        RECT 1188.410 74.570 1189.510 74.905 ;
        RECT 1190.330 74.570 1194.310 74.905 ;
        RECT 1195.130 74.570 1196.230 74.905 ;
        RECT 1197.050 74.570 1198.150 74.905 ;
        RECT 1198.970 74.570 1200.070 74.905 ;
        RECT 1200.890 74.570 1202.950 74.905 ;
        RECT 1203.770 74.570 1204.870 74.905 ;
        RECT 1205.690 74.570 1206.790 74.905 ;
        RECT 1207.610 74.570 1208.710 74.905 ;
        RECT 1209.530 74.570 1210.630 74.905 ;
        RECT 1211.450 74.570 1212.550 74.905 ;
        RECT 1213.370 74.570 1214.470 74.905 ;
        RECT 1215.290 74.570 1216.390 74.905 ;
        RECT 1217.210 74.570 1220.230 74.905 ;
        RECT 1221.050 74.570 1222.150 74.905 ;
        RECT 1222.970 74.570 1224.070 74.905 ;
        RECT 1224.890 74.570 1225.990 74.905 ;
        RECT 1226.810 74.570 1227.910 74.905 ;
        RECT 1228.730 74.570 1229.830 74.905 ;
        RECT 1230.650 74.570 1231.750 74.905 ;
        RECT 1232.570 74.570 1233.670 74.905 ;
        RECT 1234.490 74.570 1238.470 74.905 ;
        RECT 1239.290 74.570 1240.390 74.905 ;
        RECT 1241.210 74.570 1242.310 74.905 ;
        RECT 1243.130 74.570 1244.230 74.905 ;
        RECT 1245.050 74.570 1246.150 74.905 ;
        RECT 1246.970 74.570 1248.070 74.905 ;
        RECT 1248.890 74.570 1249.990 74.905 ;
        RECT 1250.810 74.570 1251.910 74.905 ;
        RECT 1252.730 74.570 1253.830 74.905 ;
        RECT 1254.650 74.570 1255.750 74.905 ;
        RECT 1256.570 74.570 1257.670 74.905 ;
        RECT 1258.490 74.570 1259.590 74.905 ;
        RECT 1260.410 74.570 1261.510 74.905 ;
        RECT 1262.330 74.570 1263.430 74.905 ;
        RECT 1264.250 74.570 1265.350 74.905 ;
        RECT 1266.170 74.570 1267.270 74.905 ;
        RECT 1268.090 74.570 1273.030 74.905 ;
        RECT 1273.850 74.570 1274.950 74.905 ;
        RECT 1275.770 74.570 1276.870 74.905 ;
        RECT 1277.690 74.570 1278.790 74.905 ;
        RECT 1279.610 74.570 1280.710 74.905 ;
        RECT 1281.530 74.570 1282.630 74.905 ;
        RECT 1283.450 74.570 1284.550 74.905 ;
        RECT 1285.370 74.570 1286.470 74.905 ;
        RECT 1287.290 74.570 1288.390 74.905 ;
        RECT 1289.210 74.570 1290.310 74.905 ;
        RECT 1291.130 74.570 1292.230 74.905 ;
        RECT 1293.050 74.570 1294.150 74.905 ;
        RECT 1294.970 74.570 1296.070 74.905 ;
        RECT 1296.890 74.570 1297.990 74.905 ;
        RECT 1298.810 74.570 1299.910 74.905 ;
        RECT 1300.730 74.570 1301.830 74.905 ;
        RECT 1302.650 74.570 1306.630 74.905 ;
        RECT 1307.450 74.570 1311.430 74.905 ;
        RECT 1312.250 74.570 1313.350 74.905 ;
        RECT 1314.170 74.570 1315.270 74.905 ;
        RECT 1316.090 74.570 1317.190 74.905 ;
        RECT 1318.010 74.570 1319.110 74.905 ;
        RECT 1319.930 74.570 1321.030 74.905 ;
        RECT 1321.850 74.570 1322.950 74.905 ;
        RECT 1323.770 74.570 1324.870 74.905 ;
        RECT 1325.690 74.570 1326.790 74.905 ;
        RECT 1327.610 74.570 1328.710 74.905 ;
        RECT 1329.530 74.570 1330.630 74.905 ;
        RECT 1331.450 74.570 1332.550 74.905 ;
        RECT 1333.370 74.570 1334.470 74.905 ;
        RECT 1335.290 74.570 1336.390 74.905 ;
        RECT 1337.210 74.570 1338.310 74.905 ;
        RECT 1339.130 74.570 1340.230 74.905 ;
        RECT 1341.050 74.570 1342.150 74.905 ;
        RECT 1342.970 74.570 1344.070 74.905 ;
        RECT 1344.890 74.570 1345.990 74.905 ;
        RECT 1346.810 74.570 1347.910 74.905 ;
        RECT 1348.730 74.570 1349.385 74.905 ;
        RECT 0.855 0.610 1349.385 74.570 ;
        RECT 0.855 0.275 7.750 0.610 ;
        RECT 8.570 0.275 21.190 0.610 ;
        RECT 22.010 0.275 34.630 0.610 ;
        RECT 35.450 0.275 48.070 0.610 ;
        RECT 48.890 0.275 61.510 0.610 ;
        RECT 62.330 0.275 74.950 0.610 ;
        RECT 75.770 0.275 88.390 0.610 ;
        RECT 89.210 0.275 101.830 0.610 ;
        RECT 102.650 0.275 115.270 0.610 ;
        RECT 116.090 0.275 128.710 0.610 ;
        RECT 129.530 0.275 142.150 0.610 ;
        RECT 142.970 0.275 155.590 0.610 ;
        RECT 156.410 0.275 169.030 0.610 ;
        RECT 169.850 0.275 182.470 0.610 ;
        RECT 183.290 0.275 195.910 0.610 ;
        RECT 196.730 0.275 209.350 0.610 ;
        RECT 210.170 0.275 222.790 0.610 ;
        RECT 223.610 0.275 236.230 0.610 ;
        RECT 237.050 0.275 249.670 0.610 ;
        RECT 250.490 0.275 263.110 0.610 ;
        RECT 263.930 0.275 277.990 0.610 ;
        RECT 278.810 0.275 291.430 0.610 ;
        RECT 292.250 0.275 304.870 0.610 ;
        RECT 305.690 0.275 318.310 0.610 ;
        RECT 319.130 0.275 331.750 0.610 ;
        RECT 332.570 0.275 345.190 0.610 ;
        RECT 346.010 0.275 358.630 0.610 ;
        RECT 359.450 0.275 372.070 0.610 ;
        RECT 372.890 0.275 385.510 0.610 ;
        RECT 386.330 0.275 398.950 0.610 ;
        RECT 399.770 0.275 412.390 0.610 ;
        RECT 413.210 0.275 425.830 0.610 ;
        RECT 426.650 0.275 439.270 0.610 ;
        RECT 440.090 0.275 452.710 0.610 ;
        RECT 453.530 0.275 466.150 0.610 ;
        RECT 466.970 0.275 479.590 0.610 ;
        RECT 480.410 0.275 493.030 0.610 ;
        RECT 493.850 0.275 506.470 0.610 ;
        RECT 507.290 0.275 519.910 0.610 ;
        RECT 520.730 0.275 533.350 0.610 ;
        RECT 534.170 0.275 548.230 0.610 ;
        RECT 549.050 0.275 561.670 0.610 ;
        RECT 562.490 0.275 575.110 0.610 ;
        RECT 575.930 0.275 588.550 0.610 ;
        RECT 589.370 0.275 601.990 0.610 ;
        RECT 602.810 0.275 615.430 0.610 ;
        RECT 616.250 0.275 628.870 0.610 ;
        RECT 629.690 0.275 642.310 0.610 ;
        RECT 643.130 0.275 655.750 0.610 ;
        RECT 656.570 0.275 669.190 0.610 ;
        RECT 670.010 0.275 682.630 0.610 ;
        RECT 683.450 0.275 696.070 0.610 ;
        RECT 696.890 0.275 709.510 0.610 ;
        RECT 710.330 0.275 722.950 0.610 ;
        RECT 723.770 0.275 736.390 0.610 ;
        RECT 737.210 0.275 749.830 0.610 ;
        RECT 750.650 0.275 763.270 0.610 ;
        RECT 764.090 0.275 776.710 0.610 ;
        RECT 777.530 0.275 790.150 0.610 ;
        RECT 790.970 0.275 803.590 0.610 ;
        RECT 804.410 0.275 818.470 0.610 ;
        RECT 819.290 0.275 831.910 0.610 ;
        RECT 832.730 0.275 845.350 0.610 ;
        RECT 846.170 0.275 858.790 0.610 ;
        RECT 859.610 0.275 872.230 0.610 ;
        RECT 873.050 0.275 885.670 0.610 ;
        RECT 886.490 0.275 899.110 0.610 ;
        RECT 899.930 0.275 912.550 0.610 ;
        RECT 913.370 0.275 925.990 0.610 ;
        RECT 926.810 0.275 939.430 0.610 ;
        RECT 940.250 0.275 952.870 0.610 ;
        RECT 953.690 0.275 966.310 0.610 ;
        RECT 967.130 0.275 979.750 0.610 ;
        RECT 980.570 0.275 993.190 0.610 ;
        RECT 994.010 0.275 1006.630 0.610 ;
        RECT 1007.450 0.275 1020.070 0.610 ;
        RECT 1020.890 0.275 1033.510 0.610 ;
        RECT 1034.330 0.275 1046.950 0.610 ;
        RECT 1047.770 0.275 1060.390 0.610 ;
        RECT 1061.210 0.275 1073.830 0.610 ;
        RECT 1074.650 0.275 1088.710 0.610 ;
        RECT 1089.530 0.275 1090.630 0.610 ;
        RECT 1091.450 0.275 1092.550 0.610 ;
        RECT 1093.370 0.275 1094.470 0.610 ;
        RECT 1095.290 0.275 1096.390 0.610 ;
        RECT 1097.210 0.275 1098.310 0.610 ;
        RECT 1099.130 0.275 1100.230 0.610 ;
        RECT 1101.050 0.275 1102.150 0.610 ;
        RECT 1102.970 0.275 1104.070 0.610 ;
        RECT 1104.890 0.275 1105.990 0.610 ;
        RECT 1106.810 0.275 1107.910 0.610 ;
        RECT 1108.730 0.275 1109.830 0.610 ;
        RECT 1110.650 0.275 1111.750 0.610 ;
        RECT 1112.570 0.275 1113.670 0.610 ;
        RECT 1114.490 0.275 1115.590 0.610 ;
        RECT 1116.410 0.275 1117.510 0.610 ;
        RECT 1118.330 0.275 1119.430 0.610 ;
        RECT 1120.250 0.275 1121.350 0.610 ;
        RECT 1122.170 0.275 1123.270 0.610 ;
        RECT 1124.090 0.275 1125.190 0.610 ;
        RECT 1126.010 0.275 1163.590 0.610 ;
        RECT 1164.410 0.275 1165.510 0.610 ;
        RECT 1166.330 0.275 1167.430 0.610 ;
        RECT 1168.250 0.275 1169.350 0.610 ;
        RECT 1170.170 0.275 1171.270 0.610 ;
        RECT 1172.090 0.275 1173.190 0.610 ;
        RECT 1174.010 0.275 1175.110 0.610 ;
        RECT 1175.930 0.275 1177.030 0.610 ;
        RECT 1177.850 0.275 1178.950 0.610 ;
        RECT 1179.770 0.275 1180.870 0.610 ;
        RECT 1181.690 0.275 1182.790 0.610 ;
        RECT 1183.610 0.275 1184.710 0.610 ;
        RECT 1185.530 0.275 1186.630 0.610 ;
        RECT 1187.450 0.275 1188.550 0.610 ;
        RECT 1189.370 0.275 1190.470 0.610 ;
        RECT 1191.290 0.275 1192.390 0.610 ;
        RECT 1193.210 0.275 1194.310 0.610 ;
        RECT 1195.130 0.275 1196.230 0.610 ;
        RECT 1197.050 0.275 1198.150 0.610 ;
        RECT 1198.970 0.275 1200.070 0.610 ;
        RECT 1200.890 0.275 1201.990 0.610 ;
        RECT 1202.810 0.275 1203.910 0.610 ;
        RECT 1204.730 0.275 1205.830 0.610 ;
        RECT 1206.650 0.275 1207.750 0.610 ;
        RECT 1208.570 0.275 1209.670 0.610 ;
        RECT 1210.490 0.275 1211.590 0.610 ;
        RECT 1212.410 0.275 1213.510 0.610 ;
        RECT 1214.330 0.275 1215.430 0.610 ;
        RECT 1216.250 0.275 1217.350 0.610 ;
        RECT 1218.170 0.275 1219.270 0.610 ;
        RECT 1220.090 0.275 1221.190 0.610 ;
        RECT 1222.010 0.275 1223.110 0.610 ;
        RECT 1223.930 0.275 1225.030 0.610 ;
        RECT 1225.850 0.275 1226.950 0.610 ;
        RECT 1227.770 0.275 1228.870 0.610 ;
        RECT 1229.690 0.275 1230.790 0.610 ;
        RECT 1231.610 0.275 1232.710 0.610 ;
        RECT 1233.530 0.275 1234.630 0.610 ;
        RECT 1235.450 0.275 1236.550 0.610 ;
        RECT 1237.370 0.275 1238.470 0.610 ;
        RECT 1239.290 0.275 1240.390 0.610 ;
        RECT 1241.210 0.275 1242.310 0.610 ;
        RECT 1243.130 0.275 1244.230 0.610 ;
        RECT 1245.050 0.275 1246.150 0.610 ;
        RECT 1246.970 0.275 1248.070 0.610 ;
        RECT 1248.890 0.275 1249.990 0.610 ;
        RECT 1250.810 0.275 1251.910 0.610 ;
        RECT 1252.730 0.275 1253.830 0.610 ;
        RECT 1254.650 0.275 1255.750 0.610 ;
        RECT 1256.570 0.275 1257.670 0.610 ;
        RECT 1258.490 0.275 1259.590 0.610 ;
        RECT 1260.410 0.275 1261.510 0.610 ;
        RECT 1262.330 0.275 1263.430 0.610 ;
        RECT 1264.250 0.275 1265.350 0.610 ;
        RECT 1266.170 0.275 1267.270 0.610 ;
        RECT 1268.090 0.275 1269.190 0.610 ;
        RECT 1270.010 0.275 1271.110 0.610 ;
        RECT 1271.930 0.275 1273.030 0.610 ;
        RECT 1273.850 0.275 1274.950 0.610 ;
        RECT 1275.770 0.275 1276.870 0.610 ;
        RECT 1277.690 0.275 1278.790 0.610 ;
        RECT 1279.610 0.275 1280.710 0.610 ;
        RECT 1281.530 0.275 1282.630 0.610 ;
        RECT 1283.450 0.275 1284.550 0.610 ;
        RECT 1285.370 0.275 1286.470 0.610 ;
        RECT 1287.290 0.275 1288.390 0.610 ;
        RECT 1289.210 0.275 1290.310 0.610 ;
        RECT 1291.130 0.275 1292.230 0.610 ;
        RECT 1293.050 0.275 1294.150 0.610 ;
        RECT 1294.970 0.275 1296.070 0.610 ;
        RECT 1296.890 0.275 1297.990 0.610 ;
        RECT 1298.810 0.275 1299.910 0.610 ;
        RECT 1300.730 0.275 1301.830 0.610 ;
        RECT 1302.650 0.275 1303.750 0.610 ;
        RECT 1304.570 0.275 1305.670 0.610 ;
        RECT 1306.490 0.275 1307.590 0.610 ;
        RECT 1308.410 0.275 1309.510 0.610 ;
        RECT 1310.330 0.275 1311.430 0.610 ;
        RECT 1312.250 0.275 1313.350 0.610 ;
        RECT 1314.170 0.275 1315.270 0.610 ;
        RECT 1316.090 0.275 1317.190 0.610 ;
        RECT 1318.010 0.275 1319.110 0.610 ;
        RECT 1319.930 0.275 1321.030 0.610 ;
        RECT 1321.850 0.275 1349.385 0.610 ;
      LAYER Metal3 ;
        RECT 0.380 65.510 1350.800 74.865 ;
        RECT 0.610 64.690 1350.590 65.510 ;
        RECT 0.380 63.830 1350.800 64.690 ;
        RECT 0.610 63.010 1350.590 63.830 ;
        RECT 0.380 62.150 1350.800 63.010 ;
        RECT 0.610 61.330 1350.590 62.150 ;
        RECT 0.380 60.470 1350.800 61.330 ;
        RECT 0.610 59.650 1350.590 60.470 ;
        RECT 0.380 58.790 1350.800 59.650 ;
        RECT 0.610 57.970 1350.590 58.790 ;
        RECT 0.380 57.110 1350.800 57.970 ;
        RECT 0.610 56.290 1350.590 57.110 ;
        RECT 0.380 55.430 1350.800 56.290 ;
        RECT 0.610 54.610 1350.590 55.430 ;
        RECT 0.380 53.750 1350.800 54.610 ;
        RECT 0.610 52.930 1350.590 53.750 ;
        RECT 0.380 52.070 1350.800 52.930 ;
        RECT 0.610 51.250 1350.590 52.070 ;
        RECT 0.380 50.390 1350.800 51.250 ;
        RECT 0.610 49.570 1350.590 50.390 ;
        RECT 0.380 48.710 1350.800 49.570 ;
        RECT 0.610 47.890 1350.590 48.710 ;
        RECT 0.380 47.030 1350.800 47.890 ;
        RECT 0.610 46.210 1350.590 47.030 ;
        RECT 0.380 45.350 1350.800 46.210 ;
        RECT 0.610 44.530 1350.590 45.350 ;
        RECT 0.380 43.670 1350.800 44.530 ;
        RECT 0.610 42.850 1350.590 43.670 ;
        RECT 0.380 41.990 1350.800 42.850 ;
        RECT 0.610 41.170 1350.590 41.990 ;
        RECT 0.380 40.310 1350.800 41.170 ;
        RECT 0.610 39.490 1350.590 40.310 ;
        RECT 0.380 38.630 1350.800 39.490 ;
        RECT 0.610 37.810 1350.590 38.630 ;
        RECT 0.380 36.950 1350.800 37.810 ;
        RECT 0.610 36.130 1350.590 36.950 ;
        RECT 0.380 35.270 1350.800 36.130 ;
        RECT 0.610 34.450 1350.590 35.270 ;
        RECT 0.380 33.590 1350.800 34.450 ;
        RECT 0.610 32.770 1350.590 33.590 ;
        RECT 0.380 31.910 1350.800 32.770 ;
        RECT 0.610 31.090 1350.590 31.910 ;
        RECT 0.380 30.230 1350.800 31.090 ;
        RECT 0.610 29.410 1350.590 30.230 ;
        RECT 0.380 28.550 1350.800 29.410 ;
        RECT 0.610 27.730 1350.590 28.550 ;
        RECT 0.380 26.870 1350.800 27.730 ;
        RECT 0.610 26.050 1350.590 26.870 ;
        RECT 0.380 25.190 1350.800 26.050 ;
        RECT 0.610 24.370 1350.590 25.190 ;
        RECT 0.380 23.510 1350.800 24.370 ;
        RECT 0.610 22.690 1350.590 23.510 ;
        RECT 0.380 21.830 1350.800 22.690 ;
        RECT 0.610 21.010 1350.590 21.830 ;
        RECT 0.380 20.150 1350.800 21.010 ;
        RECT 0.610 19.330 1350.590 20.150 ;
        RECT 0.380 18.470 1350.800 19.330 ;
        RECT 0.610 17.650 1350.590 18.470 ;
        RECT 0.380 16.790 1350.800 17.650 ;
        RECT 0.610 15.970 1350.590 16.790 ;
        RECT 0.380 15.110 1350.800 15.970 ;
        RECT 0.610 14.290 1350.590 15.110 ;
        RECT 0.380 13.430 1350.800 14.290 ;
        RECT 0.610 12.610 1350.590 13.430 ;
        RECT 0.380 2.510 1350.800 12.610 ;
        RECT 0.610 1.690 1350.590 2.510 ;
        RECT 0.380 0.315 1350.800 1.690 ;
      LAYER Metal4 ;
        RECT 15.740 0.275 60.730 74.905 ;
        RECT 62.150 0.275 63.730 74.905 ;
        RECT 65.150 0.275 110.730 74.905 ;
        RECT 112.150 0.275 113.730 74.905 ;
        RECT 115.150 0.275 160.730 74.905 ;
        RECT 162.150 0.275 163.730 74.905 ;
        RECT 165.150 0.275 210.730 74.905 ;
        RECT 212.150 0.275 213.730 74.905 ;
        RECT 215.150 0.275 260.730 74.905 ;
        RECT 262.150 0.275 263.730 74.905 ;
        RECT 265.150 0.275 280.970 74.905 ;
        RECT 282.390 0.275 283.970 74.905 ;
        RECT 285.390 0.275 330.970 74.905 ;
        RECT 332.390 0.275 333.970 74.905 ;
        RECT 335.390 0.275 380.970 74.905 ;
        RECT 382.390 0.275 383.970 74.905 ;
        RECT 385.390 0.275 430.970 74.905 ;
        RECT 432.390 0.275 433.970 74.905 ;
        RECT 435.390 0.275 480.970 74.905 ;
        RECT 482.390 0.275 483.970 74.905 ;
        RECT 485.390 0.275 530.970 74.905 ;
        RECT 532.390 0.275 533.970 74.905 ;
        RECT 535.390 0.275 551.210 74.905 ;
        RECT 552.630 0.275 554.210 74.905 ;
        RECT 555.630 0.275 601.210 74.905 ;
        RECT 602.630 0.275 604.210 74.905 ;
        RECT 605.630 0.275 651.210 74.905 ;
        RECT 652.630 0.275 654.210 74.905 ;
        RECT 655.630 0.275 701.210 74.905 ;
        RECT 702.630 0.275 704.210 74.905 ;
        RECT 705.630 0.275 751.210 74.905 ;
        RECT 752.630 0.275 754.210 74.905 ;
        RECT 755.630 0.275 801.210 74.905 ;
        RECT 802.630 0.275 804.210 74.905 ;
        RECT 805.630 0.275 821.450 74.905 ;
        RECT 822.870 0.275 824.450 74.905 ;
        RECT 825.870 0.275 871.450 74.905 ;
        RECT 872.870 0.275 874.450 74.905 ;
        RECT 875.870 0.275 921.450 74.905 ;
        RECT 922.870 0.275 924.450 74.905 ;
        RECT 925.870 0.275 971.450 74.905 ;
        RECT 972.870 0.275 974.450 74.905 ;
        RECT 975.870 0.275 1021.450 74.905 ;
        RECT 1022.870 0.275 1024.450 74.905 ;
        RECT 1025.870 0.275 1071.450 74.905 ;
        RECT 1072.870 0.275 1074.450 74.905 ;
        RECT 1075.870 0.275 1091.690 74.905 ;
        RECT 1093.110 0.275 1094.690 74.905 ;
        RECT 1096.110 0.275 1141.690 74.905 ;
        RECT 1143.110 0.275 1144.690 74.905 ;
        RECT 1146.110 0.275 1191.690 74.905 ;
        RECT 1193.110 0.275 1194.690 74.905 ;
        RECT 1196.110 0.275 1241.690 74.905 ;
        RECT 1243.110 0.275 1244.690 74.905 ;
        RECT 1246.110 0.275 1270.660 74.905 ;
  END
END NPU_ACCUM_S
END LIBRARY

